VERSION 5.8 ;
BUSBITCHARS "[]" ;
DIVIDERCHAR "/" ;
UNITS
    DATABASE MICRONS 1000 ;
END UNITS

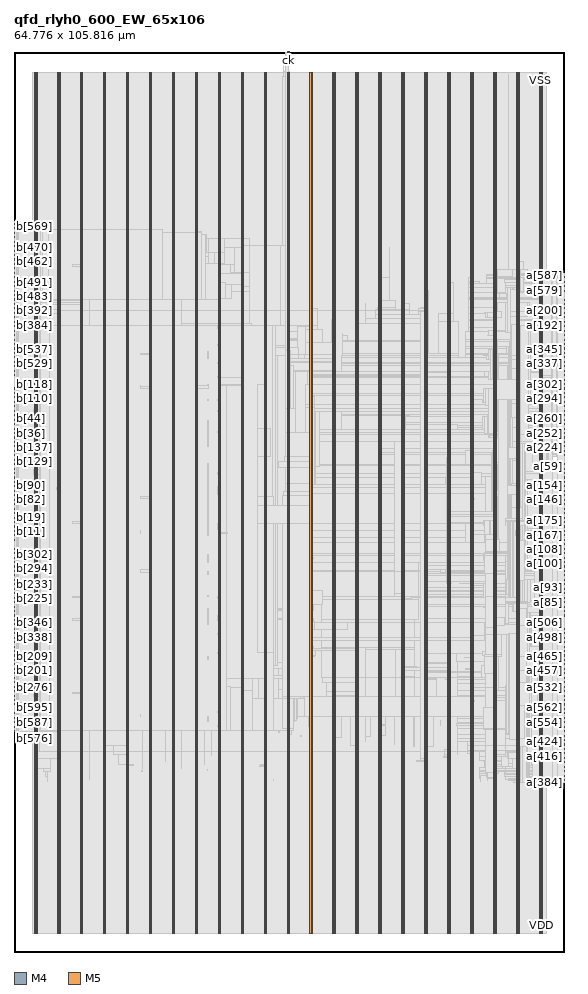
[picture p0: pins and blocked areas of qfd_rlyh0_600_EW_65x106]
MACRO qfd_rlyh0_600_EW_65x106
  FOREIGN qfd_rlyh0_600_EW_65x106 0 0 ;
  CLASS BLOCK ;
  SIZE 64.776 BY 105.816 ;
  PIN a[0]
    DIRECTION INPUT ;
    USE SIGNAL ;
    PORT
      LAYER M4 ;
        RECT  64.692 42.192 64.776 42.216 ;
    END
  END a[0]
  PIN a[100]
    DIRECTION INPUT ;
    USE SIGNAL ;
    PORT
      LAYER M4 ;
        RECT  64.692 45.648 64.776 45.672 ;
    END
  END a[100]
  PIN a[101]
    DIRECTION INPUT ;
    USE SIGNAL ;
    PORT
      LAYER M4 ;
        RECT  64.692 45.744 64.776 45.768 ;
    END
  END a[101]
  PIN a[102]
    DIRECTION INPUT ;
    USE SIGNAL ;
    PORT
      LAYER M4 ;
        RECT  64.692 45.84 64.776 45.864 ;
    END
  END a[102]
  PIN a[103]
    DIRECTION INPUT ;
    USE SIGNAL ;
    PORT
      LAYER M4 ;
        RECT  64.692 45.936 64.776 45.96 ;
    END
  END a[103]
  PIN a[104]
    DIRECTION INPUT ;
    USE SIGNAL ;
    PORT
      LAYER M4 ;
        RECT  64.692 46.032 64.776 46.056 ;
    END
  END a[104]
  PIN a[105]
    DIRECTION INPUT ;
    USE SIGNAL ;
    PORT
      LAYER M4 ;
        RECT  64.692 46.128 64.776 46.152 ;
    END
  END a[105]
  PIN a[106]
    DIRECTION INPUT ;
    USE SIGNAL ;
    PORT
      LAYER M4 ;
        RECT  64.692 46.224 64.776 46.248 ;
    END
  END a[106]
  PIN a[107]
    DIRECTION INPUT ;
    USE SIGNAL ;
    PORT
      LAYER M4 ;
        RECT  64.692 46.32 64.776 46.344 ;
    END
  END a[107]
  PIN a[108]
    DIRECTION INPUT ;
    USE SIGNAL ;
    PORT
      LAYER M4 ;
        RECT  64.692 46.416 64.776 46.44 ;
    END
  END a[108]
  PIN a[109]
    DIRECTION INPUT ;
    USE SIGNAL ;
    PORT
      LAYER M4 ;
        RECT  64.692 46.512 64.776 46.536 ;
    END
  END a[109]
  PIN a[10]
    DIRECTION INPUT ;
    USE SIGNAL ;
    PORT
      LAYER M4 ;
        RECT  64.692 43.152 64.776 43.176 ;
    END
  END a[10]
  PIN a[110]
    DIRECTION INPUT ;
    USE SIGNAL ;
    PORT
      LAYER M4 ;
        RECT  64.692 46.608 64.776 46.632 ;
    END
  END a[110]
  PIN a[111]
    DIRECTION INPUT ;
    USE SIGNAL ;
    PORT
      LAYER M4 ;
        RECT  64.692 46.704 64.776 46.728 ;
    END
  END a[111]
  PIN a[112]
    DIRECTION INPUT ;
    USE SIGNAL ;
    PORT
      LAYER M4 ;
        RECT  64.692 46.8 64.776 46.824 ;
    END
  END a[112]
  PIN a[113]
    DIRECTION INPUT ;
    USE SIGNAL ;
    PORT
      LAYER M4 ;
        RECT  64.692 46.896 64.776 46.92 ;
    END
  END a[113]
  PIN a[114]
    DIRECTION INPUT ;
    USE SIGNAL ;
    PORT
      LAYER M4 ;
        RECT  64.692 46.992 64.776 47.016 ;
    END
  END a[114]
  PIN a[115]
    DIRECTION INPUT ;
    USE SIGNAL ;
    PORT
      LAYER M4 ;
        RECT  64.692 47.088 64.776 47.112 ;
    END
  END a[115]
  PIN a[116]
    DIRECTION INPUT ;
    USE SIGNAL ;
    PORT
      LAYER M4 ;
        RECT  64.692 47.184 64.776 47.208 ;
    END
  END a[116]
  PIN a[117]
    DIRECTION INPUT ;
    USE SIGNAL ;
    PORT
      LAYER M4 ;
        RECT  64.692 47.28 64.776 47.304 ;
    END
  END a[117]
  PIN a[118]
    DIRECTION INPUT ;
    USE SIGNAL ;
    PORT
      LAYER M4 ;
        RECT  64.692 47.376 64.776 47.4 ;
    END
  END a[118]
  PIN a[119]
    DIRECTION INPUT ;
    USE SIGNAL ;
    PORT
      LAYER M4 ;
        RECT  64.692 47.472 64.776 47.496 ;
    END
  END a[119]
  PIN a[11]
    DIRECTION INPUT ;
    USE SIGNAL ;
    PORT
      LAYER M4 ;
        RECT  64.692 43.248 64.776 43.272 ;
    END
  END a[11]
  PIN a[120]
    DIRECTION INPUT ;
    USE SIGNAL ;
    PORT
      LAYER M4 ;
        RECT  64.692 47.568 64.776 47.592 ;
    END
  END a[120]
  PIN a[121]
    DIRECTION INPUT ;
    USE SIGNAL ;
    PORT
      LAYER M4 ;
        RECT  64.692 47.664 64.776 47.688 ;
    END
  END a[121]
  PIN a[122]
    DIRECTION INPUT ;
    USE SIGNAL ;
    PORT
      LAYER M4 ;
        RECT  64.692 47.76 64.776 47.784 ;
    END
  END a[122]
  PIN a[123]
    DIRECTION INPUT ;
    USE SIGNAL ;
    PORT
      LAYER M4 ;
        RECT  64.692 47.856 64.776 47.88 ;
    END
  END a[123]
  PIN a[124]
    DIRECTION INPUT ;
    USE SIGNAL ;
    PORT
      LAYER M4 ;
        RECT  64.692 47.952 64.776 47.976 ;
    END
  END a[124]
  PIN a[125]
    DIRECTION INPUT ;
    USE SIGNAL ;
    PORT
      LAYER M4 ;
        RECT  64.692 48.048 64.776 48.072 ;
    END
  END a[125]
  PIN a[126]
    DIRECTION INPUT ;
    USE SIGNAL ;
    PORT
      LAYER M4 ;
        RECT  64.692 48.144 64.776 48.168 ;
    END
  END a[126]
  PIN a[127]
    DIRECTION INPUT ;
    USE SIGNAL ;
    PORT
      LAYER M4 ;
        RECT  64.692 48.24 64.776 48.264 ;
    END
  END a[127]
  PIN a[128]
    DIRECTION INPUT ;
    USE SIGNAL ;
    PORT
      LAYER M4 ;
        RECT  64.692 51.408 64.776 51.432 ;
    END
  END a[128]
  PIN a[129]
    DIRECTION INPUT ;
    USE SIGNAL ;
    PORT
      LAYER M4 ;
        RECT  64.692 51.504 64.776 51.528 ;
    END
  END a[129]
  PIN a[12]
    DIRECTION INPUT ;
    USE SIGNAL ;
    PORT
      LAYER M4 ;
        RECT  64.692 43.344 64.776 43.368 ;
    END
  END a[12]
  PIN a[130]
    DIRECTION INPUT ;
    USE SIGNAL ;
    PORT
      LAYER M4 ;
        RECT  64.692 51.6 64.776 51.624 ;
    END
  END a[130]
  PIN a[131]
    DIRECTION INPUT ;
    USE SIGNAL ;
    PORT
      LAYER M4 ;
        RECT  64.692 51.696 64.776 51.72 ;
    END
  END a[131]
  PIN a[132]
    DIRECTION INPUT ;
    USE SIGNAL ;
    PORT
      LAYER M4 ;
        RECT  64.692 51.792 64.776 51.816 ;
    END
  END a[132]
  PIN a[133]
    DIRECTION INPUT ;
    USE SIGNAL ;
    PORT
      LAYER M4 ;
        RECT  64.692 51.888 64.776 51.912 ;
    END
  END a[133]
  PIN a[134]
    DIRECTION INPUT ;
    USE SIGNAL ;
    PORT
      LAYER M4 ;
        RECT  64.692 51.984 64.776 52.008 ;
    END
  END a[134]
  PIN a[135]
    DIRECTION INPUT ;
    USE SIGNAL ;
    PORT
      LAYER M4 ;
        RECT  64.692 52.08 64.776 52.104 ;
    END
  END a[135]
  PIN a[136]
    DIRECTION INPUT ;
    USE SIGNAL ;
    PORT
      LAYER M4 ;
        RECT  64.692 52.176 64.776 52.2 ;
    END
  END a[136]
  PIN a[137]
    DIRECTION INPUT ;
    USE SIGNAL ;
    PORT
      LAYER M4 ;
        RECT  64.692 52.272 64.776 52.296 ;
    END
  END a[137]
  PIN a[138]
    DIRECTION INPUT ;
    USE SIGNAL ;
    PORT
      LAYER M4 ;
        RECT  64.692 52.368 64.776 52.392 ;
    END
  END a[138]
  PIN a[139]
    DIRECTION INPUT ;
    USE SIGNAL ;
    PORT
      LAYER M4 ;
        RECT  64.692 52.464 64.776 52.488 ;
    END
  END a[139]
  PIN a[13]
    DIRECTION INPUT ;
    USE SIGNAL ;
    PORT
      LAYER M4 ;
        RECT  64.692 43.44 64.776 43.464 ;
    END
  END a[13]
  PIN a[140]
    DIRECTION INPUT ;
    USE SIGNAL ;
    PORT
      LAYER M4 ;
        RECT  64.692 52.56 64.776 52.584 ;
    END
  END a[140]
  PIN a[141]
    DIRECTION INPUT ;
    USE SIGNAL ;
    PORT
      LAYER M4 ;
        RECT  64.692 52.656 64.776 52.68 ;
    END
  END a[141]
  PIN a[142]
    DIRECTION INPUT ;
    USE SIGNAL ;
    PORT
      LAYER M4 ;
        RECT  64.692 52.752 64.776 52.776 ;
    END
  END a[142]
  PIN a[143]
    DIRECTION INPUT ;
    USE SIGNAL ;
    PORT
      LAYER M4 ;
        RECT  64.692 52.848 64.776 52.872 ;
    END
  END a[143]
  PIN a[144]
    DIRECTION INPUT ;
    USE SIGNAL ;
    PORT
      LAYER M4 ;
        RECT  64.692 52.944 64.776 52.968 ;
    END
  END a[144]
  PIN a[145]
    DIRECTION INPUT ;
    USE SIGNAL ;
    PORT
      LAYER M4 ;
        RECT  64.692 53.04 64.776 53.064 ;
    END
  END a[145]
  PIN a[146]
    DIRECTION INPUT ;
    USE SIGNAL ;
    PORT
      LAYER M4 ;
        RECT  64.692 53.136 64.776 53.16 ;
    END
  END a[146]
  PIN a[147]
    DIRECTION INPUT ;
    USE SIGNAL ;
    PORT
      LAYER M4 ;
        RECT  64.692 53.232 64.776 53.256 ;
    END
  END a[147]
  PIN a[148]
    DIRECTION INPUT ;
    USE SIGNAL ;
    PORT
      LAYER M4 ;
        RECT  64.692 53.328 64.776 53.352 ;
    END
  END a[148]
  PIN a[149]
    DIRECTION INPUT ;
    USE SIGNAL ;
    PORT
      LAYER M4 ;
        RECT  64.692 53.424 64.776 53.448 ;
    END
  END a[149]
  PIN a[14]
    DIRECTION INPUT ;
    USE SIGNAL ;
    PORT
      LAYER M4 ;
        RECT  64.692 43.536 64.776 43.56 ;
    END
  END a[14]
  PIN a[150]
    DIRECTION INPUT ;
    USE SIGNAL ;
    PORT
      LAYER M4 ;
        RECT  64.692 53.52 64.776 53.544 ;
    END
  END a[150]
  PIN a[151]
    DIRECTION INPUT ;
    USE SIGNAL ;
    PORT
      LAYER M4 ;
        RECT  64.692 53.616 64.776 53.64 ;
    END
  END a[151]
  PIN a[152]
    DIRECTION INPUT ;
    USE SIGNAL ;
    PORT
      LAYER M4 ;
        RECT  64.692 53.712 64.776 53.736 ;
    END
  END a[152]
  PIN a[153]
    DIRECTION INPUT ;
    USE SIGNAL ;
    PORT
      LAYER M4 ;
        RECT  64.692 53.808 64.776 53.832 ;
    END
  END a[153]
  PIN a[154]
    DIRECTION INPUT ;
    USE SIGNAL ;
    PORT
      LAYER M4 ;
        RECT  64.692 53.904 64.776 53.928 ;
    END
  END a[154]
  PIN a[155]
    DIRECTION INPUT ;
    USE SIGNAL ;
    PORT
      LAYER M4 ;
        RECT  64.692 54 64.776 54.024 ;
    END
  END a[155]
  PIN a[156]
    DIRECTION INPUT ;
    USE SIGNAL ;
    PORT
      LAYER M4 ;
        RECT  64.692 54.096 64.776 54.12 ;
    END
  END a[156]
  PIN a[157]
    DIRECTION INPUT ;
    USE SIGNAL ;
    PORT
      LAYER M4 ;
        RECT  64.692 54.192 64.776 54.216 ;
    END
  END a[157]
  PIN a[158]
    DIRECTION INPUT ;
    USE SIGNAL ;
    PORT
      LAYER M4 ;
        RECT  64.692 54.288 64.776 54.312 ;
    END
  END a[158]
  PIN a[159]
    DIRECTION INPUT ;
    USE SIGNAL ;
    PORT
      LAYER M4 ;
        RECT  64.692 54.384 64.776 54.408 ;
    END
  END a[159]
  PIN a[15]
    DIRECTION INPUT ;
    USE SIGNAL ;
    PORT
      LAYER M4 ;
        RECT  64.692 43.632 64.776 43.656 ;
    END
  END a[15]
  PIN a[160]
    DIRECTION INPUT ;
    USE SIGNAL ;
    PORT
      LAYER M4 ;
        RECT  64.692 48.336 64.776 48.36 ;
    END
  END a[160]
  PIN a[161]
    DIRECTION INPUT ;
    USE SIGNAL ;
    PORT
      LAYER M4 ;
        RECT  64.692 48.432 64.776 48.456 ;
    END
  END a[161]
  PIN a[162]
    DIRECTION INPUT ;
    USE SIGNAL ;
    PORT
      LAYER M4 ;
        RECT  64.692 48.528 64.776 48.552 ;
    END
  END a[162]
  PIN a[163]
    DIRECTION INPUT ;
    USE SIGNAL ;
    PORT
      LAYER M4 ;
        RECT  64.692 48.624 64.776 48.648 ;
    END
  END a[163]
  PIN a[164]
    DIRECTION INPUT ;
    USE SIGNAL ;
    PORT
      LAYER M4 ;
        RECT  64.692 48.72 64.776 48.744 ;
    END
  END a[164]
  PIN a[165]
    DIRECTION INPUT ;
    USE SIGNAL ;
    PORT
      LAYER M4 ;
        RECT  64.692 48.816 64.776 48.84 ;
    END
  END a[165]
  PIN a[166]
    DIRECTION INPUT ;
    USE SIGNAL ;
    PORT
      LAYER M4 ;
        RECT  64.692 48.912 64.776 48.936 ;
    END
  END a[166]
  PIN a[167]
    DIRECTION INPUT ;
    USE SIGNAL ;
    PORT
      LAYER M4 ;
        RECT  64.692 49.008 64.776 49.032 ;
    END
  END a[167]
  PIN a[168]
    DIRECTION INPUT ;
    USE SIGNAL ;
    PORT
      LAYER M4 ;
        RECT  64.692 49.104 64.776 49.128 ;
    END
  END a[168]
  PIN a[169]
    DIRECTION INPUT ;
    USE SIGNAL ;
    PORT
      LAYER M4 ;
        RECT  64.692 49.2 64.776 49.224 ;
    END
  END a[169]
  PIN a[16]
    DIRECTION INPUT ;
    USE SIGNAL ;
    PORT
      LAYER M4 ;
        RECT  64.692 43.728 64.776 43.752 ;
    END
  END a[16]
  PIN a[170]
    DIRECTION INPUT ;
    USE SIGNAL ;
    PORT
      LAYER M4 ;
        RECT  64.692 49.296 64.776 49.32 ;
    END
  END a[170]
  PIN a[171]
    DIRECTION INPUT ;
    USE SIGNAL ;
    PORT
      LAYER M4 ;
        RECT  64.692 49.392 64.776 49.416 ;
    END
  END a[171]
  PIN a[172]
    DIRECTION INPUT ;
    USE SIGNAL ;
    PORT
      LAYER M4 ;
        RECT  64.692 49.488 64.776 49.512 ;
    END
  END a[172]
  PIN a[173]
    DIRECTION INPUT ;
    USE SIGNAL ;
    PORT
      LAYER M4 ;
        RECT  64.692 49.584 64.776 49.608 ;
    END
  END a[173]
  PIN a[174]
    DIRECTION INPUT ;
    USE SIGNAL ;
    PORT
      LAYER M4 ;
        RECT  64.692 49.68 64.776 49.704 ;
    END
  END a[174]
  PIN a[175]
    DIRECTION INPUT ;
    USE SIGNAL ;
    PORT
      LAYER M4 ;
        RECT  64.692 49.776 64.776 49.8 ;
    END
  END a[175]
  PIN a[176]
    DIRECTION INPUT ;
    USE SIGNAL ;
    PORT
      LAYER M4 ;
        RECT  64.692 49.872 64.776 49.896 ;
    END
  END a[176]
  PIN a[177]
    DIRECTION INPUT ;
    USE SIGNAL ;
    PORT
      LAYER M4 ;
        RECT  64.692 49.968 64.776 49.992 ;
    END
  END a[177]
  PIN a[178]
    DIRECTION INPUT ;
    USE SIGNAL ;
    PORT
      LAYER M4 ;
        RECT  64.692 50.064 64.776 50.088 ;
    END
  END a[178]
  PIN a[179]
    DIRECTION INPUT ;
    USE SIGNAL ;
    PORT
      LAYER M4 ;
        RECT  64.692 50.16 64.776 50.184 ;
    END
  END a[179]
  PIN a[17]
    DIRECTION INPUT ;
    USE SIGNAL ;
    PORT
      LAYER M4 ;
        RECT  64.692 43.824 64.776 43.848 ;
    END
  END a[17]
  PIN a[180]
    DIRECTION INPUT ;
    USE SIGNAL ;
    PORT
      LAYER M4 ;
        RECT  64.692 50.256 64.776 50.28 ;
    END
  END a[180]
  PIN a[181]
    DIRECTION INPUT ;
    USE SIGNAL ;
    PORT
      LAYER M4 ;
        RECT  64.692 50.352 64.776 50.376 ;
    END
  END a[181]
  PIN a[182]
    DIRECTION INPUT ;
    USE SIGNAL ;
    PORT
      LAYER M4 ;
        RECT  64.692 50.448 64.776 50.472 ;
    END
  END a[182]
  PIN a[183]
    DIRECTION INPUT ;
    USE SIGNAL ;
    PORT
      LAYER M4 ;
        RECT  64.692 50.544 64.776 50.568 ;
    END
  END a[183]
  PIN a[184]
    DIRECTION INPUT ;
    USE SIGNAL ;
    PORT
      LAYER M4 ;
        RECT  64.692 50.64 64.776 50.664 ;
    END
  END a[184]
  PIN a[185]
    DIRECTION INPUT ;
    USE SIGNAL ;
    PORT
      LAYER M4 ;
        RECT  64.692 50.736 64.776 50.76 ;
    END
  END a[185]
  PIN a[186]
    DIRECTION INPUT ;
    USE SIGNAL ;
    PORT
      LAYER M4 ;
        RECT  64.692 50.832 64.776 50.856 ;
    END
  END a[186]
  PIN a[187]
    DIRECTION INPUT ;
    USE SIGNAL ;
    PORT
      LAYER M4 ;
        RECT  64.692 50.928 64.776 50.952 ;
    END
  END a[187]
  PIN a[188]
    DIRECTION INPUT ;
    USE SIGNAL ;
    PORT
      LAYER M4 ;
        RECT  64.692 51.024 64.776 51.048 ;
    END
  END a[188]
  PIN a[189]
    DIRECTION INPUT ;
    USE SIGNAL ;
    PORT
      LAYER M4 ;
        RECT  64.692 51.12 64.776 51.144 ;
    END
  END a[189]
  PIN a[18]
    DIRECTION INPUT ;
    USE SIGNAL ;
    PORT
      LAYER M4 ;
        RECT  64.692 43.92 64.776 43.944 ;
    END
  END a[18]
  PIN a[190]
    DIRECTION INPUT ;
    USE SIGNAL ;
    PORT
      LAYER M4 ;
        RECT  64.692 51.216 64.776 51.24 ;
    END
  END a[190]
  PIN a[191]
    DIRECTION INPUT ;
    USE SIGNAL ;
    PORT
      LAYER M4 ;
        RECT  64.692 51.312 64.776 51.336 ;
    END
  END a[191]
  PIN a[192]
    DIRECTION INPUT ;
    USE SIGNAL ;
    PORT
      LAYER M4 ;
        RECT  64.692 73.68 64.776 73.704 ;
    END
  END a[192]
  PIN a[193]
    DIRECTION INPUT ;
    USE SIGNAL ;
    PORT
      LAYER M4 ;
        RECT  64.692 73.776 64.776 73.8 ;
    END
  END a[193]
  PIN a[194]
    DIRECTION INPUT ;
    USE SIGNAL ;
    PORT
      LAYER M4 ;
        RECT  64.692 73.872 64.776 73.896 ;
    END
  END a[194]
  PIN a[195]
    DIRECTION INPUT ;
    USE SIGNAL ;
    PORT
      LAYER M4 ;
        RECT  64.692 73.968 64.776 73.992 ;
    END
  END a[195]
  PIN a[196]
    DIRECTION INPUT ;
    USE SIGNAL ;
    PORT
      LAYER M4 ;
        RECT  64.692 74.064 64.776 74.088 ;
    END
  END a[196]
  PIN a[197]
    DIRECTION INPUT ;
    USE SIGNAL ;
    PORT
      LAYER M4 ;
        RECT  64.692 74.16 64.776 74.184 ;
    END
  END a[197]
  PIN a[198]
    DIRECTION INPUT ;
    USE SIGNAL ;
    PORT
      LAYER M4 ;
        RECT  64.692 74.256 64.776 74.28 ;
    END
  END a[198]
  PIN a[199]
    DIRECTION INPUT ;
    USE SIGNAL ;
    PORT
      LAYER M4 ;
        RECT  64.692 74.352 64.776 74.376 ;
    END
  END a[199]
  PIN a[19]
    DIRECTION INPUT ;
    USE SIGNAL ;
    PORT
      LAYER M4 ;
        RECT  64.692 44.016 64.776 44.04 ;
    END
  END a[19]
  PIN a[1]
    DIRECTION INPUT ;
    USE SIGNAL ;
    PORT
      LAYER M4 ;
        RECT  64.692 42.288 64.776 42.312 ;
    END
  END a[1]
  PIN a[200]
    DIRECTION INPUT ;
    USE SIGNAL ;
    PORT
      LAYER M4 ;
        RECT  64.692 74.448 64.776 74.472 ;
    END
  END a[200]
  PIN a[201]
    DIRECTION INPUT ;
    USE SIGNAL ;
    PORT
      LAYER M4 ;
        RECT  64.692 74.544 64.776 74.568 ;
    END
  END a[201]
  PIN a[202]
    DIRECTION INPUT ;
    USE SIGNAL ;
    PORT
      LAYER M4 ;
        RECT  64.692 74.64 64.776 74.664 ;
    END
  END a[202]
  PIN a[203]
    DIRECTION INPUT ;
    USE SIGNAL ;
    PORT
      LAYER M4 ;
        RECT  64.692 74.736 64.776 74.76 ;
    END
  END a[203]
  PIN a[204]
    DIRECTION INPUT ;
    USE SIGNAL ;
    PORT
      LAYER M4 ;
        RECT  64.692 74.832 64.776 74.856 ;
    END
  END a[204]
  PIN a[205]
    DIRECTION INPUT ;
    USE SIGNAL ;
    PORT
      LAYER M4 ;
        RECT  64.692 74.928 64.776 74.952 ;
    END
  END a[205]
  PIN a[206]
    DIRECTION INPUT ;
    USE SIGNAL ;
    PORT
      LAYER M4 ;
        RECT  64.692 75.024 64.776 75.048 ;
    END
  END a[206]
  PIN a[207]
    DIRECTION INPUT ;
    USE SIGNAL ;
    PORT
      LAYER M4 ;
        RECT  64.692 75.12 64.776 75.144 ;
    END
  END a[207]
  PIN a[208]
    DIRECTION INPUT ;
    USE SIGNAL ;
    PORT
      LAYER M4 ;
        RECT  64.692 75.216 64.776 75.24 ;
    END
  END a[208]
  PIN a[209]
    DIRECTION INPUT ;
    USE SIGNAL ;
    PORT
      LAYER M4 ;
        RECT  64.692 75.312 64.776 75.336 ;
    END
  END a[209]
  PIN a[20]
    DIRECTION INPUT ;
    USE SIGNAL ;
    PORT
      LAYER M4 ;
        RECT  64.692 44.112 64.776 44.136 ;
    END
  END a[20]
  PIN a[210]
    DIRECTION INPUT ;
    USE SIGNAL ;
    PORT
      LAYER M4 ;
        RECT  64.692 75.408 64.776 75.432 ;
    END
  END a[210]
  PIN a[211]
    DIRECTION INPUT ;
    USE SIGNAL ;
    PORT
      LAYER M4 ;
        RECT  64.692 75.504 64.776 75.528 ;
    END
  END a[211]
  PIN a[212]
    DIRECTION INPUT ;
    USE SIGNAL ;
    PORT
      LAYER M4 ;
        RECT  64.692 75.6 64.776 75.624 ;
    END
  END a[212]
  PIN a[213]
    DIRECTION INPUT ;
    USE SIGNAL ;
    PORT
      LAYER M4 ;
        RECT  64.692 75.696 64.776 75.72 ;
    END
  END a[213]
  PIN a[214]
    DIRECTION INPUT ;
    USE SIGNAL ;
    PORT
      LAYER M4 ;
        RECT  64.692 75.792 64.776 75.816 ;
    END
  END a[214]
  PIN a[215]
    DIRECTION INPUT ;
    USE SIGNAL ;
    PORT
      LAYER M4 ;
        RECT  64.692 75.888 64.776 75.912 ;
    END
  END a[215]
  PIN a[216]
    DIRECTION INPUT ;
    USE SIGNAL ;
    PORT
      LAYER M4 ;
        RECT  64.692 75.984 64.776 76.008 ;
    END
  END a[216]
  PIN a[217]
    DIRECTION INPUT ;
    USE SIGNAL ;
    PORT
      LAYER M4 ;
        RECT  64.692 76.08 64.776 76.104 ;
    END
  END a[217]
  PIN a[218]
    DIRECTION INPUT ;
    USE SIGNAL ;
    PORT
      LAYER M4 ;
        RECT  64.692 76.176 64.776 76.2 ;
    END
  END a[218]
  PIN a[219]
    DIRECTION INPUT ;
    USE SIGNAL ;
    PORT
      LAYER M4 ;
        RECT  64.692 76.272 64.776 76.296 ;
    END
  END a[219]
  PIN a[21]
    DIRECTION INPUT ;
    USE SIGNAL ;
    PORT
      LAYER M4 ;
        RECT  64.692 44.208 64.776 44.232 ;
    END
  END a[21]
  PIN a[220]
    DIRECTION INPUT ;
    USE SIGNAL ;
    PORT
      LAYER M4 ;
        RECT  64.692 76.368 64.776 76.392 ;
    END
  END a[220]
  PIN a[221]
    DIRECTION INPUT ;
    USE SIGNAL ;
    PORT
      LAYER M4 ;
        RECT  64.692 76.464 64.776 76.488 ;
    END
  END a[221]
  PIN a[222]
    DIRECTION INPUT ;
    USE SIGNAL ;
    PORT
      LAYER M4 ;
        RECT  64.692 76.56 64.776 76.584 ;
    END
  END a[222]
  PIN a[223]
    DIRECTION INPUT ;
    USE SIGNAL ;
    PORT
      LAYER M4 ;
        RECT  64.692 76.656 64.776 76.68 ;
    END
  END a[223]
  PIN a[224]
    DIRECTION INPUT ;
    USE SIGNAL ;
    PORT
      LAYER M4 ;
        RECT  64.692 58.32 64.776 58.344 ;
    END
  END a[224]
  PIN a[225]
    DIRECTION INPUT ;
    USE SIGNAL ;
    PORT
      LAYER M4 ;
        RECT  64.692 58.416 64.776 58.44 ;
    END
  END a[225]
  PIN a[226]
    DIRECTION INPUT ;
    USE SIGNAL ;
    PORT
      LAYER M4 ;
        RECT  64.692 58.512 64.776 58.536 ;
    END
  END a[226]
  PIN a[227]
    DIRECTION INPUT ;
    USE SIGNAL ;
    PORT
      LAYER M4 ;
        RECT  64.692 58.608 64.776 58.632 ;
    END
  END a[227]
  PIN a[228]
    DIRECTION INPUT ;
    USE SIGNAL ;
    PORT
      LAYER M4 ;
        RECT  64.692 58.704 64.776 58.728 ;
    END
  END a[228]
  PIN a[229]
    DIRECTION INPUT ;
    USE SIGNAL ;
    PORT
      LAYER M4 ;
        RECT  64.692 58.8 64.776 58.824 ;
    END
  END a[229]
  PIN a[22]
    DIRECTION INPUT ;
    USE SIGNAL ;
    PORT
      LAYER M4 ;
        RECT  64.692 44.304 64.776 44.328 ;
    END
  END a[22]
  PIN a[230]
    DIRECTION INPUT ;
    USE SIGNAL ;
    PORT
      LAYER M4 ;
        RECT  64.692 58.896 64.776 58.92 ;
    END
  END a[230]
  PIN a[231]
    DIRECTION INPUT ;
    USE SIGNAL ;
    PORT
      LAYER M4 ;
        RECT  64.692 58.992 64.776 59.016 ;
    END
  END a[231]
  PIN a[232]
    DIRECTION INPUT ;
    USE SIGNAL ;
    PORT
      LAYER M4 ;
        RECT  64.692 59.088 64.776 59.112 ;
    END
  END a[232]
  PIN a[233]
    DIRECTION INPUT ;
    USE SIGNAL ;
    PORT
      LAYER M4 ;
        RECT  64.692 59.184 64.776 59.208 ;
    END
  END a[233]
  PIN a[234]
    DIRECTION INPUT ;
    USE SIGNAL ;
    PORT
      LAYER M4 ;
        RECT  64.692 59.28 64.776 59.304 ;
    END
  END a[234]
  PIN a[235]
    DIRECTION INPUT ;
    USE SIGNAL ;
    PORT
      LAYER M4 ;
        RECT  64.692 59.376 64.776 59.4 ;
    END
  END a[235]
  PIN a[236]
    DIRECTION INPUT ;
    USE SIGNAL ;
    PORT
      LAYER M4 ;
        RECT  64.692 59.472 64.776 59.496 ;
    END
  END a[236]
  PIN a[237]
    DIRECTION INPUT ;
    USE SIGNAL ;
    PORT
      LAYER M4 ;
        RECT  64.692 59.568 64.776 59.592 ;
    END
  END a[237]
  PIN a[238]
    DIRECTION INPUT ;
    USE SIGNAL ;
    PORT
      LAYER M4 ;
        RECT  64.692 59.664 64.776 59.688 ;
    END
  END a[238]
  PIN a[239]
    DIRECTION INPUT ;
    USE SIGNAL ;
    PORT
      LAYER M4 ;
        RECT  64.692 59.76 64.776 59.784 ;
    END
  END a[239]
  PIN a[23]
    DIRECTION INPUT ;
    USE SIGNAL ;
    PORT
      LAYER M4 ;
        RECT  64.692 44.4 64.776 44.424 ;
    END
  END a[23]
  PIN a[240]
    DIRECTION INPUT ;
    USE SIGNAL ;
    PORT
      LAYER M4 ;
        RECT  64.692 59.856 64.776 59.88 ;
    END
  END a[240]
  PIN a[241]
    DIRECTION INPUT ;
    USE SIGNAL ;
    PORT
      LAYER M4 ;
        RECT  64.692 59.952 64.776 59.976 ;
    END
  END a[241]
  PIN a[242]
    DIRECTION INPUT ;
    USE SIGNAL ;
    PORT
      LAYER M4 ;
        RECT  64.692 60.048 64.776 60.072 ;
    END
  END a[242]
  PIN a[243]
    DIRECTION INPUT ;
    USE SIGNAL ;
    PORT
      LAYER M4 ;
        RECT  64.692 60.144 64.776 60.168 ;
    END
  END a[243]
  PIN a[244]
    DIRECTION INPUT ;
    USE SIGNAL ;
    PORT
      LAYER M4 ;
        RECT  64.692 60.24 64.776 60.264 ;
    END
  END a[244]
  PIN a[245]
    DIRECTION INPUT ;
    USE SIGNAL ;
    PORT
      LAYER M4 ;
        RECT  64.692 60.336 64.776 60.36 ;
    END
  END a[245]
  PIN a[246]
    DIRECTION INPUT ;
    USE SIGNAL ;
    PORT
      LAYER M4 ;
        RECT  64.692 60.432 64.776 60.456 ;
    END
  END a[246]
  PIN a[247]
    DIRECTION INPUT ;
    USE SIGNAL ;
    PORT
      LAYER M4 ;
        RECT  64.692 60.528 64.776 60.552 ;
    END
  END a[247]
  PIN a[248]
    DIRECTION INPUT ;
    USE SIGNAL ;
    PORT
      LAYER M4 ;
        RECT  64.692 60.624 64.776 60.648 ;
    END
  END a[248]
  PIN a[249]
    DIRECTION INPUT ;
    USE SIGNAL ;
    PORT
      LAYER M4 ;
        RECT  64.692 60.72 64.776 60.744 ;
    END
  END a[249]
  PIN a[24]
    DIRECTION INPUT ;
    USE SIGNAL ;
    PORT
      LAYER M4 ;
        RECT  64.692 44.496 64.776 44.52 ;
    END
  END a[24]
  PIN a[250]
    DIRECTION INPUT ;
    USE SIGNAL ;
    PORT
      LAYER M4 ;
        RECT  64.692 60.816 64.776 60.84 ;
    END
  END a[250]
  PIN a[251]
    DIRECTION INPUT ;
    USE SIGNAL ;
    PORT
      LAYER M4 ;
        RECT  64.692 60.912 64.776 60.936 ;
    END
  END a[251]
  PIN a[252]
    DIRECTION INPUT ;
    USE SIGNAL ;
    PORT
      LAYER M4 ;
        RECT  64.692 61.008 64.776 61.032 ;
    END
  END a[252]
  PIN a[253]
    DIRECTION INPUT ;
    USE SIGNAL ;
    PORT
      LAYER M4 ;
        RECT  64.692 61.104 64.776 61.128 ;
    END
  END a[253]
  PIN a[254]
    DIRECTION INPUT ;
    USE SIGNAL ;
    PORT
      LAYER M4 ;
        RECT  64.692 61.2 64.776 61.224 ;
    END
  END a[254]
  PIN a[255]
    DIRECTION INPUT ;
    USE SIGNAL ;
    PORT
      LAYER M4 ;
        RECT  64.692 61.296 64.776 61.32 ;
    END
  END a[255]
  PIN a[256]
    DIRECTION INPUT ;
    USE SIGNAL ;
    PORT
      LAYER M4 ;
        RECT  64.692 61.392 64.776 61.416 ;
    END
  END a[256]
  PIN a[257]
    DIRECTION INPUT ;
    USE SIGNAL ;
    PORT
      LAYER M4 ;
        RECT  64.692 61.488 64.776 61.512 ;
    END
  END a[257]
  PIN a[258]
    DIRECTION INPUT ;
    USE SIGNAL ;
    PORT
      LAYER M4 ;
        RECT  64.692 61.584 64.776 61.608 ;
    END
  END a[258]
  PIN a[259]
    DIRECTION INPUT ;
    USE SIGNAL ;
    PORT
      LAYER M4 ;
        RECT  64.692 61.68 64.776 61.704 ;
    END
  END a[259]
  PIN a[25]
    DIRECTION INPUT ;
    USE SIGNAL ;
    PORT
      LAYER M4 ;
        RECT  64.692 44.592 64.776 44.616 ;
    END
  END a[25]
  PIN a[260]
    DIRECTION INPUT ;
    USE SIGNAL ;
    PORT
      LAYER M4 ;
        RECT  64.692 61.776 64.776 61.8 ;
    END
  END a[260]
  PIN a[261]
    DIRECTION INPUT ;
    USE SIGNAL ;
    PORT
      LAYER M4 ;
        RECT  64.692 61.872 64.776 61.896 ;
    END
  END a[261]
  PIN a[262]
    DIRECTION INPUT ;
    USE SIGNAL ;
    PORT
      LAYER M4 ;
        RECT  64.692 61.968 64.776 61.992 ;
    END
  END a[262]
  PIN a[263]
    DIRECTION INPUT ;
    USE SIGNAL ;
    PORT
      LAYER M4 ;
        RECT  64.692 62.064 64.776 62.088 ;
    END
  END a[263]
  PIN a[264]
    DIRECTION INPUT ;
    USE SIGNAL ;
    PORT
      LAYER M4 ;
        RECT  64.692 62.16 64.776 62.184 ;
    END
  END a[264]
  PIN a[265]
    DIRECTION INPUT ;
    USE SIGNAL ;
    PORT
      LAYER M4 ;
        RECT  64.692 62.256 64.776 62.28 ;
    END
  END a[265]
  PIN a[266]
    DIRECTION INPUT ;
    USE SIGNAL ;
    PORT
      LAYER M4 ;
        RECT  64.692 62.352 64.776 62.376 ;
    END
  END a[266]
  PIN a[267]
    DIRECTION INPUT ;
    USE SIGNAL ;
    PORT
      LAYER M4 ;
        RECT  64.692 62.448 64.776 62.472 ;
    END
  END a[267]
  PIN a[268]
    DIRECTION INPUT ;
    USE SIGNAL ;
    PORT
      LAYER M4 ;
        RECT  64.692 62.544 64.776 62.568 ;
    END
  END a[268]
  PIN a[269]
    DIRECTION INPUT ;
    USE SIGNAL ;
    PORT
      LAYER M4 ;
        RECT  64.692 62.64 64.776 62.664 ;
    END
  END a[269]
  PIN a[26]
    DIRECTION INPUT ;
    USE SIGNAL ;
    PORT
      LAYER M4 ;
        RECT  64.692 44.688 64.776 44.712 ;
    END
  END a[26]
  PIN a[270]
    DIRECTION INPUT ;
    USE SIGNAL ;
    PORT
      LAYER M4 ;
        RECT  64.692 62.736 64.776 62.76 ;
    END
  END a[270]
  PIN a[271]
    DIRECTION INPUT ;
    USE SIGNAL ;
    PORT
      LAYER M4 ;
        RECT  64.692 62.832 64.776 62.856 ;
    END
  END a[271]
  PIN a[272]
    DIRECTION INPUT ;
    USE SIGNAL ;
    PORT
      LAYER M4 ;
        RECT  64.692 62.928 64.776 62.952 ;
    END
  END a[272]
  PIN a[273]
    DIRECTION INPUT ;
    USE SIGNAL ;
    PORT
      LAYER M4 ;
        RECT  64.692 63.024 64.776 63.048 ;
    END
  END a[273]
  PIN a[274]
    DIRECTION INPUT ;
    USE SIGNAL ;
    PORT
      LAYER M4 ;
        RECT  64.692 63.12 64.776 63.144 ;
    END
  END a[274]
  PIN a[275]
    DIRECTION INPUT ;
    USE SIGNAL ;
    PORT
      LAYER M4 ;
        RECT  64.692 63.216 64.776 63.24 ;
    END
  END a[275]
  PIN a[276]
    DIRECTION INPUT ;
    USE SIGNAL ;
    PORT
      LAYER M4 ;
        RECT  64.692 63.312 64.776 63.336 ;
    END
  END a[276]
  PIN a[277]
    DIRECTION INPUT ;
    USE SIGNAL ;
    PORT
      LAYER M4 ;
        RECT  64.692 63.408 64.776 63.432 ;
    END
  END a[277]
  PIN a[278]
    DIRECTION INPUT ;
    USE SIGNAL ;
    PORT
      LAYER M4 ;
        RECT  64.692 63.504 64.776 63.528 ;
    END
  END a[278]
  PIN a[279]
    DIRECTION INPUT ;
    USE SIGNAL ;
    PORT
      LAYER M4 ;
        RECT  64.692 63.6 64.776 63.624 ;
    END
  END a[279]
  PIN a[27]
    DIRECTION INPUT ;
    USE SIGNAL ;
    PORT
      LAYER M4 ;
        RECT  64.692 44.784 64.776 44.808 ;
    END
  END a[27]
  PIN a[280]
    DIRECTION INPUT ;
    USE SIGNAL ;
    PORT
      LAYER M4 ;
        RECT  64.692 63.696 64.776 63.72 ;
    END
  END a[280]
  PIN a[281]
    DIRECTION INPUT ;
    USE SIGNAL ;
    PORT
      LAYER M4 ;
        RECT  64.692 63.792 64.776 63.816 ;
    END
  END a[281]
  PIN a[282]
    DIRECTION INPUT ;
    USE SIGNAL ;
    PORT
      LAYER M4 ;
        RECT  64.692 63.888 64.776 63.912 ;
    END
  END a[282]
  PIN a[283]
    DIRECTION INPUT ;
    USE SIGNAL ;
    PORT
      LAYER M4 ;
        RECT  64.692 63.984 64.776 64.008 ;
    END
  END a[283]
  PIN a[284]
    DIRECTION INPUT ;
    USE SIGNAL ;
    PORT
      LAYER M4 ;
        RECT  64.692 64.08 64.776 64.104 ;
    END
  END a[284]
  PIN a[285]
    DIRECTION INPUT ;
    USE SIGNAL ;
    PORT
      LAYER M4 ;
        RECT  64.692 64.176 64.776 64.2 ;
    END
  END a[285]
  PIN a[286]
    DIRECTION INPUT ;
    USE SIGNAL ;
    PORT
      LAYER M4 ;
        RECT  64.692 64.272 64.776 64.296 ;
    END
  END a[286]
  PIN a[287]
    DIRECTION INPUT ;
    USE SIGNAL ;
    PORT
      LAYER M4 ;
        RECT  64.692 64.368 64.776 64.392 ;
    END
  END a[287]
  PIN a[288]
    DIRECTION INPUT ;
    USE SIGNAL ;
    PORT
      LAYER M4 ;
        RECT  64.692 64.464 64.776 64.488 ;
    END
  END a[288]
  PIN a[289]
    DIRECTION INPUT ;
    USE SIGNAL ;
    PORT
      LAYER M4 ;
        RECT  64.692 64.56 64.776 64.584 ;
    END
  END a[289]
  PIN a[28]
    DIRECTION INPUT ;
    USE SIGNAL ;
    PORT
      LAYER M4 ;
        RECT  64.692 44.88 64.776 44.904 ;
    END
  END a[28]
  PIN a[290]
    DIRECTION INPUT ;
    USE SIGNAL ;
    PORT
      LAYER M4 ;
        RECT  64.692 64.656 64.776 64.68 ;
    END
  END a[290]
  PIN a[291]
    DIRECTION INPUT ;
    USE SIGNAL ;
    PORT
      LAYER M4 ;
        RECT  64.692 64.752 64.776 64.776 ;
    END
  END a[291]
  PIN a[292]
    DIRECTION INPUT ;
    USE SIGNAL ;
    PORT
      LAYER M4 ;
        RECT  64.692 64.848 64.776 64.872 ;
    END
  END a[292]
  PIN a[293]
    DIRECTION INPUT ;
    USE SIGNAL ;
    PORT
      LAYER M4 ;
        RECT  64.692 64.944 64.776 64.968 ;
    END
  END a[293]
  PIN a[294]
    DIRECTION INPUT ;
    USE SIGNAL ;
    PORT
      LAYER M4 ;
        RECT  64.692 65.04 64.776 65.064 ;
    END
  END a[294]
  PIN a[295]
    DIRECTION INPUT ;
    USE SIGNAL ;
    PORT
      LAYER M4 ;
        RECT  64.692 65.136 64.776 65.16 ;
    END
  END a[295]
  PIN a[296]
    DIRECTION INPUT ;
    USE SIGNAL ;
    PORT
      LAYER M4 ;
        RECT  64.692 65.232 64.776 65.256 ;
    END
  END a[296]
  PIN a[297]
    DIRECTION INPUT ;
    USE SIGNAL ;
    PORT
      LAYER M4 ;
        RECT  64.692 65.328 64.776 65.352 ;
    END
  END a[297]
  PIN a[298]
    DIRECTION INPUT ;
    USE SIGNAL ;
    PORT
      LAYER M4 ;
        RECT  64.692 65.424 64.776 65.448 ;
    END
  END a[298]
  PIN a[299]
    DIRECTION INPUT ;
    USE SIGNAL ;
    PORT
      LAYER M4 ;
        RECT  64.692 65.52 64.776 65.544 ;
    END
  END a[299]
  PIN a[29]
    DIRECTION INPUT ;
    USE SIGNAL ;
    PORT
      LAYER M4 ;
        RECT  64.692 44.976 64.776 45 ;
    END
  END a[29]
  PIN a[2]
    DIRECTION INPUT ;
    USE SIGNAL ;
    PORT
      LAYER M4 ;
        RECT  64.692 42.384 64.776 42.408 ;
    END
  END a[2]
  PIN a[300]
    DIRECTION INPUT ;
    USE SIGNAL ;
    PORT
      LAYER M4 ;
        RECT  64.692 65.616 64.776 65.64 ;
    END
  END a[300]
  PIN a[301]
    DIRECTION INPUT ;
    USE SIGNAL ;
    PORT
      LAYER M4 ;
        RECT  64.692 65.712 64.776 65.736 ;
    END
  END a[301]
  PIN a[302]
    DIRECTION INPUT ;
    USE SIGNAL ;
    PORT
      LAYER M4 ;
        RECT  64.692 65.808 64.776 65.832 ;
    END
  END a[302]
  PIN a[303]
    DIRECTION INPUT ;
    USE SIGNAL ;
    PORT
      LAYER M4 ;
        RECT  64.692 65.904 64.776 65.928 ;
    END
  END a[303]
  PIN a[304]
    DIRECTION INPUT ;
    USE SIGNAL ;
    PORT
      LAYER M4 ;
        RECT  64.692 66 64.776 66.024 ;
    END
  END a[304]
  PIN a[305]
    DIRECTION INPUT ;
    USE SIGNAL ;
    PORT
      LAYER M4 ;
        RECT  64.692 66.096 64.776 66.12 ;
    END
  END a[305]
  PIN a[306]
    DIRECTION INPUT ;
    USE SIGNAL ;
    PORT
      LAYER M4 ;
        RECT  64.692 66.192 64.776 66.216 ;
    END
  END a[306]
  PIN a[307]
    DIRECTION INPUT ;
    USE SIGNAL ;
    PORT
      LAYER M4 ;
        RECT  64.692 66.288 64.776 66.312 ;
    END
  END a[307]
  PIN a[308]
    DIRECTION INPUT ;
    USE SIGNAL ;
    PORT
      LAYER M4 ;
        RECT  64.692 66.384 64.776 66.408 ;
    END
  END a[308]
  PIN a[309]
    DIRECTION INPUT ;
    USE SIGNAL ;
    PORT
      LAYER M4 ;
        RECT  64.692 66.48 64.776 66.504 ;
    END
  END a[309]
  PIN a[30]
    DIRECTION INPUT ;
    USE SIGNAL ;
    PORT
      LAYER M4 ;
        RECT  64.692 45.072 64.776 45.096 ;
    END
  END a[30]
  PIN a[310]
    DIRECTION INPUT ;
    USE SIGNAL ;
    PORT
      LAYER M4 ;
        RECT  64.692 66.576 64.776 66.6 ;
    END
  END a[310]
  PIN a[311]
    DIRECTION INPUT ;
    USE SIGNAL ;
    PORT
      LAYER M4 ;
        RECT  64.692 66.672 64.776 66.696 ;
    END
  END a[311]
  PIN a[312]
    DIRECTION INPUT ;
    USE SIGNAL ;
    PORT
      LAYER M4 ;
        RECT  64.692 66.768 64.776 66.792 ;
    END
  END a[312]
  PIN a[313]
    DIRECTION INPUT ;
    USE SIGNAL ;
    PORT
      LAYER M4 ;
        RECT  64.692 66.864 64.776 66.888 ;
    END
  END a[313]
  PIN a[314]
    DIRECTION INPUT ;
    USE SIGNAL ;
    PORT
      LAYER M4 ;
        RECT  64.692 66.96 64.776 66.984 ;
    END
  END a[314]
  PIN a[315]
    DIRECTION INPUT ;
    USE SIGNAL ;
    PORT
      LAYER M4 ;
        RECT  64.692 67.056 64.776 67.08 ;
    END
  END a[315]
  PIN a[316]
    DIRECTION INPUT ;
    USE SIGNAL ;
    PORT
      LAYER M4 ;
        RECT  64.692 67.152 64.776 67.176 ;
    END
  END a[316]
  PIN a[317]
    DIRECTION INPUT ;
    USE SIGNAL ;
    PORT
      LAYER M4 ;
        RECT  64.692 67.248 64.776 67.272 ;
    END
  END a[317]
  PIN a[318]
    DIRECTION INPUT ;
    USE SIGNAL ;
    PORT
      LAYER M4 ;
        RECT  64.692 67.344 64.776 67.368 ;
    END
  END a[318]
  PIN a[319]
    DIRECTION INPUT ;
    USE SIGNAL ;
    PORT
      LAYER M4 ;
        RECT  64.692 67.44 64.776 67.464 ;
    END
  END a[319]
  PIN a[31]
    DIRECTION INPUT ;
    USE SIGNAL ;
    PORT
      LAYER M4 ;
        RECT  64.692 45.168 64.776 45.192 ;
    END
  END a[31]
  PIN a[320]
    DIRECTION INPUT ;
    USE SIGNAL ;
    PORT
      LAYER M4 ;
        RECT  64.692 67.536 64.776 67.56 ;
    END
  END a[320]
  PIN a[321]
    DIRECTION INPUT ;
    USE SIGNAL ;
    PORT
      LAYER M4 ;
        RECT  64.692 67.632 64.776 67.656 ;
    END
  END a[321]
  PIN a[322]
    DIRECTION INPUT ;
    USE SIGNAL ;
    PORT
      LAYER M4 ;
        RECT  64.692 67.728 64.776 67.752 ;
    END
  END a[322]
  PIN a[323]
    DIRECTION INPUT ;
    USE SIGNAL ;
    PORT
      LAYER M4 ;
        RECT  64.692 67.824 64.776 67.848 ;
    END
  END a[323]
  PIN a[324]
    DIRECTION INPUT ;
    USE SIGNAL ;
    PORT
      LAYER M4 ;
        RECT  64.692 67.92 64.776 67.944 ;
    END
  END a[324]
  PIN a[325]
    DIRECTION INPUT ;
    USE SIGNAL ;
    PORT
      LAYER M4 ;
        RECT  64.692 68.016 64.776 68.04 ;
    END
  END a[325]
  PIN a[326]
    DIRECTION INPUT ;
    USE SIGNAL ;
    PORT
      LAYER M4 ;
        RECT  64.692 68.112 64.776 68.136 ;
    END
  END a[326]
  PIN a[327]
    DIRECTION INPUT ;
    USE SIGNAL ;
    PORT
      LAYER M4 ;
        RECT  64.692 68.208 64.776 68.232 ;
    END
  END a[327]
  PIN a[328]
    DIRECTION INPUT ;
    USE SIGNAL ;
    PORT
      LAYER M4 ;
        RECT  64.692 68.304 64.776 68.328 ;
    END
  END a[328]
  PIN a[329]
    DIRECTION INPUT ;
    USE SIGNAL ;
    PORT
      LAYER M4 ;
        RECT  64.692 68.4 64.776 68.424 ;
    END
  END a[329]
  PIN a[32]
    DIRECTION INPUT ;
    USE SIGNAL ;
    PORT
      LAYER M4 ;
        RECT  64.692 54.48 64.776 54.504 ;
    END
  END a[32]
  PIN a[330]
    DIRECTION INPUT ;
    USE SIGNAL ;
    PORT
      LAYER M4 ;
        RECT  64.692 68.496 64.776 68.52 ;
    END
  END a[330]
  PIN a[331]
    DIRECTION INPUT ;
    USE SIGNAL ;
    PORT
      LAYER M4 ;
        RECT  64.692 68.592 64.776 68.616 ;
    END
  END a[331]
  PIN a[332]
    DIRECTION INPUT ;
    USE SIGNAL ;
    PORT
      LAYER M4 ;
        RECT  64.692 68.688 64.776 68.712 ;
    END
  END a[332]
  PIN a[333]
    DIRECTION INPUT ;
    USE SIGNAL ;
    PORT
      LAYER M4 ;
        RECT  64.692 68.784 64.776 68.808 ;
    END
  END a[333]
  PIN a[334]
    DIRECTION INPUT ;
    USE SIGNAL ;
    PORT
      LAYER M4 ;
        RECT  64.692 68.88 64.776 68.904 ;
    END
  END a[334]
  PIN a[335]
    DIRECTION INPUT ;
    USE SIGNAL ;
    PORT
      LAYER M4 ;
        RECT  64.692 68.976 64.776 69 ;
    END
  END a[335]
  PIN a[336]
    DIRECTION INPUT ;
    USE SIGNAL ;
    PORT
      LAYER M4 ;
        RECT  64.692 69.072 64.776 69.096 ;
    END
  END a[336]
  PIN a[337]
    DIRECTION INPUT ;
    USE SIGNAL ;
    PORT
      LAYER M4 ;
        RECT  64.692 69.168 64.776 69.192 ;
    END
  END a[337]
  PIN a[338]
    DIRECTION INPUT ;
    USE SIGNAL ;
    PORT
      LAYER M4 ;
        RECT  64.692 69.264 64.776 69.288 ;
    END
  END a[338]
  PIN a[339]
    DIRECTION INPUT ;
    USE SIGNAL ;
    PORT
      LAYER M4 ;
        RECT  64.692 69.36 64.776 69.384 ;
    END
  END a[339]
  PIN a[33]
    DIRECTION INPUT ;
    USE SIGNAL ;
    PORT
      LAYER M4 ;
        RECT  64.692 54.576 64.776 54.6 ;
    END
  END a[33]
  PIN a[340]
    DIRECTION INPUT ;
    USE SIGNAL ;
    PORT
      LAYER M4 ;
        RECT  64.692 69.456 64.776 69.48 ;
    END
  END a[340]
  PIN a[341]
    DIRECTION INPUT ;
    USE SIGNAL ;
    PORT
      LAYER M4 ;
        RECT  64.692 69.552 64.776 69.576 ;
    END
  END a[341]
  PIN a[342]
    DIRECTION INPUT ;
    USE SIGNAL ;
    PORT
      LAYER M4 ;
        RECT  64.692 69.648 64.776 69.672 ;
    END
  END a[342]
  PIN a[343]
    DIRECTION INPUT ;
    USE SIGNAL ;
    PORT
      LAYER M4 ;
        RECT  64.692 69.744 64.776 69.768 ;
    END
  END a[343]
  PIN a[344]
    DIRECTION INPUT ;
    USE SIGNAL ;
    PORT
      LAYER M4 ;
        RECT  64.692 69.84 64.776 69.864 ;
    END
  END a[344]
  PIN a[345]
    DIRECTION INPUT ;
    USE SIGNAL ;
    PORT
      LAYER M4 ;
        RECT  64.692 69.936 64.776 69.96 ;
    END
  END a[345]
  PIN a[346]
    DIRECTION INPUT ;
    USE SIGNAL ;
    PORT
      LAYER M4 ;
        RECT  64.692 70.032 64.776 70.056 ;
    END
  END a[346]
  PIN a[347]
    DIRECTION INPUT ;
    USE SIGNAL ;
    PORT
      LAYER M4 ;
        RECT  64.692 70.128 64.776 70.152 ;
    END
  END a[347]
  PIN a[348]
    DIRECTION INPUT ;
    USE SIGNAL ;
    PORT
      LAYER M4 ;
        RECT  64.692 70.224 64.776 70.248 ;
    END
  END a[348]
  PIN a[349]
    DIRECTION INPUT ;
    USE SIGNAL ;
    PORT
      LAYER M4 ;
        RECT  64.692 70.32 64.776 70.344 ;
    END
  END a[349]
  PIN a[34]
    DIRECTION INPUT ;
    USE SIGNAL ;
    PORT
      LAYER M4 ;
        RECT  64.692 54.672 64.776 54.696 ;
    END
  END a[34]
  PIN a[350]
    DIRECTION INPUT ;
    USE SIGNAL ;
    PORT
      LAYER M4 ;
        RECT  64.692 70.416 64.776 70.44 ;
    END
  END a[350]
  PIN a[351]
    DIRECTION INPUT ;
    USE SIGNAL ;
    PORT
      LAYER M4 ;
        RECT  64.692 70.512 64.776 70.536 ;
    END
  END a[351]
  PIN a[352]
    DIRECTION INPUT ;
    USE SIGNAL ;
    PORT
      LAYER M4 ;
        RECT  64.692 70.608 64.776 70.632 ;
    END
  END a[352]
  PIN a[353]
    DIRECTION INPUT ;
    USE SIGNAL ;
    PORT
      LAYER M4 ;
        RECT  64.692 70.704 64.776 70.728 ;
    END
  END a[353]
  PIN a[354]
    DIRECTION INPUT ;
    USE SIGNAL ;
    PORT
      LAYER M4 ;
        RECT  64.692 70.8 64.776 70.824 ;
    END
  END a[354]
  PIN a[355]
    DIRECTION INPUT ;
    USE SIGNAL ;
    PORT
      LAYER M4 ;
        RECT  64.692 70.896 64.776 70.92 ;
    END
  END a[355]
  PIN a[356]
    DIRECTION INPUT ;
    USE SIGNAL ;
    PORT
      LAYER M4 ;
        RECT  64.692 70.992 64.776 71.016 ;
    END
  END a[356]
  PIN a[357]
    DIRECTION INPUT ;
    USE SIGNAL ;
    PORT
      LAYER M4 ;
        RECT  64.692 71.088 64.776 71.112 ;
    END
  END a[357]
  PIN a[358]
    DIRECTION INPUT ;
    USE SIGNAL ;
    PORT
      LAYER M4 ;
        RECT  64.692 71.184 64.776 71.208 ;
    END
  END a[358]
  PIN a[359]
    DIRECTION INPUT ;
    USE SIGNAL ;
    PORT
      LAYER M4 ;
        RECT  64.692 71.28 64.776 71.304 ;
    END
  END a[359]
  PIN a[35]
    DIRECTION INPUT ;
    USE SIGNAL ;
    PORT
      LAYER M4 ;
        RECT  64.692 54.768 64.776 54.792 ;
    END
  END a[35]
  PIN a[360]
    DIRECTION INPUT ;
    USE SIGNAL ;
    PORT
      LAYER M4 ;
        RECT  64.692 71.376 64.776 71.4 ;
    END
  END a[360]
  PIN a[361]
    DIRECTION INPUT ;
    USE SIGNAL ;
    PORT
      LAYER M4 ;
        RECT  64.692 71.472 64.776 71.496 ;
    END
  END a[361]
  PIN a[362]
    DIRECTION INPUT ;
    USE SIGNAL ;
    PORT
      LAYER M4 ;
        RECT  64.692 71.568 64.776 71.592 ;
    END
  END a[362]
  PIN a[363]
    DIRECTION INPUT ;
    USE SIGNAL ;
    PORT
      LAYER M4 ;
        RECT  64.692 71.664 64.776 71.688 ;
    END
  END a[363]
  PIN a[364]
    DIRECTION INPUT ;
    USE SIGNAL ;
    PORT
      LAYER M4 ;
        RECT  64.692 71.76 64.776 71.784 ;
    END
  END a[364]
  PIN a[365]
    DIRECTION INPUT ;
    USE SIGNAL ;
    PORT
      LAYER M4 ;
        RECT  64.692 71.856 64.776 71.88 ;
    END
  END a[365]
  PIN a[366]
    DIRECTION INPUT ;
    USE SIGNAL ;
    PORT
      LAYER M4 ;
        RECT  64.692 71.952 64.776 71.976 ;
    END
  END a[366]
  PIN a[367]
    DIRECTION INPUT ;
    USE SIGNAL ;
    PORT
      LAYER M4 ;
        RECT  64.692 72.048 64.776 72.072 ;
    END
  END a[367]
  PIN a[368]
    DIRECTION INPUT ;
    USE SIGNAL ;
    PORT
      LAYER M4 ;
        RECT  64.692 72.144 64.776 72.168 ;
    END
  END a[368]
  PIN a[369]
    DIRECTION INPUT ;
    USE SIGNAL ;
    PORT
      LAYER M4 ;
        RECT  64.692 72.24 64.776 72.264 ;
    END
  END a[369]
  PIN a[36]
    DIRECTION INPUT ;
    USE SIGNAL ;
    PORT
      LAYER M4 ;
        RECT  64.692 54.864 64.776 54.888 ;
    END
  END a[36]
  PIN a[370]
    DIRECTION INPUT ;
    USE SIGNAL ;
    PORT
      LAYER M4 ;
        RECT  64.692 72.336 64.776 72.36 ;
    END
  END a[370]
  PIN a[371]
    DIRECTION INPUT ;
    USE SIGNAL ;
    PORT
      LAYER M4 ;
        RECT  64.692 72.432 64.776 72.456 ;
    END
  END a[371]
  PIN a[372]
    DIRECTION INPUT ;
    USE SIGNAL ;
    PORT
      LAYER M4 ;
        RECT  64.692 72.528 64.776 72.552 ;
    END
  END a[372]
  PIN a[373]
    DIRECTION INPUT ;
    USE SIGNAL ;
    PORT
      LAYER M4 ;
        RECT  64.692 72.624 64.776 72.648 ;
    END
  END a[373]
  PIN a[374]
    DIRECTION INPUT ;
    USE SIGNAL ;
    PORT
      LAYER M4 ;
        RECT  64.692 72.72 64.776 72.744 ;
    END
  END a[374]
  PIN a[375]
    DIRECTION INPUT ;
    USE SIGNAL ;
    PORT
      LAYER M4 ;
        RECT  64.692 72.816 64.776 72.84 ;
    END
  END a[375]
  PIN a[376]
    DIRECTION INPUT ;
    USE SIGNAL ;
    PORT
      LAYER M4 ;
        RECT  64.692 72.912 64.776 72.936 ;
    END
  END a[376]
  PIN a[377]
    DIRECTION INPUT ;
    USE SIGNAL ;
    PORT
      LAYER M4 ;
        RECT  64.692 73.008 64.776 73.032 ;
    END
  END a[377]
  PIN a[378]
    DIRECTION INPUT ;
    USE SIGNAL ;
    PORT
      LAYER M4 ;
        RECT  64.692 73.104 64.776 73.128 ;
    END
  END a[378]
  PIN a[379]
    DIRECTION INPUT ;
    USE SIGNAL ;
    PORT
      LAYER M4 ;
        RECT  64.692 73.2 64.776 73.224 ;
    END
  END a[379]
  PIN a[37]
    DIRECTION INPUT ;
    USE SIGNAL ;
    PORT
      LAYER M4 ;
        RECT  64.692 54.96 64.776 54.984 ;
    END
  END a[37]
  PIN a[380]
    DIRECTION INPUT ;
    USE SIGNAL ;
    PORT
      LAYER M4 ;
        RECT  64.692 73.296 64.776 73.32 ;
    END
  END a[380]
  PIN a[381]
    DIRECTION INPUT ;
    USE SIGNAL ;
    PORT
      LAYER M4 ;
        RECT  64.692 73.392 64.776 73.416 ;
    END
  END a[381]
  PIN a[382]
    DIRECTION INPUT ;
    USE SIGNAL ;
    PORT
      LAYER M4 ;
        RECT  64.692 73.488 64.776 73.512 ;
    END
  END a[382]
  PIN a[383]
    DIRECTION INPUT ;
    USE SIGNAL ;
    PORT
      LAYER M4 ;
        RECT  64.692 73.584 64.776 73.608 ;
    END
  END a[383]
  PIN a[384]
    DIRECTION INPUT ;
    USE SIGNAL ;
    PORT
      LAYER M4 ;
        RECT  64.692 19.92 64.776 19.944 ;
    END
  END a[384]
  PIN a[385]
    DIRECTION INPUT ;
    USE SIGNAL ;
    PORT
      LAYER M4 ;
        RECT  64.692 20.016 64.776 20.04 ;
    END
  END a[385]
  PIN a[386]
    DIRECTION INPUT ;
    USE SIGNAL ;
    PORT
      LAYER M4 ;
        RECT  64.692 20.112 64.776 20.136 ;
    END
  END a[386]
  PIN a[387]
    DIRECTION INPUT ;
    USE SIGNAL ;
    PORT
      LAYER M4 ;
        RECT  64.692 20.208 64.776 20.232 ;
    END
  END a[387]
  PIN a[388]
    DIRECTION INPUT ;
    USE SIGNAL ;
    PORT
      LAYER M4 ;
        RECT  64.692 20.304 64.776 20.328 ;
    END
  END a[388]
  PIN a[389]
    DIRECTION INPUT ;
    USE SIGNAL ;
    PORT
      LAYER M4 ;
        RECT  64.692 20.4 64.776 20.424 ;
    END
  END a[389]
  PIN a[38]
    DIRECTION INPUT ;
    USE SIGNAL ;
    PORT
      LAYER M4 ;
        RECT  64.692 55.056 64.776 55.08 ;
    END
  END a[38]
  PIN a[390]
    DIRECTION INPUT ;
    USE SIGNAL ;
    PORT
      LAYER M4 ;
        RECT  64.692 20.496 64.776 20.52 ;
    END
  END a[390]
  PIN a[391]
    DIRECTION INPUT ;
    USE SIGNAL ;
    PORT
      LAYER M4 ;
        RECT  64.692 20.592 64.776 20.616 ;
    END
  END a[391]
  PIN a[392]
    DIRECTION INPUT ;
    USE SIGNAL ;
    PORT
      LAYER M4 ;
        RECT  64.692 20.688 64.776 20.712 ;
    END
  END a[392]
  PIN a[393]
    DIRECTION INPUT ;
    USE SIGNAL ;
    PORT
      LAYER M4 ;
        RECT  64.692 20.784 64.776 20.808 ;
    END
  END a[393]
  PIN a[394]
    DIRECTION INPUT ;
    USE SIGNAL ;
    PORT
      LAYER M4 ;
        RECT  64.692 20.88 64.776 20.904 ;
    END
  END a[394]
  PIN a[395]
    DIRECTION INPUT ;
    USE SIGNAL ;
    PORT
      LAYER M4 ;
        RECT  64.692 20.976 64.776 21 ;
    END
  END a[395]
  PIN a[396]
    DIRECTION INPUT ;
    USE SIGNAL ;
    PORT
      LAYER M4 ;
        RECT  64.692 21.072 64.776 21.096 ;
    END
  END a[396]
  PIN a[397]
    DIRECTION INPUT ;
    USE SIGNAL ;
    PORT
      LAYER M4 ;
        RECT  64.692 21.168 64.776 21.192 ;
    END
  END a[397]
  PIN a[398]
    DIRECTION INPUT ;
    USE SIGNAL ;
    PORT
      LAYER M4 ;
        RECT  64.692 21.264 64.776 21.288 ;
    END
  END a[398]
  PIN a[399]
    DIRECTION INPUT ;
    USE SIGNAL ;
    PORT
      LAYER M4 ;
        RECT  64.692 21.36 64.776 21.384 ;
    END
  END a[399]
  PIN a[39]
    DIRECTION INPUT ;
    USE SIGNAL ;
    PORT
      LAYER M4 ;
        RECT  64.692 55.152 64.776 55.176 ;
    END
  END a[39]
  PIN a[3]
    DIRECTION INPUT ;
    USE SIGNAL ;
    PORT
      LAYER M4 ;
        RECT  64.692 42.48 64.776 42.504 ;
    END
  END a[3]
  PIN a[400]
    DIRECTION INPUT ;
    USE SIGNAL ;
    PORT
      LAYER M4 ;
        RECT  64.692 21.456 64.776 21.48 ;
    END
  END a[400]
  PIN a[401]
    DIRECTION INPUT ;
    USE SIGNAL ;
    PORT
      LAYER M4 ;
        RECT  64.692 21.552 64.776 21.576 ;
    END
  END a[401]
  PIN a[402]
    DIRECTION INPUT ;
    USE SIGNAL ;
    PORT
      LAYER M4 ;
        RECT  64.692 21.648 64.776 21.672 ;
    END
  END a[402]
  PIN a[403]
    DIRECTION INPUT ;
    USE SIGNAL ;
    PORT
      LAYER M4 ;
        RECT  64.692 21.744 64.776 21.768 ;
    END
  END a[403]
  PIN a[404]
    DIRECTION INPUT ;
    USE SIGNAL ;
    PORT
      LAYER M4 ;
        RECT  64.692 21.84 64.776 21.864 ;
    END
  END a[404]
  PIN a[405]
    DIRECTION INPUT ;
    USE SIGNAL ;
    PORT
      LAYER M4 ;
        RECT  64.692 21.936 64.776 21.96 ;
    END
  END a[405]
  PIN a[406]
    DIRECTION INPUT ;
    USE SIGNAL ;
    PORT
      LAYER M4 ;
        RECT  64.692 22.032 64.776 22.056 ;
    END
  END a[406]
  PIN a[407]
    DIRECTION INPUT ;
    USE SIGNAL ;
    PORT
      LAYER M4 ;
        RECT  64.692 22.128 64.776 22.152 ;
    END
  END a[407]
  PIN a[408]
    DIRECTION INPUT ;
    USE SIGNAL ;
    PORT
      LAYER M4 ;
        RECT  64.692 22.224 64.776 22.248 ;
    END
  END a[408]
  PIN a[409]
    DIRECTION INPUT ;
    USE SIGNAL ;
    PORT
      LAYER M4 ;
        RECT  64.692 22.32 64.776 22.344 ;
    END
  END a[409]
  PIN a[40]
    DIRECTION INPUT ;
    USE SIGNAL ;
    PORT
      LAYER M4 ;
        RECT  64.692 55.248 64.776 55.272 ;
    END
  END a[40]
  PIN a[410]
    DIRECTION INPUT ;
    USE SIGNAL ;
    PORT
      LAYER M4 ;
        RECT  64.692 22.416 64.776 22.44 ;
    END
  END a[410]
  PIN a[411]
    DIRECTION INPUT ;
    USE SIGNAL ;
    PORT
      LAYER M4 ;
        RECT  64.692 22.512 64.776 22.536 ;
    END
  END a[411]
  PIN a[412]
    DIRECTION INPUT ;
    USE SIGNAL ;
    PORT
      LAYER M4 ;
        RECT  64.692 22.608 64.776 22.632 ;
    END
  END a[412]
  PIN a[413]
    DIRECTION INPUT ;
    USE SIGNAL ;
    PORT
      LAYER M4 ;
        RECT  64.692 22.704 64.776 22.728 ;
    END
  END a[413]
  PIN a[414]
    DIRECTION INPUT ;
    USE SIGNAL ;
    PORT
      LAYER M4 ;
        RECT  64.692 22.8 64.776 22.824 ;
    END
  END a[414]
  PIN a[415]
    DIRECTION INPUT ;
    USE SIGNAL ;
    PORT
      LAYER M4 ;
        RECT  64.692 22.896 64.776 22.92 ;
    END
  END a[415]
  PIN a[416]
    DIRECTION INPUT ;
    USE SIGNAL ;
    PORT
      LAYER M4 ;
        RECT  64.692 22.992 64.776 23.016 ;
    END
  END a[416]
  PIN a[417]
    DIRECTION INPUT ;
    USE SIGNAL ;
    PORT
      LAYER M4 ;
        RECT  64.692 23.088 64.776 23.112 ;
    END
  END a[417]
  PIN a[418]
    DIRECTION INPUT ;
    USE SIGNAL ;
    PORT
      LAYER M4 ;
        RECT  64.692 23.184 64.776 23.208 ;
    END
  END a[418]
  PIN a[419]
    DIRECTION INPUT ;
    USE SIGNAL ;
    PORT
      LAYER M4 ;
        RECT  64.692 23.28 64.776 23.304 ;
    END
  END a[419]
  PIN a[41]
    DIRECTION INPUT ;
    USE SIGNAL ;
    PORT
      LAYER M4 ;
        RECT  64.692 55.344 64.776 55.368 ;
    END
  END a[41]
  PIN a[420]
    DIRECTION INPUT ;
    USE SIGNAL ;
    PORT
      LAYER M4 ;
        RECT  64.692 23.376 64.776 23.4 ;
    END
  END a[420]
  PIN a[421]
    DIRECTION INPUT ;
    USE SIGNAL ;
    PORT
      LAYER M4 ;
        RECT  64.692 23.472 64.776 23.496 ;
    END
  END a[421]
  PIN a[422]
    DIRECTION INPUT ;
    USE SIGNAL ;
    PORT
      LAYER M4 ;
        RECT  64.692 23.568 64.776 23.592 ;
    END
  END a[422]
  PIN a[423]
    DIRECTION INPUT ;
    USE SIGNAL ;
    PORT
      LAYER M4 ;
        RECT  64.692 23.664 64.776 23.688 ;
    END
  END a[423]
  PIN a[424]
    DIRECTION INPUT ;
    USE SIGNAL ;
    PORT
      LAYER M4 ;
        RECT  64.692 23.76 64.776 23.784 ;
    END
  END a[424]
  PIN a[425]
    DIRECTION INPUT ;
    USE SIGNAL ;
    PORT
      LAYER M4 ;
        RECT  64.692 23.856 64.776 23.88 ;
    END
  END a[425]
  PIN a[426]
    DIRECTION INPUT ;
    USE SIGNAL ;
    PORT
      LAYER M4 ;
        RECT  64.692 23.952 64.776 23.976 ;
    END
  END a[426]
  PIN a[427]
    DIRECTION INPUT ;
    USE SIGNAL ;
    PORT
      LAYER M4 ;
        RECT  64.692 24.048 64.776 24.072 ;
    END
  END a[427]
  PIN a[428]
    DIRECTION INPUT ;
    USE SIGNAL ;
    PORT
      LAYER M4 ;
        RECT  64.692 24.144 64.776 24.168 ;
    END
  END a[428]
  PIN a[429]
    DIRECTION INPUT ;
    USE SIGNAL ;
    PORT
      LAYER M4 ;
        RECT  64.692 24.24 64.776 24.264 ;
    END
  END a[429]
  PIN a[42]
    DIRECTION INPUT ;
    USE SIGNAL ;
    PORT
      LAYER M4 ;
        RECT  64.692 55.44 64.776 55.464 ;
    END
  END a[42]
  PIN a[430]
    DIRECTION INPUT ;
    USE SIGNAL ;
    PORT
      LAYER M4 ;
        RECT  64.692 24.336 64.776 24.36 ;
    END
  END a[430]
  PIN a[431]
    DIRECTION INPUT ;
    USE SIGNAL ;
    PORT
      LAYER M4 ;
        RECT  64.692 24.432 64.776 24.456 ;
    END
  END a[431]
  PIN a[432]
    DIRECTION INPUT ;
    USE SIGNAL ;
    PORT
      LAYER M4 ;
        RECT  64.692 24.528 64.776 24.552 ;
    END
  END a[432]
  PIN a[433]
    DIRECTION INPUT ;
    USE SIGNAL ;
    PORT
      LAYER M4 ;
        RECT  64.692 24.624 64.776 24.648 ;
    END
  END a[433]
  PIN a[434]
    DIRECTION INPUT ;
    USE SIGNAL ;
    PORT
      LAYER M4 ;
        RECT  64.692 24.72 64.776 24.744 ;
    END
  END a[434]
  PIN a[435]
    DIRECTION INPUT ;
    USE SIGNAL ;
    PORT
      LAYER M4 ;
        RECT  64.692 24.816 64.776 24.84 ;
    END
  END a[435]
  PIN a[436]
    DIRECTION INPUT ;
    USE SIGNAL ;
    PORT
      LAYER M4 ;
        RECT  64.692 24.912 64.776 24.936 ;
    END
  END a[436]
  PIN a[437]
    DIRECTION INPUT ;
    USE SIGNAL ;
    PORT
      LAYER M4 ;
        RECT  64.692 25.008 64.776 25.032 ;
    END
  END a[437]
  PIN a[438]
    DIRECTION INPUT ;
    USE SIGNAL ;
    PORT
      LAYER M4 ;
        RECT  64.692 25.104 64.776 25.128 ;
    END
  END a[438]
  PIN a[439]
    DIRECTION INPUT ;
    USE SIGNAL ;
    PORT
      LAYER M4 ;
        RECT  64.692 25.2 64.776 25.224 ;
    END
  END a[439]
  PIN a[43]
    DIRECTION INPUT ;
    USE SIGNAL ;
    PORT
      LAYER M4 ;
        RECT  64.692 55.536 64.776 55.56 ;
    END
  END a[43]
  PIN a[440]
    DIRECTION INPUT ;
    USE SIGNAL ;
    PORT
      LAYER M4 ;
        RECT  64.692 25.296 64.776 25.32 ;
    END
  END a[440]
  PIN a[441]
    DIRECTION INPUT ;
    USE SIGNAL ;
    PORT
      LAYER M4 ;
        RECT  64.692 25.392 64.776 25.416 ;
    END
  END a[441]
  PIN a[442]
    DIRECTION INPUT ;
    USE SIGNAL ;
    PORT
      LAYER M4 ;
        RECT  64.692 25.488 64.776 25.512 ;
    END
  END a[442]
  PIN a[443]
    DIRECTION INPUT ;
    USE SIGNAL ;
    PORT
      LAYER M4 ;
        RECT  64.692 25.584 64.776 25.608 ;
    END
  END a[443]
  PIN a[444]
    DIRECTION INPUT ;
    USE SIGNAL ;
    PORT
      LAYER M4 ;
        RECT  64.692 25.68 64.776 25.704 ;
    END
  END a[444]
  PIN a[445]
    DIRECTION INPUT ;
    USE SIGNAL ;
    PORT
      LAYER M4 ;
        RECT  64.692 25.776 64.776 25.8 ;
    END
  END a[445]
  PIN a[446]
    DIRECTION INPUT ;
    USE SIGNAL ;
    PORT
      LAYER M4 ;
        RECT  64.692 25.872 64.776 25.896 ;
    END
  END a[446]
  PIN a[447]
    DIRECTION INPUT ;
    USE SIGNAL ;
    PORT
      LAYER M4 ;
        RECT  64.692 25.968 64.776 25.992 ;
    END
  END a[447]
  PIN a[448]
    DIRECTION INPUT ;
    USE SIGNAL ;
    PORT
      LAYER M4 ;
        RECT  64.692 32.208 64.776 32.232 ;
    END
  END a[448]
  PIN a[449]
    DIRECTION INPUT ;
    USE SIGNAL ;
    PORT
      LAYER M4 ;
        RECT  64.692 32.304 64.776 32.328 ;
    END
  END a[449]
  PIN a[44]
    DIRECTION INPUT ;
    USE SIGNAL ;
    PORT
      LAYER M4 ;
        RECT  64.692 55.632 64.776 55.656 ;
    END
  END a[44]
  PIN a[450]
    DIRECTION INPUT ;
    USE SIGNAL ;
    PORT
      LAYER M4 ;
        RECT  64.692 32.4 64.776 32.424 ;
    END
  END a[450]
  PIN a[451]
    DIRECTION INPUT ;
    USE SIGNAL ;
    PORT
      LAYER M4 ;
        RECT  64.692 32.496 64.776 32.52 ;
    END
  END a[451]
  PIN a[452]
    DIRECTION INPUT ;
    USE SIGNAL ;
    PORT
      LAYER M4 ;
        RECT  64.692 32.592 64.776 32.616 ;
    END
  END a[452]
  PIN a[453]
    DIRECTION INPUT ;
    USE SIGNAL ;
    PORT
      LAYER M4 ;
        RECT  64.692 32.688 64.776 32.712 ;
    END
  END a[453]
  PIN a[454]
    DIRECTION INPUT ;
    USE SIGNAL ;
    PORT
      LAYER M4 ;
        RECT  64.692 32.784 64.776 32.808 ;
    END
  END a[454]
  PIN a[455]
    DIRECTION INPUT ;
    USE SIGNAL ;
    PORT
      LAYER M4 ;
        RECT  64.692 32.88 64.776 32.904 ;
    END
  END a[455]
  PIN a[456]
    DIRECTION INPUT ;
    USE SIGNAL ;
    PORT
      LAYER M4 ;
        RECT  64.692 32.976 64.776 33 ;
    END
  END a[456]
  PIN a[457]
    DIRECTION INPUT ;
    USE SIGNAL ;
    PORT
      LAYER M4 ;
        RECT  64.692 33.072 64.776 33.096 ;
    END
  END a[457]
  PIN a[458]
    DIRECTION INPUT ;
    USE SIGNAL ;
    PORT
      LAYER M4 ;
        RECT  64.692 33.168 64.776 33.192 ;
    END
  END a[458]
  PIN a[459]
    DIRECTION INPUT ;
    USE SIGNAL ;
    PORT
      LAYER M4 ;
        RECT  64.692 33.264 64.776 33.288 ;
    END
  END a[459]
  PIN a[45]
    DIRECTION INPUT ;
    USE SIGNAL ;
    PORT
      LAYER M4 ;
        RECT  64.692 55.728 64.776 55.752 ;
    END
  END a[45]
  PIN a[460]
    DIRECTION INPUT ;
    USE SIGNAL ;
    PORT
      LAYER M4 ;
        RECT  64.692 33.36 64.776 33.384 ;
    END
  END a[460]
  PIN a[461]
    DIRECTION INPUT ;
    USE SIGNAL ;
    PORT
      LAYER M4 ;
        RECT  64.692 33.456 64.776 33.48 ;
    END
  END a[461]
  PIN a[462]
    DIRECTION INPUT ;
    USE SIGNAL ;
    PORT
      LAYER M4 ;
        RECT  64.692 33.552 64.776 33.576 ;
    END
  END a[462]
  PIN a[463]
    DIRECTION INPUT ;
    USE SIGNAL ;
    PORT
      LAYER M4 ;
        RECT  64.692 33.648 64.776 33.672 ;
    END
  END a[463]
  PIN a[464]
    DIRECTION INPUT ;
    USE SIGNAL ;
    PORT
      LAYER M4 ;
        RECT  64.692 33.744 64.776 33.768 ;
    END
  END a[464]
  PIN a[465]
    DIRECTION INPUT ;
    USE SIGNAL ;
    PORT
      LAYER M4 ;
        RECT  64.692 33.84 64.776 33.864 ;
    END
  END a[465]
  PIN a[466]
    DIRECTION INPUT ;
    USE SIGNAL ;
    PORT
      LAYER M4 ;
        RECT  64.692 33.936 64.776 33.96 ;
    END
  END a[466]
  PIN a[467]
    DIRECTION INPUT ;
    USE SIGNAL ;
    PORT
      LAYER M4 ;
        RECT  64.692 34.032 64.776 34.056 ;
    END
  END a[467]
  PIN a[468]
    DIRECTION INPUT ;
    USE SIGNAL ;
    PORT
      LAYER M4 ;
        RECT  64.692 34.128 64.776 34.152 ;
    END
  END a[468]
  PIN a[469]
    DIRECTION INPUT ;
    USE SIGNAL ;
    PORT
      LAYER M4 ;
        RECT  64.692 34.224 64.776 34.248 ;
    END
  END a[469]
  PIN a[46]
    DIRECTION INPUT ;
    USE SIGNAL ;
    PORT
      LAYER M4 ;
        RECT  64.692 55.824 64.776 55.848 ;
    END
  END a[46]
  PIN a[470]
    DIRECTION INPUT ;
    USE SIGNAL ;
    PORT
      LAYER M4 ;
        RECT  64.692 34.32 64.776 34.344 ;
    END
  END a[470]
  PIN a[471]
    DIRECTION INPUT ;
    USE SIGNAL ;
    PORT
      LAYER M4 ;
        RECT  64.692 34.416 64.776 34.44 ;
    END
  END a[471]
  PIN a[472]
    DIRECTION INPUT ;
    USE SIGNAL ;
    PORT
      LAYER M4 ;
        RECT  64.692 34.512 64.776 34.536 ;
    END
  END a[472]
  PIN a[473]
    DIRECTION INPUT ;
    USE SIGNAL ;
    PORT
      LAYER M4 ;
        RECT  64.692 34.608 64.776 34.632 ;
    END
  END a[473]
  PIN a[474]
    DIRECTION INPUT ;
    USE SIGNAL ;
    PORT
      LAYER M4 ;
        RECT  64.692 34.704 64.776 34.728 ;
    END
  END a[474]
  PIN a[475]
    DIRECTION INPUT ;
    USE SIGNAL ;
    PORT
      LAYER M4 ;
        RECT  64.692 34.8 64.776 34.824 ;
    END
  END a[475]
  PIN a[476]
    DIRECTION INPUT ;
    USE SIGNAL ;
    PORT
      LAYER M4 ;
        RECT  64.692 34.896 64.776 34.92 ;
    END
  END a[476]
  PIN a[477]
    DIRECTION INPUT ;
    USE SIGNAL ;
    PORT
      LAYER M4 ;
        RECT  64.692 34.992 64.776 35.016 ;
    END
  END a[477]
  PIN a[478]
    DIRECTION INPUT ;
    USE SIGNAL ;
    PORT
      LAYER M4 ;
        RECT  64.692 35.088 64.776 35.112 ;
    END
  END a[478]
  PIN a[479]
    DIRECTION INPUT ;
    USE SIGNAL ;
    PORT
      LAYER M4 ;
        RECT  64.692 35.184 64.776 35.208 ;
    END
  END a[479]
  PIN a[47]
    DIRECTION INPUT ;
    USE SIGNAL ;
    PORT
      LAYER M4 ;
        RECT  64.692 55.92 64.776 55.944 ;
    END
  END a[47]
  PIN a[480]
    DIRECTION INPUT ;
    USE SIGNAL ;
    PORT
      LAYER M4 ;
        RECT  64.692 35.28 64.776 35.304 ;
    END
  END a[480]
  PIN a[481]
    DIRECTION INPUT ;
    USE SIGNAL ;
    PORT
      LAYER M4 ;
        RECT  64.692 35.376 64.776 35.4 ;
    END
  END a[481]
  PIN a[482]
    DIRECTION INPUT ;
    USE SIGNAL ;
    PORT
      LAYER M4 ;
        RECT  64.692 35.472 64.776 35.496 ;
    END
  END a[482]
  PIN a[483]
    DIRECTION INPUT ;
    USE SIGNAL ;
    PORT
      LAYER M4 ;
        RECT  64.692 35.568 64.776 35.592 ;
    END
  END a[483]
  PIN a[484]
    DIRECTION INPUT ;
    USE SIGNAL ;
    PORT
      LAYER M4 ;
        RECT  64.692 35.664 64.776 35.688 ;
    END
  END a[484]
  PIN a[485]
    DIRECTION INPUT ;
    USE SIGNAL ;
    PORT
      LAYER M4 ;
        RECT  64.692 35.76 64.776 35.784 ;
    END
  END a[485]
  PIN a[486]
    DIRECTION INPUT ;
    USE SIGNAL ;
    PORT
      LAYER M4 ;
        RECT  64.692 35.856 64.776 35.88 ;
    END
  END a[486]
  PIN a[487]
    DIRECTION INPUT ;
    USE SIGNAL ;
    PORT
      LAYER M4 ;
        RECT  64.692 35.952 64.776 35.976 ;
    END
  END a[487]
  PIN a[488]
    DIRECTION INPUT ;
    USE SIGNAL ;
    PORT
      LAYER M4 ;
        RECT  64.692 36.048 64.776 36.072 ;
    END
  END a[488]
  PIN a[489]
    DIRECTION INPUT ;
    USE SIGNAL ;
    PORT
      LAYER M4 ;
        RECT  64.692 36.144 64.776 36.168 ;
    END
  END a[489]
  PIN a[48]
    DIRECTION INPUT ;
    USE SIGNAL ;
    PORT
      LAYER M4 ;
        RECT  64.692 56.016 64.776 56.04 ;
    END
  END a[48]
  PIN a[490]
    DIRECTION INPUT ;
    USE SIGNAL ;
    PORT
      LAYER M4 ;
        RECT  64.692 36.24 64.776 36.264 ;
    END
  END a[490]
  PIN a[491]
    DIRECTION INPUT ;
    USE SIGNAL ;
    PORT
      LAYER M4 ;
        RECT  64.692 36.336 64.776 36.36 ;
    END
  END a[491]
  PIN a[492]
    DIRECTION INPUT ;
    USE SIGNAL ;
    PORT
      LAYER M4 ;
        RECT  64.692 36.432 64.776 36.456 ;
    END
  END a[492]
  PIN a[493]
    DIRECTION INPUT ;
    USE SIGNAL ;
    PORT
      LAYER M4 ;
        RECT  64.692 36.528 64.776 36.552 ;
    END
  END a[493]
  PIN a[494]
    DIRECTION INPUT ;
    USE SIGNAL ;
    PORT
      LAYER M4 ;
        RECT  64.692 36.624 64.776 36.648 ;
    END
  END a[494]
  PIN a[495]
    DIRECTION INPUT ;
    USE SIGNAL ;
    PORT
      LAYER M4 ;
        RECT  64.692 36.72 64.776 36.744 ;
    END
  END a[495]
  PIN a[496]
    DIRECTION INPUT ;
    USE SIGNAL ;
    PORT
      LAYER M4 ;
        RECT  64.692 36.816 64.776 36.84 ;
    END
  END a[496]
  PIN a[497]
    DIRECTION INPUT ;
    USE SIGNAL ;
    PORT
      LAYER M4 ;
        RECT  64.692 36.912 64.776 36.936 ;
    END
  END a[497]
  PIN a[498]
    DIRECTION INPUT ;
    USE SIGNAL ;
    PORT
      LAYER M4 ;
        RECT  64.692 37.008 64.776 37.032 ;
    END
  END a[498]
  PIN a[499]
    DIRECTION INPUT ;
    USE SIGNAL ;
    PORT
      LAYER M4 ;
        RECT  64.692 37.104 64.776 37.128 ;
    END
  END a[499]
  PIN a[49]
    DIRECTION INPUT ;
    USE SIGNAL ;
    PORT
      LAYER M4 ;
        RECT  64.692 56.112 64.776 56.136 ;
    END
  END a[49]
  PIN a[4]
    DIRECTION INPUT ;
    USE SIGNAL ;
    PORT
      LAYER M4 ;
        RECT  64.692 42.576 64.776 42.6 ;
    END
  END a[4]
  PIN a[500]
    DIRECTION INPUT ;
    USE SIGNAL ;
    PORT
      LAYER M4 ;
        RECT  64.692 37.2 64.776 37.224 ;
    END
  END a[500]
  PIN a[501]
    DIRECTION INPUT ;
    USE SIGNAL ;
    PORT
      LAYER M4 ;
        RECT  64.692 37.296 64.776 37.32 ;
    END
  END a[501]
  PIN a[502]
    DIRECTION INPUT ;
    USE SIGNAL ;
    PORT
      LAYER M4 ;
        RECT  64.692 37.392 64.776 37.416 ;
    END
  END a[502]
  PIN a[503]
    DIRECTION INPUT ;
    USE SIGNAL ;
    PORT
      LAYER M4 ;
        RECT  64.692 37.488 64.776 37.512 ;
    END
  END a[503]
  PIN a[504]
    DIRECTION INPUT ;
    USE SIGNAL ;
    PORT
      LAYER M4 ;
        RECT  64.692 37.584 64.776 37.608 ;
    END
  END a[504]
  PIN a[505]
    DIRECTION INPUT ;
    USE SIGNAL ;
    PORT
      LAYER M4 ;
        RECT  64.692 37.68 64.776 37.704 ;
    END
  END a[505]
  PIN a[506]
    DIRECTION INPUT ;
    USE SIGNAL ;
    PORT
      LAYER M4 ;
        RECT  64.692 37.776 64.776 37.8 ;
    END
  END a[506]
  PIN a[507]
    DIRECTION INPUT ;
    USE SIGNAL ;
    PORT
      LAYER M4 ;
        RECT  64.692 37.872 64.776 37.896 ;
    END
  END a[507]
  PIN a[508]
    DIRECTION INPUT ;
    USE SIGNAL ;
    PORT
      LAYER M4 ;
        RECT  64.692 37.968 64.776 37.992 ;
    END
  END a[508]
  PIN a[509]
    DIRECTION INPUT ;
    USE SIGNAL ;
    PORT
      LAYER M4 ;
        RECT  64.692 38.064 64.776 38.088 ;
    END
  END a[509]
  PIN a[50]
    DIRECTION INPUT ;
    USE SIGNAL ;
    PORT
      LAYER M4 ;
        RECT  64.692 56.208 64.776 56.232 ;
    END
  END a[50]
  PIN a[510]
    DIRECTION INPUT ;
    USE SIGNAL ;
    PORT
      LAYER M4 ;
        RECT  64.692 38.16 64.776 38.184 ;
    END
  END a[510]
  PIN a[511]
    DIRECTION INPUT ;
    USE SIGNAL ;
    PORT
      LAYER M4 ;
        RECT  64.692 38.256 64.776 38.28 ;
    END
  END a[511]
  PIN a[512]
    DIRECTION INPUT ;
    USE SIGNAL ;
    PORT
      LAYER M4 ;
        RECT  64.692 29.136 64.776 29.16 ;
    END
  END a[512]
  PIN a[513]
    DIRECTION INPUT ;
    USE SIGNAL ;
    PORT
      LAYER M4 ;
        RECT  64.692 29.232 64.776 29.256 ;
    END
  END a[513]
  PIN a[514]
    DIRECTION INPUT ;
    USE SIGNAL ;
    PORT
      LAYER M4 ;
        RECT  64.692 29.328 64.776 29.352 ;
    END
  END a[514]
  PIN a[515]
    DIRECTION INPUT ;
    USE SIGNAL ;
    PORT
      LAYER M4 ;
        RECT  64.692 29.424 64.776 29.448 ;
    END
  END a[515]
  PIN a[516]
    DIRECTION INPUT ;
    USE SIGNAL ;
    PORT
      LAYER M4 ;
        RECT  64.692 29.52 64.776 29.544 ;
    END
  END a[516]
  PIN a[517]
    DIRECTION INPUT ;
    USE SIGNAL ;
    PORT
      LAYER M4 ;
        RECT  64.692 29.616 64.776 29.64 ;
    END
  END a[517]
  PIN a[518]
    DIRECTION INPUT ;
    USE SIGNAL ;
    PORT
      LAYER M4 ;
        RECT  64.692 29.712 64.776 29.736 ;
    END
  END a[518]
  PIN a[519]
    DIRECTION INPUT ;
    USE SIGNAL ;
    PORT
      LAYER M4 ;
        RECT  64.692 29.808 64.776 29.832 ;
    END
  END a[519]
  PIN a[51]
    DIRECTION INPUT ;
    USE SIGNAL ;
    PORT
      LAYER M4 ;
        RECT  64.692 56.304 64.776 56.328 ;
    END
  END a[51]
  PIN a[520]
    DIRECTION INPUT ;
    USE SIGNAL ;
    PORT
      LAYER M4 ;
        RECT  64.692 29.904 64.776 29.928 ;
    END
  END a[520]
  PIN a[521]
    DIRECTION INPUT ;
    USE SIGNAL ;
    PORT
      LAYER M4 ;
        RECT  64.692 30 64.776 30.024 ;
    END
  END a[521]
  PIN a[522]
    DIRECTION INPUT ;
    USE SIGNAL ;
    PORT
      LAYER M4 ;
        RECT  64.692 30.096 64.776 30.12 ;
    END
  END a[522]
  PIN a[523]
    DIRECTION INPUT ;
    USE SIGNAL ;
    PORT
      LAYER M4 ;
        RECT  64.692 30.192 64.776 30.216 ;
    END
  END a[523]
  PIN a[524]
    DIRECTION INPUT ;
    USE SIGNAL ;
    PORT
      LAYER M4 ;
        RECT  64.692 30.288 64.776 30.312 ;
    END
  END a[524]
  PIN a[525]
    DIRECTION INPUT ;
    USE SIGNAL ;
    PORT
      LAYER M4 ;
        RECT  64.692 30.384 64.776 30.408 ;
    END
  END a[525]
  PIN a[526]
    DIRECTION INPUT ;
    USE SIGNAL ;
    PORT
      LAYER M4 ;
        RECT  64.692 30.48 64.776 30.504 ;
    END
  END a[526]
  PIN a[527]
    DIRECTION INPUT ;
    USE SIGNAL ;
    PORT
      LAYER M4 ;
        RECT  64.692 30.576 64.776 30.6 ;
    END
  END a[527]
  PIN a[528]
    DIRECTION INPUT ;
    USE SIGNAL ;
    PORT
      LAYER M4 ;
        RECT  64.692 30.672 64.776 30.696 ;
    END
  END a[528]
  PIN a[529]
    DIRECTION INPUT ;
    USE SIGNAL ;
    PORT
      LAYER M4 ;
        RECT  64.692 30.768 64.776 30.792 ;
    END
  END a[529]
  PIN a[52]
    DIRECTION INPUT ;
    USE SIGNAL ;
    PORT
      LAYER M4 ;
        RECT  64.692 56.4 64.776 56.424 ;
    END
  END a[52]
  PIN a[530]
    DIRECTION INPUT ;
    USE SIGNAL ;
    PORT
      LAYER M4 ;
        RECT  64.692 30.864 64.776 30.888 ;
    END
  END a[530]
  PIN a[531]
    DIRECTION INPUT ;
    USE SIGNAL ;
    PORT
      LAYER M4 ;
        RECT  64.692 30.96 64.776 30.984 ;
    END
  END a[531]
  PIN a[532]
    DIRECTION INPUT ;
    USE SIGNAL ;
    PORT
      LAYER M4 ;
        RECT  64.692 31.056 64.776 31.08 ;
    END
  END a[532]
  PIN a[533]
    DIRECTION INPUT ;
    USE SIGNAL ;
    PORT
      LAYER M4 ;
        RECT  64.692 31.152 64.776 31.176 ;
    END
  END a[533]
  PIN a[534]
    DIRECTION INPUT ;
    USE SIGNAL ;
    PORT
      LAYER M4 ;
        RECT  64.692 31.248 64.776 31.272 ;
    END
  END a[534]
  PIN a[535]
    DIRECTION INPUT ;
    USE SIGNAL ;
    PORT
      LAYER M4 ;
        RECT  64.692 31.344 64.776 31.368 ;
    END
  END a[535]
  PIN a[536]
    DIRECTION INPUT ;
    USE SIGNAL ;
    PORT
      LAYER M4 ;
        RECT  64.692 31.44 64.776 31.464 ;
    END
  END a[536]
  PIN a[537]
    DIRECTION INPUT ;
    USE SIGNAL ;
    PORT
      LAYER M4 ;
        RECT  64.692 31.536 64.776 31.56 ;
    END
  END a[537]
  PIN a[538]
    DIRECTION INPUT ;
    USE SIGNAL ;
    PORT
      LAYER M4 ;
        RECT  64.692 31.632 64.776 31.656 ;
    END
  END a[538]
  PIN a[539]
    DIRECTION INPUT ;
    USE SIGNAL ;
    PORT
      LAYER M4 ;
        RECT  64.692 31.728 64.776 31.752 ;
    END
  END a[539]
  PIN a[53]
    DIRECTION INPUT ;
    USE SIGNAL ;
    PORT
      LAYER M4 ;
        RECT  64.692 56.496 64.776 56.52 ;
    END
  END a[53]
  PIN a[540]
    DIRECTION INPUT ;
    USE SIGNAL ;
    PORT
      LAYER M4 ;
        RECT  64.692 31.824 64.776 31.848 ;
    END
  END a[540]
  PIN a[541]
    DIRECTION INPUT ;
    USE SIGNAL ;
    PORT
      LAYER M4 ;
        RECT  64.692 31.92 64.776 31.944 ;
    END
  END a[541]
  PIN a[542]
    DIRECTION INPUT ;
    USE SIGNAL ;
    PORT
      LAYER M4 ;
        RECT  64.692 32.016 64.776 32.04 ;
    END
  END a[542]
  PIN a[543]
    DIRECTION INPUT ;
    USE SIGNAL ;
    PORT
      LAYER M4 ;
        RECT  64.692 32.112 64.776 32.136 ;
    END
  END a[543]
  PIN a[544]
    DIRECTION INPUT ;
    USE SIGNAL ;
    PORT
      LAYER M4 ;
        RECT  64.692 26.064 64.776 26.088 ;
    END
  END a[544]
  PIN a[545]
    DIRECTION INPUT ;
    USE SIGNAL ;
    PORT
      LAYER M4 ;
        RECT  64.692 26.16 64.776 26.184 ;
    END
  END a[545]
  PIN a[546]
    DIRECTION INPUT ;
    USE SIGNAL ;
    PORT
      LAYER M4 ;
        RECT  64.692 26.256 64.776 26.28 ;
    END
  END a[546]
  PIN a[547]
    DIRECTION INPUT ;
    USE SIGNAL ;
    PORT
      LAYER M4 ;
        RECT  64.692 26.352 64.776 26.376 ;
    END
  END a[547]
  PIN a[548]
    DIRECTION INPUT ;
    USE SIGNAL ;
    PORT
      LAYER M4 ;
        RECT  64.692 26.448 64.776 26.472 ;
    END
  END a[548]
  PIN a[549]
    DIRECTION INPUT ;
    USE SIGNAL ;
    PORT
      LAYER M4 ;
        RECT  64.692 26.544 64.776 26.568 ;
    END
  END a[549]
  PIN a[54]
    DIRECTION INPUT ;
    USE SIGNAL ;
    PORT
      LAYER M4 ;
        RECT  64.692 56.592 64.776 56.616 ;
    END
  END a[54]
  PIN a[550]
    DIRECTION INPUT ;
    USE SIGNAL ;
    PORT
      LAYER M4 ;
        RECT  64.692 26.64 64.776 26.664 ;
    END
  END a[550]
  PIN a[551]
    DIRECTION INPUT ;
    USE SIGNAL ;
    PORT
      LAYER M4 ;
        RECT  64.692 26.736 64.776 26.76 ;
    END
  END a[551]
  PIN a[552]
    DIRECTION INPUT ;
    USE SIGNAL ;
    PORT
      LAYER M4 ;
        RECT  64.692 26.832 64.776 26.856 ;
    END
  END a[552]
  PIN a[553]
    DIRECTION INPUT ;
    USE SIGNAL ;
    PORT
      LAYER M4 ;
        RECT  64.692 26.928 64.776 26.952 ;
    END
  END a[553]
  PIN a[554]
    DIRECTION INPUT ;
    USE SIGNAL ;
    PORT
      LAYER M4 ;
        RECT  64.692 27.024 64.776 27.048 ;
    END
  END a[554]
  PIN a[555]
    DIRECTION INPUT ;
    USE SIGNAL ;
    PORT
      LAYER M4 ;
        RECT  64.692 27.12 64.776 27.144 ;
    END
  END a[555]
  PIN a[556]
    DIRECTION INPUT ;
    USE SIGNAL ;
    PORT
      LAYER M4 ;
        RECT  64.692 27.216 64.776 27.24 ;
    END
  END a[556]
  PIN a[557]
    DIRECTION INPUT ;
    USE SIGNAL ;
    PORT
      LAYER M4 ;
        RECT  64.692 27.312 64.776 27.336 ;
    END
  END a[557]
  PIN a[558]
    DIRECTION INPUT ;
    USE SIGNAL ;
    PORT
      LAYER M4 ;
        RECT  64.692 27.408 64.776 27.432 ;
    END
  END a[558]
  PIN a[559]
    DIRECTION INPUT ;
    USE SIGNAL ;
    PORT
      LAYER M4 ;
        RECT  64.692 27.504 64.776 27.528 ;
    END
  END a[559]
  PIN a[55]
    DIRECTION INPUT ;
    USE SIGNAL ;
    PORT
      LAYER M4 ;
        RECT  64.692 56.688 64.776 56.712 ;
    END
  END a[55]
  PIN a[560]
    DIRECTION INPUT ;
    USE SIGNAL ;
    PORT
      LAYER M4 ;
        RECT  64.692 27.6 64.776 27.624 ;
    END
  END a[560]
  PIN a[561]
    DIRECTION INPUT ;
    USE SIGNAL ;
    PORT
      LAYER M4 ;
        RECT  64.692 27.696 64.776 27.72 ;
    END
  END a[561]
  PIN a[562]
    DIRECTION INPUT ;
    USE SIGNAL ;
    PORT
      LAYER M4 ;
        RECT  64.692 27.792 64.776 27.816 ;
    END
  END a[562]
  PIN a[563]
    DIRECTION INPUT ;
    USE SIGNAL ;
    PORT
      LAYER M4 ;
        RECT  64.692 27.888 64.776 27.912 ;
    END
  END a[563]
  PIN a[564]
    DIRECTION INPUT ;
    USE SIGNAL ;
    PORT
      LAYER M4 ;
        RECT  64.692 27.984 64.776 28.008 ;
    END
  END a[564]
  PIN a[565]
    DIRECTION INPUT ;
    USE SIGNAL ;
    PORT
      LAYER M4 ;
        RECT  64.692 28.08 64.776 28.104 ;
    END
  END a[565]
  PIN a[566]
    DIRECTION INPUT ;
    USE SIGNAL ;
    PORT
      LAYER M4 ;
        RECT  64.692 28.176 64.776 28.2 ;
    END
  END a[566]
  PIN a[567]
    DIRECTION INPUT ;
    USE SIGNAL ;
    PORT
      LAYER M4 ;
        RECT  64.692 28.272 64.776 28.296 ;
    END
  END a[567]
  PIN a[568]
    DIRECTION INPUT ;
    USE SIGNAL ;
    PORT
      LAYER M4 ;
        RECT  64.692 28.368 64.776 28.392 ;
    END
  END a[568]
  PIN a[569]
    DIRECTION INPUT ;
    USE SIGNAL ;
    PORT
      LAYER M4 ;
        RECT  64.692 28.464 64.776 28.488 ;
    END
  END a[569]
  PIN a[56]
    DIRECTION INPUT ;
    USE SIGNAL ;
    PORT
      LAYER M4 ;
        RECT  64.692 56.784 64.776 56.808 ;
    END
  END a[56]
  PIN a[570]
    DIRECTION INPUT ;
    USE SIGNAL ;
    PORT
      LAYER M4 ;
        RECT  64.692 28.56 64.776 28.584 ;
    END
  END a[570]
  PIN a[571]
    DIRECTION INPUT ;
    USE SIGNAL ;
    PORT
      LAYER M4 ;
        RECT  64.692 28.656 64.776 28.68 ;
    END
  END a[571]
  PIN a[572]
    DIRECTION INPUT ;
    USE SIGNAL ;
    PORT
      LAYER M4 ;
        RECT  64.692 28.752 64.776 28.776 ;
    END
  END a[572]
  PIN a[573]
    DIRECTION INPUT ;
    USE SIGNAL ;
    PORT
      LAYER M4 ;
        RECT  64.692 28.848 64.776 28.872 ;
    END
  END a[573]
  PIN a[574]
    DIRECTION INPUT ;
    USE SIGNAL ;
    PORT
      LAYER M4 ;
        RECT  64.692 28.944 64.776 28.968 ;
    END
  END a[574]
  PIN a[575]
    DIRECTION INPUT ;
    USE SIGNAL ;
    PORT
      LAYER M4 ;
        RECT  64.692 29.04 64.776 29.064 ;
    END
  END a[575]
  PIN a[576]
    DIRECTION INPUT ;
    USE SIGNAL ;
    PORT
      LAYER M4 ;
        RECT  64.692 77.52 64.776 77.544 ;
    END
  END a[576]
  PIN a[577]
    DIRECTION INPUT ;
    USE SIGNAL ;
    PORT
      LAYER M4 ;
        RECT  64.692 77.616 64.776 77.64 ;
    END
  END a[577]
  PIN a[578]
    DIRECTION INPUT ;
    USE SIGNAL ;
    PORT
      LAYER M4 ;
        RECT  64.692 77.712 64.776 77.736 ;
    END
  END a[578]
  PIN a[579]
    DIRECTION INPUT ;
    USE SIGNAL ;
    PORT
      LAYER M4 ;
        RECT  64.692 77.808 64.776 77.832 ;
    END
  END a[579]
  PIN a[57]
    DIRECTION INPUT ;
    USE SIGNAL ;
    PORT
      LAYER M4 ;
        RECT  64.692 56.88 64.776 56.904 ;
    END
  END a[57]
  PIN a[580]
    DIRECTION INPUT ;
    USE SIGNAL ;
    PORT
      LAYER M4 ;
        RECT  64.692 77.904 64.776 77.928 ;
    END
  END a[580]
  PIN a[581]
    DIRECTION INPUT ;
    USE SIGNAL ;
    PORT
      LAYER M4 ;
        RECT  64.692 78 64.776 78.024 ;
    END
  END a[581]
  PIN a[582]
    DIRECTION INPUT ;
    USE SIGNAL ;
    PORT
      LAYER M4 ;
        RECT  64.692 78.096 64.776 78.12 ;
    END
  END a[582]
  PIN a[583]
    DIRECTION INPUT ;
    USE SIGNAL ;
    PORT
      LAYER M4 ;
        RECT  64.692 78.192 64.776 78.216 ;
    END
  END a[583]
  PIN a[584]
    DIRECTION INPUT ;
    USE SIGNAL ;
    PORT
      LAYER M4 ;
        RECT  64.692 78.288 64.776 78.312 ;
    END
  END a[584]
  PIN a[585]
    DIRECTION INPUT ;
    USE SIGNAL ;
    PORT
      LAYER M4 ;
        RECT  64.692 78.384 64.776 78.408 ;
    END
  END a[585]
  PIN a[586]
    DIRECTION INPUT ;
    USE SIGNAL ;
    PORT
      LAYER M4 ;
        RECT  64.692 78.48 64.776 78.504 ;
    END
  END a[586]
  PIN a[587]
    DIRECTION INPUT ;
    USE SIGNAL ;
    PORT
      LAYER M4 ;
        RECT  64.692 78.576 64.776 78.6 ;
    END
  END a[587]
  PIN a[588]
    DIRECTION INPUT ;
    USE SIGNAL ;
    PORT
      LAYER M4 ;
        RECT  64.692 78.672 64.776 78.696 ;
    END
  END a[588]
  PIN a[589]
    DIRECTION INPUT ;
    USE SIGNAL ;
    PORT
      LAYER M4 ;
        RECT  64.692 78.768 64.776 78.792 ;
    END
  END a[589]
  PIN a[58]
    DIRECTION INPUT ;
    USE SIGNAL ;
    PORT
      LAYER M4 ;
        RECT  64.692 56.976 64.776 57 ;
    END
  END a[58]
  PIN a[590]
    DIRECTION INPUT ;
    USE SIGNAL ;
    PORT
      LAYER M4 ;
        RECT  64.692 78.864 64.776 78.888 ;
    END
  END a[590]
  PIN a[591]
    DIRECTION INPUT ;
    USE SIGNAL ;
    PORT
      LAYER M4 ;
        RECT  64.692 78.96 64.776 78.984 ;
    END
  END a[591]
  PIN a[592]
    DIRECTION INPUT ;
    USE SIGNAL ;
    PORT
      LAYER M4 ;
        RECT  64.692 79.056 64.776 79.08 ;
    END
  END a[592]
  PIN a[593]
    DIRECTION INPUT ;
    USE SIGNAL ;
    PORT
      LAYER M4 ;
        RECT  64.692 79.152 64.776 79.176 ;
    END
  END a[593]
  PIN a[594]
    DIRECTION INPUT ;
    USE SIGNAL ;
    PORT
      LAYER M4 ;
        RECT  64.692 79.248 64.776 79.272 ;
    END
  END a[594]
  PIN a[595]
    DIRECTION INPUT ;
    USE SIGNAL ;
    PORT
      LAYER M4 ;
        RECT  64.692 79.344 64.776 79.368 ;
    END
  END a[595]
  PIN a[596]
    DIRECTION INPUT ;
    USE SIGNAL ;
    PORT
      LAYER M4 ;
        RECT  64.692 79.44 64.776 79.464 ;
    END
  END a[596]
  PIN a[597]
    DIRECTION INPUT ;
    USE SIGNAL ;
    PORT
      LAYER M4 ;
        RECT  64.692 79.536 64.776 79.56 ;
    END
  END a[597]
  PIN a[598]
    DIRECTION INPUT ;
    USE SIGNAL ;
    PORT
      LAYER M4 ;
        RECT  64.692 79.632 64.776 79.656 ;
    END
  END a[598]
  PIN a[599]
    DIRECTION INPUT ;
    USE SIGNAL ;
    PORT
      LAYER M4 ;
        RECT  64.692 79.728 64.776 79.752 ;
    END
  END a[599]
  PIN a[59]
    DIRECTION INPUT ;
    USE SIGNAL ;
    PORT
      LAYER M4 ;
        RECT  64.692 57.072 64.776 57.096 ;
    END
  END a[59]
  PIN a[5]
    DIRECTION INPUT ;
    USE SIGNAL ;
    PORT
      LAYER M4 ;
        RECT  64.692 42.672 64.776 42.696 ;
    END
  END a[5]
  PIN a[60]
    DIRECTION INPUT ;
    USE SIGNAL ;
    PORT
      LAYER M4 ;
        RECT  64.692 57.168 64.776 57.192 ;
    END
  END a[60]
  PIN a[61]
    DIRECTION INPUT ;
    USE SIGNAL ;
    PORT
      LAYER M4 ;
        RECT  64.692 57.264 64.776 57.288 ;
    END
  END a[61]
  PIN a[62]
    DIRECTION INPUT ;
    USE SIGNAL ;
    PORT
      LAYER M4 ;
        RECT  64.692 57.36 64.776 57.384 ;
    END
  END a[62]
  PIN a[63]
    DIRECTION INPUT ;
    USE SIGNAL ;
    PORT
      LAYER M4 ;
        RECT  64.692 57.456 64.776 57.48 ;
    END
  END a[63]
  PIN a[64]
    DIRECTION INPUT ;
    USE SIGNAL ;
    PORT
      LAYER M4 ;
        RECT  64.692 39.12 64.776 39.144 ;
    END
  END a[64]
  PIN a[65]
    DIRECTION INPUT ;
    USE SIGNAL ;
    PORT
      LAYER M4 ;
        RECT  64.692 39.216 64.776 39.24 ;
    END
  END a[65]
  PIN a[66]
    DIRECTION INPUT ;
    USE SIGNAL ;
    PORT
      LAYER M4 ;
        RECT  64.692 39.312 64.776 39.336 ;
    END
  END a[66]
  PIN a[67]
    DIRECTION INPUT ;
    USE SIGNAL ;
    PORT
      LAYER M4 ;
        RECT  64.692 39.408 64.776 39.432 ;
    END
  END a[67]
  PIN a[68]
    DIRECTION INPUT ;
    USE SIGNAL ;
    PORT
      LAYER M4 ;
        RECT  64.692 39.504 64.776 39.528 ;
    END
  END a[68]
  PIN a[69]
    DIRECTION INPUT ;
    USE SIGNAL ;
    PORT
      LAYER M4 ;
        RECT  64.692 39.6 64.776 39.624 ;
    END
  END a[69]
  PIN a[6]
    DIRECTION INPUT ;
    USE SIGNAL ;
    PORT
      LAYER M4 ;
        RECT  64.692 42.768 64.776 42.792 ;
    END
  END a[6]
  PIN a[70]
    DIRECTION INPUT ;
    USE SIGNAL ;
    PORT
      LAYER M4 ;
        RECT  64.692 39.696 64.776 39.72 ;
    END
  END a[70]
  PIN a[71]
    DIRECTION INPUT ;
    USE SIGNAL ;
    PORT
      LAYER M4 ;
        RECT  64.692 39.792 64.776 39.816 ;
    END
  END a[71]
  PIN a[72]
    DIRECTION INPUT ;
    USE SIGNAL ;
    PORT
      LAYER M4 ;
        RECT  64.692 39.888 64.776 39.912 ;
    END
  END a[72]
  PIN a[73]
    DIRECTION INPUT ;
    USE SIGNAL ;
    PORT
      LAYER M4 ;
        RECT  64.692 39.984 64.776 40.008 ;
    END
  END a[73]
  PIN a[74]
    DIRECTION INPUT ;
    USE SIGNAL ;
    PORT
      LAYER M4 ;
        RECT  64.692 40.08 64.776 40.104 ;
    END
  END a[74]
  PIN a[75]
    DIRECTION INPUT ;
    USE SIGNAL ;
    PORT
      LAYER M4 ;
        RECT  64.692 40.176 64.776 40.2 ;
    END
  END a[75]
  PIN a[76]
    DIRECTION INPUT ;
    USE SIGNAL ;
    PORT
      LAYER M4 ;
        RECT  64.692 40.272 64.776 40.296 ;
    END
  END a[76]
  PIN a[77]
    DIRECTION INPUT ;
    USE SIGNAL ;
    PORT
      LAYER M4 ;
        RECT  64.692 40.368 64.776 40.392 ;
    END
  END a[77]
  PIN a[78]
    DIRECTION INPUT ;
    USE SIGNAL ;
    PORT
      LAYER M4 ;
        RECT  64.692 40.464 64.776 40.488 ;
    END
  END a[78]
  PIN a[79]
    DIRECTION INPUT ;
    USE SIGNAL ;
    PORT
      LAYER M4 ;
        RECT  64.692 40.56 64.776 40.584 ;
    END
  END a[79]
  PIN a[7]
    DIRECTION INPUT ;
    USE SIGNAL ;
    PORT
      LAYER M4 ;
        RECT  64.692 42.864 64.776 42.888 ;
    END
  END a[7]
  PIN a[80]
    DIRECTION INPUT ;
    USE SIGNAL ;
    PORT
      LAYER M4 ;
        RECT  64.692 40.656 64.776 40.68 ;
    END
  END a[80]
  PIN a[81]
    DIRECTION INPUT ;
    USE SIGNAL ;
    PORT
      LAYER M4 ;
        RECT  64.692 40.752 64.776 40.776 ;
    END
  END a[81]
  PIN a[82]
    DIRECTION INPUT ;
    USE SIGNAL ;
    PORT
      LAYER M4 ;
        RECT  64.692 40.848 64.776 40.872 ;
    END
  END a[82]
  PIN a[83]
    DIRECTION INPUT ;
    USE SIGNAL ;
    PORT
      LAYER M4 ;
        RECT  64.692 40.944 64.776 40.968 ;
    END
  END a[83]
  PIN a[84]
    DIRECTION INPUT ;
    USE SIGNAL ;
    PORT
      LAYER M4 ;
        RECT  64.692 41.04 64.776 41.064 ;
    END
  END a[84]
  PIN a[85]
    DIRECTION INPUT ;
    USE SIGNAL ;
    PORT
      LAYER M4 ;
        RECT  64.692 41.136 64.776 41.16 ;
    END
  END a[85]
  PIN a[86]
    DIRECTION INPUT ;
    USE SIGNAL ;
    PORT
      LAYER M4 ;
        RECT  64.692 41.232 64.776 41.256 ;
    END
  END a[86]
  PIN a[87]
    DIRECTION INPUT ;
    USE SIGNAL ;
    PORT
      LAYER M4 ;
        RECT  64.692 41.328 64.776 41.352 ;
    END
  END a[87]
  PIN a[88]
    DIRECTION INPUT ;
    USE SIGNAL ;
    PORT
      LAYER M4 ;
        RECT  64.692 41.424 64.776 41.448 ;
    END
  END a[88]
  PIN a[89]
    DIRECTION INPUT ;
    USE SIGNAL ;
    PORT
      LAYER M4 ;
        RECT  64.692 41.52 64.776 41.544 ;
    END
  END a[89]
  PIN a[8]
    DIRECTION INPUT ;
    USE SIGNAL ;
    PORT
      LAYER M4 ;
        RECT  64.692 42.96 64.776 42.984 ;
    END
  END a[8]
  PIN a[90]
    DIRECTION INPUT ;
    USE SIGNAL ;
    PORT
      LAYER M4 ;
        RECT  64.692 41.616 64.776 41.64 ;
    END
  END a[90]
  PIN a[91]
    DIRECTION INPUT ;
    USE SIGNAL ;
    PORT
      LAYER M4 ;
        RECT  64.692 41.712 64.776 41.736 ;
    END
  END a[91]
  PIN a[92]
    DIRECTION INPUT ;
    USE SIGNAL ;
    PORT
      LAYER M4 ;
        RECT  64.692 41.808 64.776 41.832 ;
    END
  END a[92]
  PIN a[93]
    DIRECTION INPUT ;
    USE SIGNAL ;
    PORT
      LAYER M4 ;
        RECT  64.692 41.904 64.776 41.928 ;
    END
  END a[93]
  PIN a[94]
    DIRECTION INPUT ;
    USE SIGNAL ;
    PORT
      LAYER M4 ;
        RECT  64.692 42 64.776 42.024 ;
    END
  END a[94]
  PIN a[95]
    DIRECTION INPUT ;
    USE SIGNAL ;
    PORT
      LAYER M4 ;
        RECT  64.692 42.096 64.776 42.12 ;
    END
  END a[95]
  PIN a[96]
    DIRECTION INPUT ;
    USE SIGNAL ;
    PORT
      LAYER M4 ;
        RECT  64.692 45.264 64.776 45.288 ;
    END
  END a[96]
  PIN a[97]
    DIRECTION INPUT ;
    USE SIGNAL ;
    PORT
      LAYER M4 ;
        RECT  64.692 45.36 64.776 45.384 ;
    END
  END a[97]
  PIN a[98]
    DIRECTION INPUT ;
    USE SIGNAL ;
    PORT
      LAYER M4 ;
        RECT  64.692 45.456 64.776 45.48 ;
    END
  END a[98]
  PIN a[99]
    DIRECTION INPUT ;
    USE SIGNAL ;
    PORT
      LAYER M4 ;
        RECT  64.692 45.552 64.776 45.576 ;
    END
  END a[99]
  PIN a[9]
    DIRECTION INPUT ;
    USE SIGNAL ;
    PORT
      LAYER M4 ;
        RECT  64.692 43.056 64.776 43.08 ;
    END
  END a[9]
  PIN b[0]
    DIRECTION OUTPUT ;
    USE SIGNAL ;
    PORT
      LAYER M4 ;
        RECT  0 48.336 0.084 48.36 ;
    END
  END b[0]
  PIN b[100]
    DIRECTION OUTPUT ;
    USE SIGNAL ;
    PORT
      LAYER M4 ;
        RECT  0 64.08 0.084 64.104 ;
    END
  END b[100]
  PIN b[101]
    DIRECTION OUTPUT ;
    USE SIGNAL ;
    PORT
      LAYER M4 ;
        RECT  0 64.176 0.084 64.2 ;
    END
  END b[101]
  PIN b[102]
    DIRECTION OUTPUT ;
    USE SIGNAL ;
    PORT
      LAYER M4 ;
        RECT  0 64.272 0.084 64.296 ;
    END
  END b[102]
  PIN b[103]
    DIRECTION OUTPUT ;
    USE SIGNAL ;
    PORT
      LAYER M4 ;
        RECT  0 64.368 0.084 64.392 ;
    END
  END b[103]
  PIN b[104]
    DIRECTION OUTPUT ;
    USE SIGNAL ;
    PORT
      LAYER M4 ;
        RECT  0 64.464 0.084 64.488 ;
    END
  END b[104]
  PIN b[105]
    DIRECTION OUTPUT ;
    USE SIGNAL ;
    PORT
      LAYER M4 ;
        RECT  0 64.56 0.084 64.584 ;
    END
  END b[105]
  PIN b[106]
    DIRECTION OUTPUT ;
    USE SIGNAL ;
    PORT
      LAYER M4 ;
        RECT  0 64.656 0.084 64.68 ;
    END
  END b[106]
  PIN b[107]
    DIRECTION OUTPUT ;
    USE SIGNAL ;
    PORT
      LAYER M4 ;
        RECT  0 64.752 0.084 64.776 ;
    END
  END b[107]
  PIN b[108]
    DIRECTION OUTPUT ;
    USE SIGNAL ;
    PORT
      LAYER M4 ;
        RECT  0 64.848 0.084 64.872 ;
    END
  END b[108]
  PIN b[109]
    DIRECTION OUTPUT ;
    USE SIGNAL ;
    PORT
      LAYER M4 ;
        RECT  0 64.944 0.084 64.968 ;
    END
  END b[109]
  PIN b[10]
    DIRECTION OUTPUT ;
    USE SIGNAL ;
    PORT
      LAYER M4 ;
        RECT  0 49.296 0.084 49.32 ;
    END
  END b[10]
  PIN b[110]
    DIRECTION OUTPUT ;
    USE SIGNAL ;
    PORT
      LAYER M4 ;
        RECT  0 65.04 0.084 65.064 ;
    END
  END b[110]
  PIN b[111]
    DIRECTION OUTPUT ;
    USE SIGNAL ;
    PORT
      LAYER M4 ;
        RECT  0 65.136 0.084 65.16 ;
    END
  END b[111]
  PIN b[112]
    DIRECTION OUTPUT ;
    USE SIGNAL ;
    PORT
      LAYER M4 ;
        RECT  0 65.232 0.084 65.256 ;
    END
  END b[112]
  PIN b[113]
    DIRECTION OUTPUT ;
    USE SIGNAL ;
    PORT
      LAYER M4 ;
        RECT  0 65.328 0.084 65.352 ;
    END
  END b[113]
  PIN b[114]
    DIRECTION OUTPUT ;
    USE SIGNAL ;
    PORT
      LAYER M4 ;
        RECT  0 65.424 0.084 65.448 ;
    END
  END b[114]
  PIN b[115]
    DIRECTION OUTPUT ;
    USE SIGNAL ;
    PORT
      LAYER M4 ;
        RECT  0 65.52 0.084 65.544 ;
    END
  END b[115]
  PIN b[116]
    DIRECTION OUTPUT ;
    USE SIGNAL ;
    PORT
      LAYER M4 ;
        RECT  0 65.616 0.084 65.64 ;
    END
  END b[116]
  PIN b[117]
    DIRECTION OUTPUT ;
    USE SIGNAL ;
    PORT
      LAYER M4 ;
        RECT  0 65.712 0.084 65.736 ;
    END
  END b[117]
  PIN b[118]
    DIRECTION OUTPUT ;
    USE SIGNAL ;
    PORT
      LAYER M4 ;
        RECT  0 65.808 0.084 65.832 ;
    END
  END b[118]
  PIN b[119]
    DIRECTION OUTPUT ;
    USE SIGNAL ;
    PORT
      LAYER M4 ;
        RECT  0 65.904 0.084 65.928 ;
    END
  END b[119]
  PIN b[11]
    DIRECTION OUTPUT ;
    USE SIGNAL ;
    PORT
      LAYER M4 ;
        RECT  0 49.392 0.084 49.416 ;
    END
  END b[11]
  PIN b[120]
    DIRECTION OUTPUT ;
    USE SIGNAL ;
    PORT
      LAYER M4 ;
        RECT  0 66 0.084 66.024 ;
    END
  END b[120]
  PIN b[121]
    DIRECTION OUTPUT ;
    USE SIGNAL ;
    PORT
      LAYER M4 ;
        RECT  0 66.096 0.084 66.12 ;
    END
  END b[121]
  PIN b[122]
    DIRECTION OUTPUT ;
    USE SIGNAL ;
    PORT
      LAYER M4 ;
        RECT  0 66.192 0.084 66.216 ;
    END
  END b[122]
  PIN b[123]
    DIRECTION OUTPUT ;
    USE SIGNAL ;
    PORT
      LAYER M4 ;
        RECT  0 66.288 0.084 66.312 ;
    END
  END b[123]
  PIN b[124]
    DIRECTION OUTPUT ;
    USE SIGNAL ;
    PORT
      LAYER M4 ;
        RECT  0 66.384 0.084 66.408 ;
    END
  END b[124]
  PIN b[125]
    DIRECTION OUTPUT ;
    USE SIGNAL ;
    PORT
      LAYER M4 ;
        RECT  0 66.48 0.084 66.504 ;
    END
  END b[125]
  PIN b[126]
    DIRECTION OUTPUT ;
    USE SIGNAL ;
    PORT
      LAYER M4 ;
        RECT  0 66.576 0.084 66.6 ;
    END
  END b[126]
  PIN b[127]
    DIRECTION OUTPUT ;
    USE SIGNAL ;
    PORT
      LAYER M4 ;
        RECT  0 66.672 0.084 66.696 ;
    END
  END b[127]
  PIN b[128]
    DIRECTION OUTPUT ;
    USE SIGNAL ;
    PORT
      LAYER M4 ;
        RECT  0 57.552 0.084 57.576 ;
    END
  END b[128]
  PIN b[129]
    DIRECTION OUTPUT ;
    USE SIGNAL ;
    PORT
      LAYER M4 ;
        RECT  0 57.648 0.084 57.672 ;
    END
  END b[129]
  PIN b[12]
    DIRECTION OUTPUT ;
    USE SIGNAL ;
    PORT
      LAYER M4 ;
        RECT  0 49.488 0.084 49.512 ;
    END
  END b[12]
  PIN b[130]
    DIRECTION OUTPUT ;
    USE SIGNAL ;
    PORT
      LAYER M4 ;
        RECT  0 57.744 0.084 57.768 ;
    END
  END b[130]
  PIN b[131]
    DIRECTION OUTPUT ;
    USE SIGNAL ;
    PORT
      LAYER M4 ;
        RECT  0 57.84 0.084 57.864 ;
    END
  END b[131]
  PIN b[132]
    DIRECTION OUTPUT ;
    USE SIGNAL ;
    PORT
      LAYER M4 ;
        RECT  0 57.936 0.084 57.96 ;
    END
  END b[132]
  PIN b[133]
    DIRECTION OUTPUT ;
    USE SIGNAL ;
    PORT
      LAYER M4 ;
        RECT  0 58.032 0.084 58.056 ;
    END
  END b[133]
  PIN b[134]
    DIRECTION OUTPUT ;
    USE SIGNAL ;
    PORT
      LAYER M4 ;
        RECT  0 58.128 0.084 58.152 ;
    END
  END b[134]
  PIN b[135]
    DIRECTION OUTPUT ;
    USE SIGNAL ;
    PORT
      LAYER M4 ;
        RECT  0 58.224 0.084 58.248 ;
    END
  END b[135]
  PIN b[136]
    DIRECTION OUTPUT ;
    USE SIGNAL ;
    PORT
      LAYER M4 ;
        RECT  0 58.32 0.084 58.344 ;
    END
  END b[136]
  PIN b[137]
    DIRECTION OUTPUT ;
    USE SIGNAL ;
    PORT
      LAYER M4 ;
        RECT  0 58.416 0.084 58.44 ;
    END
  END b[137]
  PIN b[138]
    DIRECTION OUTPUT ;
    USE SIGNAL ;
    PORT
      LAYER M4 ;
        RECT  0 58.512 0.084 58.536 ;
    END
  END b[138]
  PIN b[139]
    DIRECTION OUTPUT ;
    USE SIGNAL ;
    PORT
      LAYER M4 ;
        RECT  0 58.608 0.084 58.632 ;
    END
  END b[139]
  PIN b[13]
    DIRECTION OUTPUT ;
    USE SIGNAL ;
    PORT
      LAYER M4 ;
        RECT  0 49.584 0.084 49.608 ;
    END
  END b[13]
  PIN b[140]
    DIRECTION OUTPUT ;
    USE SIGNAL ;
    PORT
      LAYER M4 ;
        RECT  0 58.704 0.084 58.728 ;
    END
  END b[140]
  PIN b[141]
    DIRECTION OUTPUT ;
    USE SIGNAL ;
    PORT
      LAYER M4 ;
        RECT  0 58.8 0.084 58.824 ;
    END
  END b[141]
  PIN b[142]
    DIRECTION OUTPUT ;
    USE SIGNAL ;
    PORT
      LAYER M4 ;
        RECT  0 58.896 0.084 58.92 ;
    END
  END b[142]
  PIN b[143]
    DIRECTION OUTPUT ;
    USE SIGNAL ;
    PORT
      LAYER M4 ;
        RECT  0 58.992 0.084 59.016 ;
    END
  END b[143]
  PIN b[144]
    DIRECTION OUTPUT ;
    USE SIGNAL ;
    PORT
      LAYER M4 ;
        RECT  0 59.088 0.084 59.112 ;
    END
  END b[144]
  PIN b[145]
    DIRECTION OUTPUT ;
    USE SIGNAL ;
    PORT
      LAYER M4 ;
        RECT  0 59.184 0.084 59.208 ;
    END
  END b[145]
  PIN b[146]
    DIRECTION OUTPUT ;
    USE SIGNAL ;
    PORT
      LAYER M4 ;
        RECT  0 59.28 0.084 59.304 ;
    END
  END b[146]
  PIN b[147]
    DIRECTION OUTPUT ;
    USE SIGNAL ;
    PORT
      LAYER M4 ;
        RECT  0 59.376 0.084 59.4 ;
    END
  END b[147]
  PIN b[148]
    DIRECTION OUTPUT ;
    USE SIGNAL ;
    PORT
      LAYER M4 ;
        RECT  0 59.472 0.084 59.496 ;
    END
  END b[148]
  PIN b[149]
    DIRECTION OUTPUT ;
    USE SIGNAL ;
    PORT
      LAYER M4 ;
        RECT  0 59.568 0.084 59.592 ;
    END
  END b[149]
  PIN b[14]
    DIRECTION OUTPUT ;
    USE SIGNAL ;
    PORT
      LAYER M4 ;
        RECT  0 49.68 0.084 49.704 ;
    END
  END b[14]
  PIN b[150]
    DIRECTION OUTPUT ;
    USE SIGNAL ;
    PORT
      LAYER M4 ;
        RECT  0 59.664 0.084 59.688 ;
    END
  END b[150]
  PIN b[151]
    DIRECTION OUTPUT ;
    USE SIGNAL ;
    PORT
      LAYER M4 ;
        RECT  0 59.76 0.084 59.784 ;
    END
  END b[151]
  PIN b[152]
    DIRECTION OUTPUT ;
    USE SIGNAL ;
    PORT
      LAYER M4 ;
        RECT  0 59.856 0.084 59.88 ;
    END
  END b[152]
  PIN b[153]
    DIRECTION OUTPUT ;
    USE SIGNAL ;
    PORT
      LAYER M4 ;
        RECT  0 59.952 0.084 59.976 ;
    END
  END b[153]
  PIN b[154]
    DIRECTION OUTPUT ;
    USE SIGNAL ;
    PORT
      LAYER M4 ;
        RECT  0 60.048 0.084 60.072 ;
    END
  END b[154]
  PIN b[155]
    DIRECTION OUTPUT ;
    USE SIGNAL ;
    PORT
      LAYER M4 ;
        RECT  0 60.144 0.084 60.168 ;
    END
  END b[155]
  PIN b[156]
    DIRECTION OUTPUT ;
    USE SIGNAL ;
    PORT
      LAYER M4 ;
        RECT  0 60.24 0.084 60.264 ;
    END
  END b[156]
  PIN b[157]
    DIRECTION OUTPUT ;
    USE SIGNAL ;
    PORT
      LAYER M4 ;
        RECT  0 60.336 0.084 60.36 ;
    END
  END b[157]
  PIN b[158]
    DIRECTION OUTPUT ;
    USE SIGNAL ;
    PORT
      LAYER M4 ;
        RECT  0 60.432 0.084 60.456 ;
    END
  END b[158]
  PIN b[159]
    DIRECTION OUTPUT ;
    USE SIGNAL ;
    PORT
      LAYER M4 ;
        RECT  0 60.528 0.084 60.552 ;
    END
  END b[159]
  PIN b[15]
    DIRECTION OUTPUT ;
    USE SIGNAL ;
    PORT
      LAYER M4 ;
        RECT  0 49.776 0.084 49.8 ;
    END
  END b[15]
  PIN b[160]
    DIRECTION OUTPUT ;
    USE SIGNAL ;
    PORT
      LAYER M4 ;
        RECT  0 54.48 0.084 54.504 ;
    END
  END b[160]
  PIN b[161]
    DIRECTION OUTPUT ;
    USE SIGNAL ;
    PORT
      LAYER M4 ;
        RECT  0 54.576 0.084 54.6 ;
    END
  END b[161]
  PIN b[162]
    DIRECTION OUTPUT ;
    USE SIGNAL ;
    PORT
      LAYER M4 ;
        RECT  0 54.672 0.084 54.696 ;
    END
  END b[162]
  PIN b[163]
    DIRECTION OUTPUT ;
    USE SIGNAL ;
    PORT
      LAYER M4 ;
        RECT  0 54.768 0.084 54.792 ;
    END
  END b[163]
  PIN b[164]
    DIRECTION OUTPUT ;
    USE SIGNAL ;
    PORT
      LAYER M4 ;
        RECT  0 54.864 0.084 54.888 ;
    END
  END b[164]
  PIN b[165]
    DIRECTION OUTPUT ;
    USE SIGNAL ;
    PORT
      LAYER M4 ;
        RECT  0 54.96 0.084 54.984 ;
    END
  END b[165]
  PIN b[166]
    DIRECTION OUTPUT ;
    USE SIGNAL ;
    PORT
      LAYER M4 ;
        RECT  0 55.056 0.084 55.08 ;
    END
  END b[166]
  PIN b[167]
    DIRECTION OUTPUT ;
    USE SIGNAL ;
    PORT
      LAYER M4 ;
        RECT  0 55.152 0.084 55.176 ;
    END
  END b[167]
  PIN b[168]
    DIRECTION OUTPUT ;
    USE SIGNAL ;
    PORT
      LAYER M4 ;
        RECT  0 55.248 0.084 55.272 ;
    END
  END b[168]
  PIN b[169]
    DIRECTION OUTPUT ;
    USE SIGNAL ;
    PORT
      LAYER M4 ;
        RECT  0 55.344 0.084 55.368 ;
    END
  END b[169]
  PIN b[16]
    DIRECTION OUTPUT ;
    USE SIGNAL ;
    PORT
      LAYER M4 ;
        RECT  0 49.872 0.084 49.896 ;
    END
  END b[16]
  PIN b[170]
    DIRECTION OUTPUT ;
    USE SIGNAL ;
    PORT
      LAYER M4 ;
        RECT  0 55.44 0.084 55.464 ;
    END
  END b[170]
  PIN b[171]
    DIRECTION OUTPUT ;
    USE SIGNAL ;
    PORT
      LAYER M4 ;
        RECT  0 55.536 0.084 55.56 ;
    END
  END b[171]
  PIN b[172]
    DIRECTION OUTPUT ;
    USE SIGNAL ;
    PORT
      LAYER M4 ;
        RECT  0 55.632 0.084 55.656 ;
    END
  END b[172]
  PIN b[173]
    DIRECTION OUTPUT ;
    USE SIGNAL ;
    PORT
      LAYER M4 ;
        RECT  0 55.728 0.084 55.752 ;
    END
  END b[173]
  PIN b[174]
    DIRECTION OUTPUT ;
    USE SIGNAL ;
    PORT
      LAYER M4 ;
        RECT  0 55.824 0.084 55.848 ;
    END
  END b[174]
  PIN b[175]
    DIRECTION OUTPUT ;
    USE SIGNAL ;
    PORT
      LAYER M4 ;
        RECT  0 55.92 0.084 55.944 ;
    END
  END b[175]
  PIN b[176]
    DIRECTION OUTPUT ;
    USE SIGNAL ;
    PORT
      LAYER M4 ;
        RECT  0 56.016 0.084 56.04 ;
    END
  END b[176]
  PIN b[177]
    DIRECTION OUTPUT ;
    USE SIGNAL ;
    PORT
      LAYER M4 ;
        RECT  0 56.112 0.084 56.136 ;
    END
  END b[177]
  PIN b[178]
    DIRECTION OUTPUT ;
    USE SIGNAL ;
    PORT
      LAYER M4 ;
        RECT  0 56.208 0.084 56.232 ;
    END
  END b[178]
  PIN b[179]
    DIRECTION OUTPUT ;
    USE SIGNAL ;
    PORT
      LAYER M4 ;
        RECT  0 56.304 0.084 56.328 ;
    END
  END b[179]
  PIN b[17]
    DIRECTION OUTPUT ;
    USE SIGNAL ;
    PORT
      LAYER M4 ;
        RECT  0 49.968 0.084 49.992 ;
    END
  END b[17]
  PIN b[180]
    DIRECTION OUTPUT ;
    USE SIGNAL ;
    PORT
      LAYER M4 ;
        RECT  0 56.4 0.084 56.424 ;
    END
  END b[180]
  PIN b[181]
    DIRECTION OUTPUT ;
    USE SIGNAL ;
    PORT
      LAYER M4 ;
        RECT  0 56.496 0.084 56.52 ;
    END
  END b[181]
  PIN b[182]
    DIRECTION OUTPUT ;
    USE SIGNAL ;
    PORT
      LAYER M4 ;
        RECT  0 56.592 0.084 56.616 ;
    END
  END b[182]
  PIN b[183]
    DIRECTION OUTPUT ;
    USE SIGNAL ;
    PORT
      LAYER M4 ;
        RECT  0 56.688 0.084 56.712 ;
    END
  END b[183]
  PIN b[184]
    DIRECTION OUTPUT ;
    USE SIGNAL ;
    PORT
      LAYER M4 ;
        RECT  0 56.784 0.084 56.808 ;
    END
  END b[184]
  PIN b[185]
    DIRECTION OUTPUT ;
    USE SIGNAL ;
    PORT
      LAYER M4 ;
        RECT  0 56.88 0.084 56.904 ;
    END
  END b[185]
  PIN b[186]
    DIRECTION OUTPUT ;
    USE SIGNAL ;
    PORT
      LAYER M4 ;
        RECT  0 56.976 0.084 57 ;
    END
  END b[186]
  PIN b[187]
    DIRECTION OUTPUT ;
    USE SIGNAL ;
    PORT
      LAYER M4 ;
        RECT  0 57.072 0.084 57.096 ;
    END
  END b[187]
  PIN b[188]
    DIRECTION OUTPUT ;
    USE SIGNAL ;
    PORT
      LAYER M4 ;
        RECT  0 57.168 0.084 57.192 ;
    END
  END b[188]
  PIN b[189]
    DIRECTION OUTPUT ;
    USE SIGNAL ;
    PORT
      LAYER M4 ;
        RECT  0 57.264 0.084 57.288 ;
    END
  END b[189]
  PIN b[18]
    DIRECTION OUTPUT ;
    USE SIGNAL ;
    PORT
      LAYER M4 ;
        RECT  0 50.064 0.084 50.088 ;
    END
  END b[18]
  PIN b[190]
    DIRECTION OUTPUT ;
    USE SIGNAL ;
    PORT
      LAYER M4 ;
        RECT  0 57.36 0.084 57.384 ;
    END
  END b[190]
  PIN b[191]
    DIRECTION OUTPUT ;
    USE SIGNAL ;
    PORT
      LAYER M4 ;
        RECT  0 57.456 0.084 57.48 ;
    END
  END b[191]
  PIN b[192]
    DIRECTION OUTPUT ;
    USE SIGNAL ;
    PORT
      LAYER M4 ;
        RECT  0 32.208 0.084 32.232 ;
    END
  END b[192]
  PIN b[193]
    DIRECTION OUTPUT ;
    USE SIGNAL ;
    PORT
      LAYER M4 ;
        RECT  0 32.304 0.084 32.328 ;
    END
  END b[193]
  PIN b[194]
    DIRECTION OUTPUT ;
    USE SIGNAL ;
    PORT
      LAYER M4 ;
        RECT  0 32.4 0.084 32.424 ;
    END
  END b[194]
  PIN b[195]
    DIRECTION OUTPUT ;
    USE SIGNAL ;
    PORT
      LAYER M4 ;
        RECT  0 32.496 0.084 32.52 ;
    END
  END b[195]
  PIN b[196]
    DIRECTION OUTPUT ;
    USE SIGNAL ;
    PORT
      LAYER M4 ;
        RECT  0 32.592 0.084 32.616 ;
    END
  END b[196]
  PIN b[197]
    DIRECTION OUTPUT ;
    USE SIGNAL ;
    PORT
      LAYER M4 ;
        RECT  0 32.688 0.084 32.712 ;
    END
  END b[197]
  PIN b[198]
    DIRECTION OUTPUT ;
    USE SIGNAL ;
    PORT
      LAYER M4 ;
        RECT  0 32.784 0.084 32.808 ;
    END
  END b[198]
  PIN b[199]
    DIRECTION OUTPUT ;
    USE SIGNAL ;
    PORT
      LAYER M4 ;
        RECT  0 32.88 0.084 32.904 ;
    END
  END b[199]
  PIN b[19]
    DIRECTION OUTPUT ;
    USE SIGNAL ;
    PORT
      LAYER M4 ;
        RECT  0 50.16 0.084 50.184 ;
    END
  END b[19]
  PIN b[1]
    DIRECTION OUTPUT ;
    USE SIGNAL ;
    PORT
      LAYER M4 ;
        RECT  0 48.432 0.084 48.456 ;
    END
  END b[1]
  PIN b[200]
    DIRECTION OUTPUT ;
    USE SIGNAL ;
    PORT
      LAYER M4 ;
        RECT  0 32.976 0.084 33 ;
    END
  END b[200]
  PIN b[201]
    DIRECTION OUTPUT ;
    USE SIGNAL ;
    PORT
      LAYER M4 ;
        RECT  0 33.072 0.084 33.096 ;
    END
  END b[201]
  PIN b[202]
    DIRECTION OUTPUT ;
    USE SIGNAL ;
    PORT
      LAYER M4 ;
        RECT  0 33.168 0.084 33.192 ;
    END
  END b[202]
  PIN b[203]
    DIRECTION OUTPUT ;
    USE SIGNAL ;
    PORT
      LAYER M4 ;
        RECT  0 33.264 0.084 33.288 ;
    END
  END b[203]
  PIN b[204]
    DIRECTION OUTPUT ;
    USE SIGNAL ;
    PORT
      LAYER M4 ;
        RECT  0 33.36 0.084 33.384 ;
    END
  END b[204]
  PIN b[205]
    DIRECTION OUTPUT ;
    USE SIGNAL ;
    PORT
      LAYER M4 ;
        RECT  0 33.456 0.084 33.48 ;
    END
  END b[205]
  PIN b[206]
    DIRECTION OUTPUT ;
    USE SIGNAL ;
    PORT
      LAYER M4 ;
        RECT  0 33.552 0.084 33.576 ;
    END
  END b[206]
  PIN b[207]
    DIRECTION OUTPUT ;
    USE SIGNAL ;
    PORT
      LAYER M4 ;
        RECT  0 33.648 0.084 33.672 ;
    END
  END b[207]
  PIN b[208]
    DIRECTION OUTPUT ;
    USE SIGNAL ;
    PORT
      LAYER M4 ;
        RECT  0 33.744 0.084 33.768 ;
    END
  END b[208]
  PIN b[209]
    DIRECTION OUTPUT ;
    USE SIGNAL ;
    PORT
      LAYER M4 ;
        RECT  0 33.84 0.084 33.864 ;
    END
  END b[209]
  PIN b[20]
    DIRECTION OUTPUT ;
    USE SIGNAL ;
    PORT
      LAYER M4 ;
        RECT  0 50.256 0.084 50.28 ;
    END
  END b[20]
  PIN b[210]
    DIRECTION OUTPUT ;
    USE SIGNAL ;
    PORT
      LAYER M4 ;
        RECT  0 33.936 0.084 33.96 ;
    END
  END b[210]
  PIN b[211]
    DIRECTION OUTPUT ;
    USE SIGNAL ;
    PORT
      LAYER M4 ;
        RECT  0 34.032 0.084 34.056 ;
    END
  END b[211]
  PIN b[212]
    DIRECTION OUTPUT ;
    USE SIGNAL ;
    PORT
      LAYER M4 ;
        RECT  0 34.128 0.084 34.152 ;
    END
  END b[212]
  PIN b[213]
    DIRECTION OUTPUT ;
    USE SIGNAL ;
    PORT
      LAYER M4 ;
        RECT  0 34.224 0.084 34.248 ;
    END
  END b[213]
  PIN b[214]
    DIRECTION OUTPUT ;
    USE SIGNAL ;
    PORT
      LAYER M4 ;
        RECT  0 34.32 0.084 34.344 ;
    END
  END b[214]
  PIN b[215]
    DIRECTION OUTPUT ;
    USE SIGNAL ;
    PORT
      LAYER M4 ;
        RECT  0 34.416 0.084 34.44 ;
    END
  END b[215]
  PIN b[216]
    DIRECTION OUTPUT ;
    USE SIGNAL ;
    PORT
      LAYER M4 ;
        RECT  0 34.512 0.084 34.536 ;
    END
  END b[216]
  PIN b[217]
    DIRECTION OUTPUT ;
    USE SIGNAL ;
    PORT
      LAYER M4 ;
        RECT  0 34.608 0.084 34.632 ;
    END
  END b[217]
  PIN b[218]
    DIRECTION OUTPUT ;
    USE SIGNAL ;
    PORT
      LAYER M4 ;
        RECT  0 34.704 0.084 34.728 ;
    END
  END b[218]
  PIN b[219]
    DIRECTION OUTPUT ;
    USE SIGNAL ;
    PORT
      LAYER M4 ;
        RECT  0 34.8 0.084 34.824 ;
    END
  END b[219]
  PIN b[21]
    DIRECTION OUTPUT ;
    USE SIGNAL ;
    PORT
      LAYER M4 ;
        RECT  0 50.352 0.084 50.376 ;
    END
  END b[21]
  PIN b[220]
    DIRECTION OUTPUT ;
    USE SIGNAL ;
    PORT
      LAYER M4 ;
        RECT  0 34.896 0.084 34.92 ;
    END
  END b[220]
  PIN b[221]
    DIRECTION OUTPUT ;
    USE SIGNAL ;
    PORT
      LAYER M4 ;
        RECT  0 34.992 0.084 35.016 ;
    END
  END b[221]
  PIN b[222]
    DIRECTION OUTPUT ;
    USE SIGNAL ;
    PORT
      LAYER M4 ;
        RECT  0 35.088 0.084 35.112 ;
    END
  END b[222]
  PIN b[223]
    DIRECTION OUTPUT ;
    USE SIGNAL ;
    PORT
      LAYER M4 ;
        RECT  0 35.184 0.084 35.208 ;
    END
  END b[223]
  PIN b[224]
    DIRECTION OUTPUT ;
    USE SIGNAL ;
    PORT
      LAYER M4 ;
        RECT  0 41.424 0.084 41.448 ;
    END
  END b[224]
  PIN b[225]
    DIRECTION OUTPUT ;
    USE SIGNAL ;
    PORT
      LAYER M4 ;
        RECT  0 41.52 0.084 41.544 ;
    END
  END b[225]
  PIN b[226]
    DIRECTION OUTPUT ;
    USE SIGNAL ;
    PORT
      LAYER M4 ;
        RECT  0 41.616 0.084 41.64 ;
    END
  END b[226]
  PIN b[227]
    DIRECTION OUTPUT ;
    USE SIGNAL ;
    PORT
      LAYER M4 ;
        RECT  0 41.712 0.084 41.736 ;
    END
  END b[227]
  PIN b[228]
    DIRECTION OUTPUT ;
    USE SIGNAL ;
    PORT
      LAYER M4 ;
        RECT  0 41.808 0.084 41.832 ;
    END
  END b[228]
  PIN b[229]
    DIRECTION OUTPUT ;
    USE SIGNAL ;
    PORT
      LAYER M4 ;
        RECT  0 41.904 0.084 41.928 ;
    END
  END b[229]
  PIN b[22]
    DIRECTION OUTPUT ;
    USE SIGNAL ;
    PORT
      LAYER M4 ;
        RECT  0 50.448 0.084 50.472 ;
    END
  END b[22]
  PIN b[230]
    DIRECTION OUTPUT ;
    USE SIGNAL ;
    PORT
      LAYER M4 ;
        RECT  0 42 0.084 42.024 ;
    END
  END b[230]
  PIN b[231]
    DIRECTION OUTPUT ;
    USE SIGNAL ;
    PORT
      LAYER M4 ;
        RECT  0 42.096 0.084 42.12 ;
    END
  END b[231]
  PIN b[232]
    DIRECTION OUTPUT ;
    USE SIGNAL ;
    PORT
      LAYER M4 ;
        RECT  0 42.192 0.084 42.216 ;
    END
  END b[232]
  PIN b[233]
    DIRECTION OUTPUT ;
    USE SIGNAL ;
    PORT
      LAYER M4 ;
        RECT  0 42.288 0.084 42.312 ;
    END
  END b[233]
  PIN b[234]
    DIRECTION OUTPUT ;
    USE SIGNAL ;
    PORT
      LAYER M4 ;
        RECT  0 42.384 0.084 42.408 ;
    END
  END b[234]
  PIN b[235]
    DIRECTION OUTPUT ;
    USE SIGNAL ;
    PORT
      LAYER M4 ;
        RECT  0 42.48 0.084 42.504 ;
    END
  END b[235]
  PIN b[236]
    DIRECTION OUTPUT ;
    USE SIGNAL ;
    PORT
      LAYER M4 ;
        RECT  0 42.576 0.084 42.6 ;
    END
  END b[236]
  PIN b[237]
    DIRECTION OUTPUT ;
    USE SIGNAL ;
    PORT
      LAYER M4 ;
        RECT  0 42.672 0.084 42.696 ;
    END
  END b[237]
  PIN b[238]
    DIRECTION OUTPUT ;
    USE SIGNAL ;
    PORT
      LAYER M4 ;
        RECT  0 42.768 0.084 42.792 ;
    END
  END b[238]
  PIN b[239]
    DIRECTION OUTPUT ;
    USE SIGNAL ;
    PORT
      LAYER M4 ;
        RECT  0 42.864 0.084 42.888 ;
    END
  END b[239]
  PIN b[23]
    DIRECTION OUTPUT ;
    USE SIGNAL ;
    PORT
      LAYER M4 ;
        RECT  0 50.544 0.084 50.568 ;
    END
  END b[23]
  PIN b[240]
    DIRECTION OUTPUT ;
    USE SIGNAL ;
    PORT
      LAYER M4 ;
        RECT  0 42.96 0.084 42.984 ;
    END
  END b[240]
  PIN b[241]
    DIRECTION OUTPUT ;
    USE SIGNAL ;
    PORT
      LAYER M4 ;
        RECT  0 43.056 0.084 43.08 ;
    END
  END b[241]
  PIN b[242]
    DIRECTION OUTPUT ;
    USE SIGNAL ;
    PORT
      LAYER M4 ;
        RECT  0 43.152 0.084 43.176 ;
    END
  END b[242]
  PIN b[243]
    DIRECTION OUTPUT ;
    USE SIGNAL ;
    PORT
      LAYER M4 ;
        RECT  0 43.248 0.084 43.272 ;
    END
  END b[243]
  PIN b[244]
    DIRECTION OUTPUT ;
    USE SIGNAL ;
    PORT
      LAYER M4 ;
        RECT  0 43.344 0.084 43.368 ;
    END
  END b[244]
  PIN b[245]
    DIRECTION OUTPUT ;
    USE SIGNAL ;
    PORT
      LAYER M4 ;
        RECT  0 43.44 0.084 43.464 ;
    END
  END b[245]
  PIN b[246]
    DIRECTION OUTPUT ;
    USE SIGNAL ;
    PORT
      LAYER M4 ;
        RECT  0 43.536 0.084 43.56 ;
    END
  END b[246]
  PIN b[247]
    DIRECTION OUTPUT ;
    USE SIGNAL ;
    PORT
      LAYER M4 ;
        RECT  0 43.632 0.084 43.656 ;
    END
  END b[247]
  PIN b[248]
    DIRECTION OUTPUT ;
    USE SIGNAL ;
    PORT
      LAYER M4 ;
        RECT  0 43.728 0.084 43.752 ;
    END
  END b[248]
  PIN b[249]
    DIRECTION OUTPUT ;
    USE SIGNAL ;
    PORT
      LAYER M4 ;
        RECT  0 43.824 0.084 43.848 ;
    END
  END b[249]
  PIN b[24]
    DIRECTION OUTPUT ;
    USE SIGNAL ;
    PORT
      LAYER M4 ;
        RECT  0 50.64 0.084 50.664 ;
    END
  END b[24]
  PIN b[250]
    DIRECTION OUTPUT ;
    USE SIGNAL ;
    PORT
      LAYER M4 ;
        RECT  0 43.92 0.084 43.944 ;
    END
  END b[250]
  PIN b[251]
    DIRECTION OUTPUT ;
    USE SIGNAL ;
    PORT
      LAYER M4 ;
        RECT  0 44.016 0.084 44.04 ;
    END
  END b[251]
  PIN b[252]
    DIRECTION OUTPUT ;
    USE SIGNAL ;
    PORT
      LAYER M4 ;
        RECT  0 44.112 0.084 44.136 ;
    END
  END b[252]
  PIN b[253]
    DIRECTION OUTPUT ;
    USE SIGNAL ;
    PORT
      LAYER M4 ;
        RECT  0 44.208 0.084 44.232 ;
    END
  END b[253]
  PIN b[254]
    DIRECTION OUTPUT ;
    USE SIGNAL ;
    PORT
      LAYER M4 ;
        RECT  0 44.304 0.084 44.328 ;
    END
  END b[254]
  PIN b[255]
    DIRECTION OUTPUT ;
    USE SIGNAL ;
    PORT
      LAYER M4 ;
        RECT  0 44.4 0.084 44.424 ;
    END
  END b[255]
  PIN b[256]
    DIRECTION OUTPUT ;
    USE SIGNAL ;
    PORT
      LAYER M4 ;
        RECT  0 29.136 0.084 29.16 ;
    END
  END b[256]
  PIN b[257]
    DIRECTION OUTPUT ;
    USE SIGNAL ;
    PORT
      LAYER M4 ;
        RECT  0 29.232 0.084 29.256 ;
    END
  END b[257]
  PIN b[258]
    DIRECTION OUTPUT ;
    USE SIGNAL ;
    PORT
      LAYER M4 ;
        RECT  0 29.328 0.084 29.352 ;
    END
  END b[258]
  PIN b[259]
    DIRECTION OUTPUT ;
    USE SIGNAL ;
    PORT
      LAYER M4 ;
        RECT  0 29.424 0.084 29.448 ;
    END
  END b[259]
  PIN b[25]
    DIRECTION OUTPUT ;
    USE SIGNAL ;
    PORT
      LAYER M4 ;
        RECT  0 50.736 0.084 50.76 ;
    END
  END b[25]
  PIN b[260]
    DIRECTION OUTPUT ;
    USE SIGNAL ;
    PORT
      LAYER M4 ;
        RECT  0 29.52 0.084 29.544 ;
    END
  END b[260]
  PIN b[261]
    DIRECTION OUTPUT ;
    USE SIGNAL ;
    PORT
      LAYER M4 ;
        RECT  0 29.616 0.084 29.64 ;
    END
  END b[261]
  PIN b[262]
    DIRECTION OUTPUT ;
    USE SIGNAL ;
    PORT
      LAYER M4 ;
        RECT  0 29.712 0.084 29.736 ;
    END
  END b[262]
  PIN b[263]
    DIRECTION OUTPUT ;
    USE SIGNAL ;
    PORT
      LAYER M4 ;
        RECT  0 29.808 0.084 29.832 ;
    END
  END b[263]
  PIN b[264]
    DIRECTION OUTPUT ;
    USE SIGNAL ;
    PORT
      LAYER M4 ;
        RECT  0 29.904 0.084 29.928 ;
    END
  END b[264]
  PIN b[265]
    DIRECTION OUTPUT ;
    USE SIGNAL ;
    PORT
      LAYER M4 ;
        RECT  0 30 0.084 30.024 ;
    END
  END b[265]
  PIN b[266]
    DIRECTION OUTPUT ;
    USE SIGNAL ;
    PORT
      LAYER M4 ;
        RECT  0 30.096 0.084 30.12 ;
    END
  END b[266]
  PIN b[267]
    DIRECTION OUTPUT ;
    USE SIGNAL ;
    PORT
      LAYER M4 ;
        RECT  0 30.192 0.084 30.216 ;
    END
  END b[267]
  PIN b[268]
    DIRECTION OUTPUT ;
    USE SIGNAL ;
    PORT
      LAYER M4 ;
        RECT  0 30.288 0.084 30.312 ;
    END
  END b[268]
  PIN b[269]
    DIRECTION OUTPUT ;
    USE SIGNAL ;
    PORT
      LAYER M4 ;
        RECT  0 30.384 0.084 30.408 ;
    END
  END b[269]
  PIN b[26]
    DIRECTION OUTPUT ;
    USE SIGNAL ;
    PORT
      LAYER M4 ;
        RECT  0 50.832 0.084 50.856 ;
    END
  END b[26]
  PIN b[270]
    DIRECTION OUTPUT ;
    USE SIGNAL ;
    PORT
      LAYER M4 ;
        RECT  0 30.48 0.084 30.504 ;
    END
  END b[270]
  PIN b[271]
    DIRECTION OUTPUT ;
    USE SIGNAL ;
    PORT
      LAYER M4 ;
        RECT  0 30.576 0.084 30.6 ;
    END
  END b[271]
  PIN b[272]
    DIRECTION OUTPUT ;
    USE SIGNAL ;
    PORT
      LAYER M4 ;
        RECT  0 30.672 0.084 30.696 ;
    END
  END b[272]
  PIN b[273]
    DIRECTION OUTPUT ;
    USE SIGNAL ;
    PORT
      LAYER M4 ;
        RECT  0 30.768 0.084 30.792 ;
    END
  END b[273]
  PIN b[274]
    DIRECTION OUTPUT ;
    USE SIGNAL ;
    PORT
      LAYER M4 ;
        RECT  0 30.864 0.084 30.888 ;
    END
  END b[274]
  PIN b[275]
    DIRECTION OUTPUT ;
    USE SIGNAL ;
    PORT
      LAYER M4 ;
        RECT  0 30.96 0.084 30.984 ;
    END
  END b[275]
  PIN b[276]
    DIRECTION OUTPUT ;
    USE SIGNAL ;
    PORT
      LAYER M4 ;
        RECT  0 31.056 0.084 31.08 ;
    END
  END b[276]
  PIN b[277]
    DIRECTION OUTPUT ;
    USE SIGNAL ;
    PORT
      LAYER M4 ;
        RECT  0 31.152 0.084 31.176 ;
    END
  END b[277]
  PIN b[278]
    DIRECTION OUTPUT ;
    USE SIGNAL ;
    PORT
      LAYER M4 ;
        RECT  0 31.248 0.084 31.272 ;
    END
  END b[278]
  PIN b[279]
    DIRECTION OUTPUT ;
    USE SIGNAL ;
    PORT
      LAYER M4 ;
        RECT  0 31.344 0.084 31.368 ;
    END
  END b[279]
  PIN b[27]
    DIRECTION OUTPUT ;
    USE SIGNAL ;
    PORT
      LAYER M4 ;
        RECT  0 50.928 0.084 50.952 ;
    END
  END b[27]
  PIN b[280]
    DIRECTION OUTPUT ;
    USE SIGNAL ;
    PORT
      LAYER M4 ;
        RECT  0 31.44 0.084 31.464 ;
    END
  END b[280]
  PIN b[281]
    DIRECTION OUTPUT ;
    USE SIGNAL ;
    PORT
      LAYER M4 ;
        RECT  0 31.536 0.084 31.56 ;
    END
  END b[281]
  PIN b[282]
    DIRECTION OUTPUT ;
    USE SIGNAL ;
    PORT
      LAYER M4 ;
        RECT  0 31.632 0.084 31.656 ;
    END
  END b[282]
  PIN b[283]
    DIRECTION OUTPUT ;
    USE SIGNAL ;
    PORT
      LAYER M4 ;
        RECT  0 31.728 0.084 31.752 ;
    END
  END b[283]
  PIN b[284]
    DIRECTION OUTPUT ;
    USE SIGNAL ;
    PORT
      LAYER M4 ;
        RECT  0 31.824 0.084 31.848 ;
    END
  END b[284]
  PIN b[285]
    DIRECTION OUTPUT ;
    USE SIGNAL ;
    PORT
      LAYER M4 ;
        RECT  0 31.92 0.084 31.944 ;
    END
  END b[285]
  PIN b[286]
    DIRECTION OUTPUT ;
    USE SIGNAL ;
    PORT
      LAYER M4 ;
        RECT  0 32.016 0.084 32.04 ;
    END
  END b[286]
  PIN b[287]
    DIRECTION OUTPUT ;
    USE SIGNAL ;
    PORT
      LAYER M4 ;
        RECT  0 32.112 0.084 32.136 ;
    END
  END b[287]
  PIN b[288]
    DIRECTION OUTPUT ;
    USE SIGNAL ;
    PORT
      LAYER M4 ;
        RECT  0 44.496 0.084 44.52 ;
    END
  END b[288]
  PIN b[289]
    DIRECTION OUTPUT ;
    USE SIGNAL ;
    PORT
      LAYER M4 ;
        RECT  0 44.592 0.084 44.616 ;
    END
  END b[289]
  PIN b[28]
    DIRECTION OUTPUT ;
    USE SIGNAL ;
    PORT
      LAYER M4 ;
        RECT  0 51.024 0.084 51.048 ;
    END
  END b[28]
  PIN b[290]
    DIRECTION OUTPUT ;
    USE SIGNAL ;
    PORT
      LAYER M4 ;
        RECT  0 44.688 0.084 44.712 ;
    END
  END b[290]
  PIN b[291]
    DIRECTION OUTPUT ;
    USE SIGNAL ;
    PORT
      LAYER M4 ;
        RECT  0 44.784 0.084 44.808 ;
    END
  END b[291]
  PIN b[292]
    DIRECTION OUTPUT ;
    USE SIGNAL ;
    PORT
      LAYER M4 ;
        RECT  0 44.88 0.084 44.904 ;
    END
  END b[292]
  PIN b[293]
    DIRECTION OUTPUT ;
    USE SIGNAL ;
    PORT
      LAYER M4 ;
        RECT  0 44.976 0.084 45 ;
    END
  END b[293]
  PIN b[294]
    DIRECTION OUTPUT ;
    USE SIGNAL ;
    PORT
      LAYER M4 ;
        RECT  0 45.072 0.084 45.096 ;
    END
  END b[294]
  PIN b[295]
    DIRECTION OUTPUT ;
    USE SIGNAL ;
    PORT
      LAYER M4 ;
        RECT  0 45.168 0.084 45.192 ;
    END
  END b[295]
  PIN b[296]
    DIRECTION OUTPUT ;
    USE SIGNAL ;
    PORT
      LAYER M4 ;
        RECT  0 45.264 0.084 45.288 ;
    END
  END b[296]
  PIN b[297]
    DIRECTION OUTPUT ;
    USE SIGNAL ;
    PORT
      LAYER M4 ;
        RECT  0 45.36 0.084 45.384 ;
    END
  END b[297]
  PIN b[298]
    DIRECTION OUTPUT ;
    USE SIGNAL ;
    PORT
      LAYER M4 ;
        RECT  0 45.456 0.084 45.48 ;
    END
  END b[298]
  PIN b[299]
    DIRECTION OUTPUT ;
    USE SIGNAL ;
    PORT
      LAYER M4 ;
        RECT  0 45.552 0.084 45.576 ;
    END
  END b[299]
  PIN b[29]
    DIRECTION OUTPUT ;
    USE SIGNAL ;
    PORT
      LAYER M4 ;
        RECT  0 51.12 0.084 51.144 ;
    END
  END b[29]
  PIN b[2]
    DIRECTION OUTPUT ;
    USE SIGNAL ;
    PORT
      LAYER M4 ;
        RECT  0 48.528 0.084 48.552 ;
    END
  END b[2]
  PIN b[300]
    DIRECTION OUTPUT ;
    USE SIGNAL ;
    PORT
      LAYER M4 ;
        RECT  0 45.648 0.084 45.672 ;
    END
  END b[300]
  PIN b[301]
    DIRECTION OUTPUT ;
    USE SIGNAL ;
    PORT
      LAYER M4 ;
        RECT  0 45.744 0.084 45.768 ;
    END
  END b[301]
  PIN b[302]
    DIRECTION OUTPUT ;
    USE SIGNAL ;
    PORT
      LAYER M4 ;
        RECT  0 45.84 0.084 45.864 ;
    END
  END b[302]
  PIN b[303]
    DIRECTION OUTPUT ;
    USE SIGNAL ;
    PORT
      LAYER M4 ;
        RECT  0 45.936 0.084 45.96 ;
    END
  END b[303]
  PIN b[304]
    DIRECTION OUTPUT ;
    USE SIGNAL ;
    PORT
      LAYER M4 ;
        RECT  0 46.032 0.084 46.056 ;
    END
  END b[304]
  PIN b[305]
    DIRECTION OUTPUT ;
    USE SIGNAL ;
    PORT
      LAYER M4 ;
        RECT  0 46.128 0.084 46.152 ;
    END
  END b[305]
  PIN b[306]
    DIRECTION OUTPUT ;
    USE SIGNAL ;
    PORT
      LAYER M4 ;
        RECT  0 46.224 0.084 46.248 ;
    END
  END b[306]
  PIN b[307]
    DIRECTION OUTPUT ;
    USE SIGNAL ;
    PORT
      LAYER M4 ;
        RECT  0 46.32 0.084 46.344 ;
    END
  END b[307]
  PIN b[308]
    DIRECTION OUTPUT ;
    USE SIGNAL ;
    PORT
      LAYER M4 ;
        RECT  0 46.416 0.084 46.44 ;
    END
  END b[308]
  PIN b[309]
    DIRECTION OUTPUT ;
    USE SIGNAL ;
    PORT
      LAYER M4 ;
        RECT  0 46.512 0.084 46.536 ;
    END
  END b[309]
  PIN b[30]
    DIRECTION OUTPUT ;
    USE SIGNAL ;
    PORT
      LAYER M4 ;
        RECT  0 51.216 0.084 51.24 ;
    END
  END b[30]
  PIN b[310]
    DIRECTION OUTPUT ;
    USE SIGNAL ;
    PORT
      LAYER M4 ;
        RECT  0 46.608 0.084 46.632 ;
    END
  END b[310]
  PIN b[311]
    DIRECTION OUTPUT ;
    USE SIGNAL ;
    PORT
      LAYER M4 ;
        RECT  0 46.704 0.084 46.728 ;
    END
  END b[311]
  PIN b[312]
    DIRECTION OUTPUT ;
    USE SIGNAL ;
    PORT
      LAYER M4 ;
        RECT  0 46.8 0.084 46.824 ;
    END
  END b[312]
  PIN b[313]
    DIRECTION OUTPUT ;
    USE SIGNAL ;
    PORT
      LAYER M4 ;
        RECT  0 46.896 0.084 46.92 ;
    END
  END b[313]
  PIN b[314]
    DIRECTION OUTPUT ;
    USE SIGNAL ;
    PORT
      LAYER M4 ;
        RECT  0 46.992 0.084 47.016 ;
    END
  END b[314]
  PIN b[315]
    DIRECTION OUTPUT ;
    USE SIGNAL ;
    PORT
      LAYER M4 ;
        RECT  0 47.088 0.084 47.112 ;
    END
  END b[315]
  PIN b[316]
    DIRECTION OUTPUT ;
    USE SIGNAL ;
    PORT
      LAYER M4 ;
        RECT  0 47.184 0.084 47.208 ;
    END
  END b[316]
  PIN b[317]
    DIRECTION OUTPUT ;
    USE SIGNAL ;
    PORT
      LAYER M4 ;
        RECT  0 47.28 0.084 47.304 ;
    END
  END b[317]
  PIN b[318]
    DIRECTION OUTPUT ;
    USE SIGNAL ;
    PORT
      LAYER M4 ;
        RECT  0 47.376 0.084 47.4 ;
    END
  END b[318]
  PIN b[319]
    DIRECTION OUTPUT ;
    USE SIGNAL ;
    PORT
      LAYER M4 ;
        RECT  0 47.472 0.084 47.496 ;
    END
  END b[319]
  PIN b[31]
    DIRECTION OUTPUT ;
    USE SIGNAL ;
    PORT
      LAYER M4 ;
        RECT  0 51.312 0.084 51.336 ;
    END
  END b[31]
  PIN b[320]
    DIRECTION OUTPUT ;
    USE SIGNAL ;
    PORT
      LAYER M4 ;
        RECT  0 35.28 0.084 35.304 ;
    END
  END b[320]
  PIN b[321]
    DIRECTION OUTPUT ;
    USE SIGNAL ;
    PORT
      LAYER M4 ;
        RECT  0 35.376 0.084 35.4 ;
    END
  END b[321]
  PIN b[322]
    DIRECTION OUTPUT ;
    USE SIGNAL ;
    PORT
      LAYER M4 ;
        RECT  0 35.472 0.084 35.496 ;
    END
  END b[322]
  PIN b[323]
    DIRECTION OUTPUT ;
    USE SIGNAL ;
    PORT
      LAYER M4 ;
        RECT  0 35.568 0.084 35.592 ;
    END
  END b[323]
  PIN b[324]
    DIRECTION OUTPUT ;
    USE SIGNAL ;
    PORT
      LAYER M4 ;
        RECT  0 35.664 0.084 35.688 ;
    END
  END b[324]
  PIN b[325]
    DIRECTION OUTPUT ;
    USE SIGNAL ;
    PORT
      LAYER M4 ;
        RECT  0 35.76 0.084 35.784 ;
    END
  END b[325]
  PIN b[326]
    DIRECTION OUTPUT ;
    USE SIGNAL ;
    PORT
      LAYER M4 ;
        RECT  0 35.856 0.084 35.88 ;
    END
  END b[326]
  PIN b[327]
    DIRECTION OUTPUT ;
    USE SIGNAL ;
    PORT
      LAYER M4 ;
        RECT  0 35.952 0.084 35.976 ;
    END
  END b[327]
  PIN b[328]
    DIRECTION OUTPUT ;
    USE SIGNAL ;
    PORT
      LAYER M4 ;
        RECT  0 36.048 0.084 36.072 ;
    END
  END b[328]
  PIN b[329]
    DIRECTION OUTPUT ;
    USE SIGNAL ;
    PORT
      LAYER M4 ;
        RECT  0 36.144 0.084 36.168 ;
    END
  END b[329]
  PIN b[32]
    DIRECTION OUTPUT ;
    USE SIGNAL ;
    PORT
      LAYER M4 ;
        RECT  0 60.624 0.084 60.648 ;
    END
  END b[32]
  PIN b[330]
    DIRECTION OUTPUT ;
    USE SIGNAL ;
    PORT
      LAYER M4 ;
        RECT  0 36.24 0.084 36.264 ;
    END
  END b[330]
  PIN b[331]
    DIRECTION OUTPUT ;
    USE SIGNAL ;
    PORT
      LAYER M4 ;
        RECT  0 36.336 0.084 36.36 ;
    END
  END b[331]
  PIN b[332]
    DIRECTION OUTPUT ;
    USE SIGNAL ;
    PORT
      LAYER M4 ;
        RECT  0 36.432 0.084 36.456 ;
    END
  END b[332]
  PIN b[333]
    DIRECTION OUTPUT ;
    USE SIGNAL ;
    PORT
      LAYER M4 ;
        RECT  0 36.528 0.084 36.552 ;
    END
  END b[333]
  PIN b[334]
    DIRECTION OUTPUT ;
    USE SIGNAL ;
    PORT
      LAYER M4 ;
        RECT  0 36.624 0.084 36.648 ;
    END
  END b[334]
  PIN b[335]
    DIRECTION OUTPUT ;
    USE SIGNAL ;
    PORT
      LAYER M4 ;
        RECT  0 36.72 0.084 36.744 ;
    END
  END b[335]
  PIN b[336]
    DIRECTION OUTPUT ;
    USE SIGNAL ;
    PORT
      LAYER M4 ;
        RECT  0 36.816 0.084 36.84 ;
    END
  END b[336]
  PIN b[337]
    DIRECTION OUTPUT ;
    USE SIGNAL ;
    PORT
      LAYER M4 ;
        RECT  0 36.912 0.084 36.936 ;
    END
  END b[337]
  PIN b[338]
    DIRECTION OUTPUT ;
    USE SIGNAL ;
    PORT
      LAYER M4 ;
        RECT  0 37.008 0.084 37.032 ;
    END
  END b[338]
  PIN b[339]
    DIRECTION OUTPUT ;
    USE SIGNAL ;
    PORT
      LAYER M4 ;
        RECT  0 37.104 0.084 37.128 ;
    END
  END b[339]
  PIN b[33]
    DIRECTION OUTPUT ;
    USE SIGNAL ;
    PORT
      LAYER M4 ;
        RECT  0 60.72 0.084 60.744 ;
    END
  END b[33]
  PIN b[340]
    DIRECTION OUTPUT ;
    USE SIGNAL ;
    PORT
      LAYER M4 ;
        RECT  0 37.2 0.084 37.224 ;
    END
  END b[340]
  PIN b[341]
    DIRECTION OUTPUT ;
    USE SIGNAL ;
    PORT
      LAYER M4 ;
        RECT  0 37.296 0.084 37.32 ;
    END
  END b[341]
  PIN b[342]
    DIRECTION OUTPUT ;
    USE SIGNAL ;
    PORT
      LAYER M4 ;
        RECT  0 37.392 0.084 37.416 ;
    END
  END b[342]
  PIN b[343]
    DIRECTION OUTPUT ;
    USE SIGNAL ;
    PORT
      LAYER M4 ;
        RECT  0 37.488 0.084 37.512 ;
    END
  END b[343]
  PIN b[344]
    DIRECTION OUTPUT ;
    USE SIGNAL ;
    PORT
      LAYER M4 ;
        RECT  0 37.584 0.084 37.608 ;
    END
  END b[344]
  PIN b[345]
    DIRECTION OUTPUT ;
    USE SIGNAL ;
    PORT
      LAYER M4 ;
        RECT  0 37.68 0.084 37.704 ;
    END
  END b[345]
  PIN b[346]
    DIRECTION OUTPUT ;
    USE SIGNAL ;
    PORT
      LAYER M4 ;
        RECT  0 37.776 0.084 37.8 ;
    END
  END b[346]
  PIN b[347]
    DIRECTION OUTPUT ;
    USE SIGNAL ;
    PORT
      LAYER M4 ;
        RECT  0 37.872 0.084 37.896 ;
    END
  END b[347]
  PIN b[348]
    DIRECTION OUTPUT ;
    USE SIGNAL ;
    PORT
      LAYER M4 ;
        RECT  0 37.968 0.084 37.992 ;
    END
  END b[348]
  PIN b[349]
    DIRECTION OUTPUT ;
    USE SIGNAL ;
    PORT
      LAYER M4 ;
        RECT  0 38.064 0.084 38.088 ;
    END
  END b[349]
  PIN b[34]
    DIRECTION OUTPUT ;
    USE SIGNAL ;
    PORT
      LAYER M4 ;
        RECT  0 60.816 0.084 60.84 ;
    END
  END b[34]
  PIN b[350]
    DIRECTION OUTPUT ;
    USE SIGNAL ;
    PORT
      LAYER M4 ;
        RECT  0 38.16 0.084 38.184 ;
    END
  END b[350]
  PIN b[351]
    DIRECTION OUTPUT ;
    USE SIGNAL ;
    PORT
      LAYER M4 ;
        RECT  0 38.256 0.084 38.28 ;
    END
  END b[351]
  PIN b[352]
    DIRECTION OUTPUT ;
    USE SIGNAL ;
    PORT
      LAYER M4 ;
        RECT  0 38.352 0.084 38.376 ;
    END
  END b[352]
  PIN b[353]
    DIRECTION OUTPUT ;
    USE SIGNAL ;
    PORT
      LAYER M4 ;
        RECT  0 38.448 0.084 38.472 ;
    END
  END b[353]
  PIN b[354]
    DIRECTION OUTPUT ;
    USE SIGNAL ;
    PORT
      LAYER M4 ;
        RECT  0 38.544 0.084 38.568 ;
    END
  END b[354]
  PIN b[355]
    DIRECTION OUTPUT ;
    USE SIGNAL ;
    PORT
      LAYER M4 ;
        RECT  0 38.64 0.084 38.664 ;
    END
  END b[355]
  PIN b[356]
    DIRECTION OUTPUT ;
    USE SIGNAL ;
    PORT
      LAYER M4 ;
        RECT  0 38.736 0.084 38.76 ;
    END
  END b[356]
  PIN b[357]
    DIRECTION OUTPUT ;
    USE SIGNAL ;
    PORT
      LAYER M4 ;
        RECT  0 38.832 0.084 38.856 ;
    END
  END b[357]
  PIN b[358]
    DIRECTION OUTPUT ;
    USE SIGNAL ;
    PORT
      LAYER M4 ;
        RECT  0 38.928 0.084 38.952 ;
    END
  END b[358]
  PIN b[359]
    DIRECTION OUTPUT ;
    USE SIGNAL ;
    PORT
      LAYER M4 ;
        RECT  0 39.024 0.084 39.048 ;
    END
  END b[359]
  PIN b[35]
    DIRECTION OUTPUT ;
    USE SIGNAL ;
    PORT
      LAYER M4 ;
        RECT  0 60.912 0.084 60.936 ;
    END
  END b[35]
  PIN b[360]
    DIRECTION OUTPUT ;
    USE SIGNAL ;
    PORT
      LAYER M4 ;
        RECT  0 39.12 0.084 39.144 ;
    END
  END b[360]
  PIN b[361]
    DIRECTION OUTPUT ;
    USE SIGNAL ;
    PORT
      LAYER M4 ;
        RECT  0 39.216 0.084 39.24 ;
    END
  END b[361]
  PIN b[362]
    DIRECTION OUTPUT ;
    USE SIGNAL ;
    PORT
      LAYER M4 ;
        RECT  0 39.312 0.084 39.336 ;
    END
  END b[362]
  PIN b[363]
    DIRECTION OUTPUT ;
    USE SIGNAL ;
    PORT
      LAYER M4 ;
        RECT  0 39.408 0.084 39.432 ;
    END
  END b[363]
  PIN b[364]
    DIRECTION OUTPUT ;
    USE SIGNAL ;
    PORT
      LAYER M4 ;
        RECT  0 39.504 0.084 39.528 ;
    END
  END b[364]
  PIN b[365]
    DIRECTION OUTPUT ;
    USE SIGNAL ;
    PORT
      LAYER M4 ;
        RECT  0 39.6 0.084 39.624 ;
    END
  END b[365]
  PIN b[366]
    DIRECTION OUTPUT ;
    USE SIGNAL ;
    PORT
      LAYER M4 ;
        RECT  0 39.696 0.084 39.72 ;
    END
  END b[366]
  PIN b[367]
    DIRECTION OUTPUT ;
    USE SIGNAL ;
    PORT
      LAYER M4 ;
        RECT  0 39.792 0.084 39.816 ;
    END
  END b[367]
  PIN b[368]
    DIRECTION OUTPUT ;
    USE SIGNAL ;
    PORT
      LAYER M4 ;
        RECT  0 39.888 0.084 39.912 ;
    END
  END b[368]
  PIN b[369]
    DIRECTION OUTPUT ;
    USE SIGNAL ;
    PORT
      LAYER M4 ;
        RECT  0 39.984 0.084 40.008 ;
    END
  END b[369]
  PIN b[36]
    DIRECTION OUTPUT ;
    USE SIGNAL ;
    PORT
      LAYER M4 ;
        RECT  0 61.008 0.084 61.032 ;
    END
  END b[36]
  PIN b[370]
    DIRECTION OUTPUT ;
    USE SIGNAL ;
    PORT
      LAYER M4 ;
        RECT  0 40.08 0.084 40.104 ;
    END
  END b[370]
  PIN b[371]
    DIRECTION OUTPUT ;
    USE SIGNAL ;
    PORT
      LAYER M4 ;
        RECT  0 40.176 0.084 40.2 ;
    END
  END b[371]
  PIN b[372]
    DIRECTION OUTPUT ;
    USE SIGNAL ;
    PORT
      LAYER M4 ;
        RECT  0 40.272 0.084 40.296 ;
    END
  END b[372]
  PIN b[373]
    DIRECTION OUTPUT ;
    USE SIGNAL ;
    PORT
      LAYER M4 ;
        RECT  0 40.368 0.084 40.392 ;
    END
  END b[373]
  PIN b[374]
    DIRECTION OUTPUT ;
    USE SIGNAL ;
    PORT
      LAYER M4 ;
        RECT  0 40.464 0.084 40.488 ;
    END
  END b[374]
  PIN b[375]
    DIRECTION OUTPUT ;
    USE SIGNAL ;
    PORT
      LAYER M4 ;
        RECT  0 40.56 0.084 40.584 ;
    END
  END b[375]
  PIN b[376]
    DIRECTION OUTPUT ;
    USE SIGNAL ;
    PORT
      LAYER M4 ;
        RECT  0 40.656 0.084 40.68 ;
    END
  END b[376]
  PIN b[377]
    DIRECTION OUTPUT ;
    USE SIGNAL ;
    PORT
      LAYER M4 ;
        RECT  0 40.752 0.084 40.776 ;
    END
  END b[377]
  PIN b[378]
    DIRECTION OUTPUT ;
    USE SIGNAL ;
    PORT
      LAYER M4 ;
        RECT  0 40.848 0.084 40.872 ;
    END
  END b[378]
  PIN b[379]
    DIRECTION OUTPUT ;
    USE SIGNAL ;
    PORT
      LAYER M4 ;
        RECT  0 40.944 0.084 40.968 ;
    END
  END b[379]
  PIN b[37]
    DIRECTION OUTPUT ;
    USE SIGNAL ;
    PORT
      LAYER M4 ;
        RECT  0 61.104 0.084 61.128 ;
    END
  END b[37]
  PIN b[380]
    DIRECTION OUTPUT ;
    USE SIGNAL ;
    PORT
      LAYER M4 ;
        RECT  0 41.04 0.084 41.064 ;
    END
  END b[380]
  PIN b[381]
    DIRECTION OUTPUT ;
    USE SIGNAL ;
    PORT
      LAYER M4 ;
        RECT  0 41.136 0.084 41.16 ;
    END
  END b[381]
  PIN b[382]
    DIRECTION OUTPUT ;
    USE SIGNAL ;
    PORT
      LAYER M4 ;
        RECT  0 41.232 0.084 41.256 ;
    END
  END b[382]
  PIN b[383]
    DIRECTION OUTPUT ;
    USE SIGNAL ;
    PORT
      LAYER M4 ;
        RECT  0 41.328 0.084 41.352 ;
    END
  END b[383]
  PIN b[384]
    DIRECTION OUTPUT ;
    USE SIGNAL ;
    PORT
      LAYER M4 ;
        RECT  0 73.68 0.084 73.704 ;
    END
  END b[384]
  PIN b[385]
    DIRECTION OUTPUT ;
    USE SIGNAL ;
    PORT
      LAYER M4 ;
        RECT  0 73.776 0.084 73.8 ;
    END
  END b[385]
  PIN b[386]
    DIRECTION OUTPUT ;
    USE SIGNAL ;
    PORT
      LAYER M4 ;
        RECT  0 73.872 0.084 73.896 ;
    END
  END b[386]
  PIN b[387]
    DIRECTION OUTPUT ;
    USE SIGNAL ;
    PORT
      LAYER M4 ;
        RECT  0 73.968 0.084 73.992 ;
    END
  END b[387]
  PIN b[388]
    DIRECTION OUTPUT ;
    USE SIGNAL ;
    PORT
      LAYER M4 ;
        RECT  0 74.064 0.084 74.088 ;
    END
  END b[388]
  PIN b[389]
    DIRECTION OUTPUT ;
    USE SIGNAL ;
    PORT
      LAYER M4 ;
        RECT  0 74.16 0.084 74.184 ;
    END
  END b[389]
  PIN b[38]
    DIRECTION OUTPUT ;
    USE SIGNAL ;
    PORT
      LAYER M4 ;
        RECT  0 61.2 0.084 61.224 ;
    END
  END b[38]
  PIN b[390]
    DIRECTION OUTPUT ;
    USE SIGNAL ;
    PORT
      LAYER M4 ;
        RECT  0 74.256 0.084 74.28 ;
    END
  END b[390]
  PIN b[391]
    DIRECTION OUTPUT ;
    USE SIGNAL ;
    PORT
      LAYER M4 ;
        RECT  0 74.352 0.084 74.376 ;
    END
  END b[391]
  PIN b[392]
    DIRECTION OUTPUT ;
    USE SIGNAL ;
    PORT
      LAYER M4 ;
        RECT  0 74.448 0.084 74.472 ;
    END
  END b[392]
  PIN b[393]
    DIRECTION OUTPUT ;
    USE SIGNAL ;
    PORT
      LAYER M4 ;
        RECT  0 74.544 0.084 74.568 ;
    END
  END b[393]
  PIN b[394]
    DIRECTION OUTPUT ;
    USE SIGNAL ;
    PORT
      LAYER M4 ;
        RECT  0 74.64 0.084 74.664 ;
    END
  END b[394]
  PIN b[395]
    DIRECTION OUTPUT ;
    USE SIGNAL ;
    PORT
      LAYER M4 ;
        RECT  0 74.736 0.084 74.76 ;
    END
  END b[395]
  PIN b[396]
    DIRECTION OUTPUT ;
    USE SIGNAL ;
    PORT
      LAYER M4 ;
        RECT  0 74.832 0.084 74.856 ;
    END
  END b[396]
  PIN b[397]
    DIRECTION OUTPUT ;
    USE SIGNAL ;
    PORT
      LAYER M4 ;
        RECT  0 74.928 0.084 74.952 ;
    END
  END b[397]
  PIN b[398]
    DIRECTION OUTPUT ;
    USE SIGNAL ;
    PORT
      LAYER M4 ;
        RECT  0 75.024 0.084 75.048 ;
    END
  END b[398]
  PIN b[399]
    DIRECTION OUTPUT ;
    USE SIGNAL ;
    PORT
      LAYER M4 ;
        RECT  0 75.12 0.084 75.144 ;
    END
  END b[399]
  PIN b[39]
    DIRECTION OUTPUT ;
    USE SIGNAL ;
    PORT
      LAYER M4 ;
        RECT  0 61.296 0.084 61.32 ;
    END
  END b[39]
  PIN b[3]
    DIRECTION OUTPUT ;
    USE SIGNAL ;
    PORT
      LAYER M4 ;
        RECT  0 48.624 0.084 48.648 ;
    END
  END b[3]
  PIN b[400]
    DIRECTION OUTPUT ;
    USE SIGNAL ;
    PORT
      LAYER M4 ;
        RECT  0 75.216 0.084 75.24 ;
    END
  END b[400]
  PIN b[401]
    DIRECTION OUTPUT ;
    USE SIGNAL ;
    PORT
      LAYER M4 ;
        RECT  0 75.312 0.084 75.336 ;
    END
  END b[401]
  PIN b[402]
    DIRECTION OUTPUT ;
    USE SIGNAL ;
    PORT
      LAYER M4 ;
        RECT  0 75.408 0.084 75.432 ;
    END
  END b[402]
  PIN b[403]
    DIRECTION OUTPUT ;
    USE SIGNAL ;
    PORT
      LAYER M4 ;
        RECT  0 75.504 0.084 75.528 ;
    END
  END b[403]
  PIN b[404]
    DIRECTION OUTPUT ;
    USE SIGNAL ;
    PORT
      LAYER M4 ;
        RECT  0 75.6 0.084 75.624 ;
    END
  END b[404]
  PIN b[405]
    DIRECTION OUTPUT ;
    USE SIGNAL ;
    PORT
      LAYER M4 ;
        RECT  0 75.696 0.084 75.72 ;
    END
  END b[405]
  PIN b[406]
    DIRECTION OUTPUT ;
    USE SIGNAL ;
    PORT
      LAYER M4 ;
        RECT  0 75.792 0.084 75.816 ;
    END
  END b[406]
  PIN b[407]
    DIRECTION OUTPUT ;
    USE SIGNAL ;
    PORT
      LAYER M4 ;
        RECT  0 75.888 0.084 75.912 ;
    END
  END b[407]
  PIN b[408]
    DIRECTION OUTPUT ;
    USE SIGNAL ;
    PORT
      LAYER M4 ;
        RECT  0 75.984 0.084 76.008 ;
    END
  END b[408]
  PIN b[409]
    DIRECTION OUTPUT ;
    USE SIGNAL ;
    PORT
      LAYER M4 ;
        RECT  0 76.08 0.084 76.104 ;
    END
  END b[409]
  PIN b[40]
    DIRECTION OUTPUT ;
    USE SIGNAL ;
    PORT
      LAYER M4 ;
        RECT  0 61.392 0.084 61.416 ;
    END
  END b[40]
  PIN b[410]
    DIRECTION OUTPUT ;
    USE SIGNAL ;
    PORT
      LAYER M4 ;
        RECT  0 76.176 0.084 76.2 ;
    END
  END b[410]
  PIN b[411]
    DIRECTION OUTPUT ;
    USE SIGNAL ;
    PORT
      LAYER M4 ;
        RECT  0 76.272 0.084 76.296 ;
    END
  END b[411]
  PIN b[412]
    DIRECTION OUTPUT ;
    USE SIGNAL ;
    PORT
      LAYER M4 ;
        RECT  0 76.368 0.084 76.392 ;
    END
  END b[412]
  PIN b[413]
    DIRECTION OUTPUT ;
    USE SIGNAL ;
    PORT
      LAYER M4 ;
        RECT  0 76.464 0.084 76.488 ;
    END
  END b[413]
  PIN b[414]
    DIRECTION OUTPUT ;
    USE SIGNAL ;
    PORT
      LAYER M4 ;
        RECT  0 76.56 0.084 76.584 ;
    END
  END b[414]
  PIN b[415]
    DIRECTION OUTPUT ;
    USE SIGNAL ;
    PORT
      LAYER M4 ;
        RECT  0 76.656 0.084 76.68 ;
    END
  END b[415]
  PIN b[416]
    DIRECTION OUTPUT ;
    USE SIGNAL ;
    PORT
      LAYER M4 ;
        RECT  0 70.608 0.084 70.632 ;
    END
  END b[416]
  PIN b[417]
    DIRECTION OUTPUT ;
    USE SIGNAL ;
    PORT
      LAYER M4 ;
        RECT  0 70.704 0.084 70.728 ;
    END
  END b[417]
  PIN b[418]
    DIRECTION OUTPUT ;
    USE SIGNAL ;
    PORT
      LAYER M4 ;
        RECT  0 70.8 0.084 70.824 ;
    END
  END b[418]
  PIN b[419]
    DIRECTION OUTPUT ;
    USE SIGNAL ;
    PORT
      LAYER M4 ;
        RECT  0 70.896 0.084 70.92 ;
    END
  END b[419]
  PIN b[41]
    DIRECTION OUTPUT ;
    USE SIGNAL ;
    PORT
      LAYER M4 ;
        RECT  0 61.488 0.084 61.512 ;
    END
  END b[41]
  PIN b[420]
    DIRECTION OUTPUT ;
    USE SIGNAL ;
    PORT
      LAYER M4 ;
        RECT  0 70.992 0.084 71.016 ;
    END
  END b[420]
  PIN b[421]
    DIRECTION OUTPUT ;
    USE SIGNAL ;
    PORT
      LAYER M4 ;
        RECT  0 71.088 0.084 71.112 ;
    END
  END b[421]
  PIN b[422]
    DIRECTION OUTPUT ;
    USE SIGNAL ;
    PORT
      LAYER M4 ;
        RECT  0 71.184 0.084 71.208 ;
    END
  END b[422]
  PIN b[423]
    DIRECTION OUTPUT ;
    USE SIGNAL ;
    PORT
      LAYER M4 ;
        RECT  0 71.28 0.084 71.304 ;
    END
  END b[423]
  PIN b[424]
    DIRECTION OUTPUT ;
    USE SIGNAL ;
    PORT
      LAYER M4 ;
        RECT  0 71.376 0.084 71.4 ;
    END
  END b[424]
  PIN b[425]
    DIRECTION OUTPUT ;
    USE SIGNAL ;
    PORT
      LAYER M4 ;
        RECT  0 71.472 0.084 71.496 ;
    END
  END b[425]
  PIN b[426]
    DIRECTION OUTPUT ;
    USE SIGNAL ;
    PORT
      LAYER M4 ;
        RECT  0 71.568 0.084 71.592 ;
    END
  END b[426]
  PIN b[427]
    DIRECTION OUTPUT ;
    USE SIGNAL ;
    PORT
      LAYER M4 ;
        RECT  0 71.664 0.084 71.688 ;
    END
  END b[427]
  PIN b[428]
    DIRECTION OUTPUT ;
    USE SIGNAL ;
    PORT
      LAYER M4 ;
        RECT  0 71.76 0.084 71.784 ;
    END
  END b[428]
  PIN b[429]
    DIRECTION OUTPUT ;
    USE SIGNAL ;
    PORT
      LAYER M4 ;
        RECT  0 71.856 0.084 71.88 ;
    END
  END b[429]
  PIN b[42]
    DIRECTION OUTPUT ;
    USE SIGNAL ;
    PORT
      LAYER M4 ;
        RECT  0 61.584 0.084 61.608 ;
    END
  END b[42]
  PIN b[430]
    DIRECTION OUTPUT ;
    USE SIGNAL ;
    PORT
      LAYER M4 ;
        RECT  0 71.952 0.084 71.976 ;
    END
  END b[430]
  PIN b[431]
    DIRECTION OUTPUT ;
    USE SIGNAL ;
    PORT
      LAYER M4 ;
        RECT  0 72.048 0.084 72.072 ;
    END
  END b[431]
  PIN b[432]
    DIRECTION OUTPUT ;
    USE SIGNAL ;
    PORT
      LAYER M4 ;
        RECT  0 72.144 0.084 72.168 ;
    END
  END b[432]
  PIN b[433]
    DIRECTION OUTPUT ;
    USE SIGNAL ;
    PORT
      LAYER M4 ;
        RECT  0 72.24 0.084 72.264 ;
    END
  END b[433]
  PIN b[434]
    DIRECTION OUTPUT ;
    USE SIGNAL ;
    PORT
      LAYER M4 ;
        RECT  0 72.336 0.084 72.36 ;
    END
  END b[434]
  PIN b[435]
    DIRECTION OUTPUT ;
    USE SIGNAL ;
    PORT
      LAYER M4 ;
        RECT  0 72.432 0.084 72.456 ;
    END
  END b[435]
  PIN b[436]
    DIRECTION OUTPUT ;
    USE SIGNAL ;
    PORT
      LAYER M4 ;
        RECT  0 72.528 0.084 72.552 ;
    END
  END b[436]
  PIN b[437]
    DIRECTION OUTPUT ;
    USE SIGNAL ;
    PORT
      LAYER M4 ;
        RECT  0 72.624 0.084 72.648 ;
    END
  END b[437]
  PIN b[438]
    DIRECTION OUTPUT ;
    USE SIGNAL ;
    PORT
      LAYER M4 ;
        RECT  0 72.72 0.084 72.744 ;
    END
  END b[438]
  PIN b[439]
    DIRECTION OUTPUT ;
    USE SIGNAL ;
    PORT
      LAYER M4 ;
        RECT  0 72.816 0.084 72.84 ;
    END
  END b[439]
  PIN b[43]
    DIRECTION OUTPUT ;
    USE SIGNAL ;
    PORT
      LAYER M4 ;
        RECT  0 61.68 0.084 61.704 ;
    END
  END b[43]
  PIN b[440]
    DIRECTION OUTPUT ;
    USE SIGNAL ;
    PORT
      LAYER M4 ;
        RECT  0 72.912 0.084 72.936 ;
    END
  END b[440]
  PIN b[441]
    DIRECTION OUTPUT ;
    USE SIGNAL ;
    PORT
      LAYER M4 ;
        RECT  0 73.008 0.084 73.032 ;
    END
  END b[441]
  PIN b[442]
    DIRECTION OUTPUT ;
    USE SIGNAL ;
    PORT
      LAYER M4 ;
        RECT  0 73.104 0.084 73.128 ;
    END
  END b[442]
  PIN b[443]
    DIRECTION OUTPUT ;
    USE SIGNAL ;
    PORT
      LAYER M4 ;
        RECT  0 73.2 0.084 73.224 ;
    END
  END b[443]
  PIN b[444]
    DIRECTION OUTPUT ;
    USE SIGNAL ;
    PORT
      LAYER M4 ;
        RECT  0 73.296 0.084 73.32 ;
    END
  END b[444]
  PIN b[445]
    DIRECTION OUTPUT ;
    USE SIGNAL ;
    PORT
      LAYER M4 ;
        RECT  0 73.392 0.084 73.416 ;
    END
  END b[445]
  PIN b[446]
    DIRECTION OUTPUT ;
    USE SIGNAL ;
    PORT
      LAYER M4 ;
        RECT  0 73.488 0.084 73.512 ;
    END
  END b[446]
  PIN b[447]
    DIRECTION OUTPUT ;
    USE SIGNAL ;
    PORT
      LAYER M4 ;
        RECT  0 73.584 0.084 73.608 ;
    END
  END b[447]
  PIN b[448]
    DIRECTION OUTPUT ;
    USE SIGNAL ;
    PORT
      LAYER M4 ;
        RECT  0 79.824 0.084 79.848 ;
    END
  END b[448]
  PIN b[449]
    DIRECTION OUTPUT ;
    USE SIGNAL ;
    PORT
      LAYER M4 ;
        RECT  0 79.92 0.084 79.944 ;
    END
  END b[449]
  PIN b[44]
    DIRECTION OUTPUT ;
    USE SIGNAL ;
    PORT
      LAYER M4 ;
        RECT  0 61.776 0.084 61.8 ;
    END
  END b[44]
  PIN b[450]
    DIRECTION OUTPUT ;
    USE SIGNAL ;
    PORT
      LAYER M4 ;
        RECT  0 80.016 0.084 80.04 ;
    END
  END b[450]
  PIN b[451]
    DIRECTION OUTPUT ;
    USE SIGNAL ;
    PORT
      LAYER M4 ;
        RECT  0 80.112 0.084 80.136 ;
    END
  END b[451]
  PIN b[452]
    DIRECTION OUTPUT ;
    USE SIGNAL ;
    PORT
      LAYER M4 ;
        RECT  0 80.208 0.084 80.232 ;
    END
  END b[452]
  PIN b[453]
    DIRECTION OUTPUT ;
    USE SIGNAL ;
    PORT
      LAYER M4 ;
        RECT  0 80.304 0.084 80.328 ;
    END
  END b[453]
  PIN b[454]
    DIRECTION OUTPUT ;
    USE SIGNAL ;
    PORT
      LAYER M4 ;
        RECT  0 80.4 0.084 80.424 ;
    END
  END b[454]
  PIN b[455]
    DIRECTION OUTPUT ;
    USE SIGNAL ;
    PORT
      LAYER M4 ;
        RECT  0 80.496 0.084 80.52 ;
    END
  END b[455]
  PIN b[456]
    DIRECTION OUTPUT ;
    USE SIGNAL ;
    PORT
      LAYER M4 ;
        RECT  0 80.592 0.084 80.616 ;
    END
  END b[456]
  PIN b[457]
    DIRECTION OUTPUT ;
    USE SIGNAL ;
    PORT
      LAYER M4 ;
        RECT  0 80.688 0.084 80.712 ;
    END
  END b[457]
  PIN b[458]
    DIRECTION OUTPUT ;
    USE SIGNAL ;
    PORT
      LAYER M4 ;
        RECT  0 80.784 0.084 80.808 ;
    END
  END b[458]
  PIN b[459]
    DIRECTION OUTPUT ;
    USE SIGNAL ;
    PORT
      LAYER M4 ;
        RECT  0 80.88 0.084 80.904 ;
    END
  END b[459]
  PIN b[45]
    DIRECTION OUTPUT ;
    USE SIGNAL ;
    PORT
      LAYER M4 ;
        RECT  0 61.872 0.084 61.896 ;
    END
  END b[45]
  PIN b[460]
    DIRECTION OUTPUT ;
    USE SIGNAL ;
    PORT
      LAYER M4 ;
        RECT  0 80.976 0.084 81 ;
    END
  END b[460]
  PIN b[461]
    DIRECTION OUTPUT ;
    USE SIGNAL ;
    PORT
      LAYER M4 ;
        RECT  0 81.072 0.084 81.096 ;
    END
  END b[461]
  PIN b[462]
    DIRECTION OUTPUT ;
    USE SIGNAL ;
    PORT
      LAYER M4 ;
        RECT  0 81.168 0.084 81.192 ;
    END
  END b[462]
  PIN b[463]
    DIRECTION OUTPUT ;
    USE SIGNAL ;
    PORT
      LAYER M4 ;
        RECT  0 81.264 0.084 81.288 ;
    END
  END b[463]
  PIN b[464]
    DIRECTION OUTPUT ;
    USE SIGNAL ;
    PORT
      LAYER M4 ;
        RECT  0 81.36 0.084 81.384 ;
    END
  END b[464]
  PIN b[465]
    DIRECTION OUTPUT ;
    USE SIGNAL ;
    PORT
      LAYER M4 ;
        RECT  0 81.456 0.084 81.48 ;
    END
  END b[465]
  PIN b[466]
    DIRECTION OUTPUT ;
    USE SIGNAL ;
    PORT
      LAYER M4 ;
        RECT  0 81.552 0.084 81.576 ;
    END
  END b[466]
  PIN b[467]
    DIRECTION OUTPUT ;
    USE SIGNAL ;
    PORT
      LAYER M4 ;
        RECT  0 81.648 0.084 81.672 ;
    END
  END b[467]
  PIN b[468]
    DIRECTION OUTPUT ;
    USE SIGNAL ;
    PORT
      LAYER M4 ;
        RECT  0 81.744 0.084 81.768 ;
    END
  END b[468]
  PIN b[469]
    DIRECTION OUTPUT ;
    USE SIGNAL ;
    PORT
      LAYER M4 ;
        RECT  0 81.84 0.084 81.864 ;
    END
  END b[469]
  PIN b[46]
    DIRECTION OUTPUT ;
    USE SIGNAL ;
    PORT
      LAYER M4 ;
        RECT  0 61.968 0.084 61.992 ;
    END
  END b[46]
  PIN b[470]
    DIRECTION OUTPUT ;
    USE SIGNAL ;
    PORT
      LAYER M4 ;
        RECT  0 81.936 0.084 81.96 ;
    END
  END b[470]
  PIN b[471]
    DIRECTION OUTPUT ;
    USE SIGNAL ;
    PORT
      LAYER M4 ;
        RECT  0 82.032 0.084 82.056 ;
    END
  END b[471]
  PIN b[472]
    DIRECTION OUTPUT ;
    USE SIGNAL ;
    PORT
      LAYER M4 ;
        RECT  0 82.128 0.084 82.152 ;
    END
  END b[472]
  PIN b[473]
    DIRECTION OUTPUT ;
    USE SIGNAL ;
    PORT
      LAYER M4 ;
        RECT  0 82.224 0.084 82.248 ;
    END
  END b[473]
  PIN b[474]
    DIRECTION OUTPUT ;
    USE SIGNAL ;
    PORT
      LAYER M4 ;
        RECT  0 82.32 0.084 82.344 ;
    END
  END b[474]
  PIN b[475]
    DIRECTION OUTPUT ;
    USE SIGNAL ;
    PORT
      LAYER M4 ;
        RECT  0 82.416 0.084 82.44 ;
    END
  END b[475]
  PIN b[476]
    DIRECTION OUTPUT ;
    USE SIGNAL ;
    PORT
      LAYER M4 ;
        RECT  0 82.512 0.084 82.536 ;
    END
  END b[476]
  PIN b[477]
    DIRECTION OUTPUT ;
    USE SIGNAL ;
    PORT
      LAYER M4 ;
        RECT  0 82.608 0.084 82.632 ;
    END
  END b[477]
  PIN b[478]
    DIRECTION OUTPUT ;
    USE SIGNAL ;
    PORT
      LAYER M4 ;
        RECT  0 82.704 0.084 82.728 ;
    END
  END b[478]
  PIN b[479]
    DIRECTION OUTPUT ;
    USE SIGNAL ;
    PORT
      LAYER M4 ;
        RECT  0 82.8 0.084 82.824 ;
    END
  END b[479]
  PIN b[47]
    DIRECTION OUTPUT ;
    USE SIGNAL ;
    PORT
      LAYER M4 ;
        RECT  0 62.064 0.084 62.088 ;
    END
  END b[47]
  PIN b[480]
    DIRECTION OUTPUT ;
    USE SIGNAL ;
    PORT
      LAYER M4 ;
        RECT  0 76.752 0.084 76.776 ;
    END
  END b[480]
  PIN b[481]
    DIRECTION OUTPUT ;
    USE SIGNAL ;
    PORT
      LAYER M4 ;
        RECT  0 76.848 0.084 76.872 ;
    END
  END b[481]
  PIN b[482]
    DIRECTION OUTPUT ;
    USE SIGNAL ;
    PORT
      LAYER M4 ;
        RECT  0 76.944 0.084 76.968 ;
    END
  END b[482]
  PIN b[483]
    DIRECTION OUTPUT ;
    USE SIGNAL ;
    PORT
      LAYER M4 ;
        RECT  0 77.04 0.084 77.064 ;
    END
  END b[483]
  PIN b[484]
    DIRECTION OUTPUT ;
    USE SIGNAL ;
    PORT
      LAYER M4 ;
        RECT  0 77.136 0.084 77.16 ;
    END
  END b[484]
  PIN b[485]
    DIRECTION OUTPUT ;
    USE SIGNAL ;
    PORT
      LAYER M4 ;
        RECT  0 77.232 0.084 77.256 ;
    END
  END b[485]
  PIN b[486]
    DIRECTION OUTPUT ;
    USE SIGNAL ;
    PORT
      LAYER M4 ;
        RECT  0 77.328 0.084 77.352 ;
    END
  END b[486]
  PIN b[487]
    DIRECTION OUTPUT ;
    USE SIGNAL ;
    PORT
      LAYER M4 ;
        RECT  0 77.424 0.084 77.448 ;
    END
  END b[487]
  PIN b[488]
    DIRECTION OUTPUT ;
    USE SIGNAL ;
    PORT
      LAYER M4 ;
        RECT  0 77.52 0.084 77.544 ;
    END
  END b[488]
  PIN b[489]
    DIRECTION OUTPUT ;
    USE SIGNAL ;
    PORT
      LAYER M4 ;
        RECT  0 77.616 0.084 77.64 ;
    END
  END b[489]
  PIN b[48]
    DIRECTION OUTPUT ;
    USE SIGNAL ;
    PORT
      LAYER M4 ;
        RECT  0 62.16 0.084 62.184 ;
    END
  END b[48]
  PIN b[490]
    DIRECTION OUTPUT ;
    USE SIGNAL ;
    PORT
      LAYER M4 ;
        RECT  0 77.712 0.084 77.736 ;
    END
  END b[490]
  PIN b[491]
    DIRECTION OUTPUT ;
    USE SIGNAL ;
    PORT
      LAYER M4 ;
        RECT  0 77.808 0.084 77.832 ;
    END
  END b[491]
  PIN b[492]
    DIRECTION OUTPUT ;
    USE SIGNAL ;
    PORT
      LAYER M4 ;
        RECT  0 77.904 0.084 77.928 ;
    END
  END b[492]
  PIN b[493]
    DIRECTION OUTPUT ;
    USE SIGNAL ;
    PORT
      LAYER M4 ;
        RECT  0 78 0.084 78.024 ;
    END
  END b[493]
  PIN b[494]
    DIRECTION OUTPUT ;
    USE SIGNAL ;
    PORT
      LAYER M4 ;
        RECT  0 78.096 0.084 78.12 ;
    END
  END b[494]
  PIN b[495]
    DIRECTION OUTPUT ;
    USE SIGNAL ;
    PORT
      LAYER M4 ;
        RECT  0 78.192 0.084 78.216 ;
    END
  END b[495]
  PIN b[496]
    DIRECTION OUTPUT ;
    USE SIGNAL ;
    PORT
      LAYER M4 ;
        RECT  0 78.288 0.084 78.312 ;
    END
  END b[496]
  PIN b[497]
    DIRECTION OUTPUT ;
    USE SIGNAL ;
    PORT
      LAYER M4 ;
        RECT  0 78.384 0.084 78.408 ;
    END
  END b[497]
  PIN b[498]
    DIRECTION OUTPUT ;
    USE SIGNAL ;
    PORT
      LAYER M4 ;
        RECT  0 78.48 0.084 78.504 ;
    END
  END b[498]
  PIN b[499]
    DIRECTION OUTPUT ;
    USE SIGNAL ;
    PORT
      LAYER M4 ;
        RECT  0 78.576 0.084 78.6 ;
    END
  END b[499]
  PIN b[49]
    DIRECTION OUTPUT ;
    USE SIGNAL ;
    PORT
      LAYER M4 ;
        RECT  0 62.256 0.084 62.28 ;
    END
  END b[49]
  PIN b[4]
    DIRECTION OUTPUT ;
    USE SIGNAL ;
    PORT
      LAYER M4 ;
        RECT  0 48.72 0.084 48.744 ;
    END
  END b[4]
  PIN b[500]
    DIRECTION OUTPUT ;
    USE SIGNAL ;
    PORT
      LAYER M4 ;
        RECT  0 78.672 0.084 78.696 ;
    END
  END b[500]
  PIN b[501]
    DIRECTION OUTPUT ;
    USE SIGNAL ;
    PORT
      LAYER M4 ;
        RECT  0 78.768 0.084 78.792 ;
    END
  END b[501]
  PIN b[502]
    DIRECTION OUTPUT ;
    USE SIGNAL ;
    PORT
      LAYER M4 ;
        RECT  0 78.864 0.084 78.888 ;
    END
  END b[502]
  PIN b[503]
    DIRECTION OUTPUT ;
    USE SIGNAL ;
    PORT
      LAYER M4 ;
        RECT  0 78.96 0.084 78.984 ;
    END
  END b[503]
  PIN b[504]
    DIRECTION OUTPUT ;
    USE SIGNAL ;
    PORT
      LAYER M4 ;
        RECT  0 79.056 0.084 79.08 ;
    END
  END b[504]
  PIN b[505]
    DIRECTION OUTPUT ;
    USE SIGNAL ;
    PORT
      LAYER M4 ;
        RECT  0 79.152 0.084 79.176 ;
    END
  END b[505]
  PIN b[506]
    DIRECTION OUTPUT ;
    USE SIGNAL ;
    PORT
      LAYER M4 ;
        RECT  0 79.248 0.084 79.272 ;
    END
  END b[506]
  PIN b[507]
    DIRECTION OUTPUT ;
    USE SIGNAL ;
    PORT
      LAYER M4 ;
        RECT  0 79.344 0.084 79.368 ;
    END
  END b[507]
  PIN b[508]
    DIRECTION OUTPUT ;
    USE SIGNAL ;
    PORT
      LAYER M4 ;
        RECT  0 79.44 0.084 79.464 ;
    END
  END b[508]
  PIN b[509]
    DIRECTION OUTPUT ;
    USE SIGNAL ;
    PORT
      LAYER M4 ;
        RECT  0 79.536 0.084 79.56 ;
    END
  END b[509]
  PIN b[50]
    DIRECTION OUTPUT ;
    USE SIGNAL ;
    PORT
      LAYER M4 ;
        RECT  0 62.352 0.084 62.376 ;
    END
  END b[50]
  PIN b[510]
    DIRECTION OUTPUT ;
    USE SIGNAL ;
    PORT
      LAYER M4 ;
        RECT  0 79.632 0.084 79.656 ;
    END
  END b[510]
  PIN b[511]
    DIRECTION OUTPUT ;
    USE SIGNAL ;
    PORT
      LAYER M4 ;
        RECT  0 79.728 0.084 79.752 ;
    END
  END b[511]
  PIN b[512]
    DIRECTION OUTPUT ;
    USE SIGNAL ;
    PORT
      LAYER M4 ;
        RECT  0 67.536 0.084 67.56 ;
    END
  END b[512]
  PIN b[513]
    DIRECTION OUTPUT ;
    USE SIGNAL ;
    PORT
      LAYER M4 ;
        RECT  0 67.632 0.084 67.656 ;
    END
  END b[513]
  PIN b[514]
    DIRECTION OUTPUT ;
    USE SIGNAL ;
    PORT
      LAYER M4 ;
        RECT  0 67.728 0.084 67.752 ;
    END
  END b[514]
  PIN b[515]
    DIRECTION OUTPUT ;
    USE SIGNAL ;
    PORT
      LAYER M4 ;
        RECT  0 67.824 0.084 67.848 ;
    END
  END b[515]
  PIN b[516]
    DIRECTION OUTPUT ;
    USE SIGNAL ;
    PORT
      LAYER M4 ;
        RECT  0 67.92 0.084 67.944 ;
    END
  END b[516]
  PIN b[517]
    DIRECTION OUTPUT ;
    USE SIGNAL ;
    PORT
      LAYER M4 ;
        RECT  0 68.016 0.084 68.04 ;
    END
  END b[517]
  PIN b[518]
    DIRECTION OUTPUT ;
    USE SIGNAL ;
    PORT
      LAYER M4 ;
        RECT  0 68.112 0.084 68.136 ;
    END
  END b[518]
  PIN b[519]
    DIRECTION OUTPUT ;
    USE SIGNAL ;
    PORT
      LAYER M4 ;
        RECT  0 68.208 0.084 68.232 ;
    END
  END b[519]
  PIN b[51]
    DIRECTION OUTPUT ;
    USE SIGNAL ;
    PORT
      LAYER M4 ;
        RECT  0 62.448 0.084 62.472 ;
    END
  END b[51]
  PIN b[520]
    DIRECTION OUTPUT ;
    USE SIGNAL ;
    PORT
      LAYER M4 ;
        RECT  0 68.304 0.084 68.328 ;
    END
  END b[520]
  PIN b[521]
    DIRECTION OUTPUT ;
    USE SIGNAL ;
    PORT
      LAYER M4 ;
        RECT  0 68.4 0.084 68.424 ;
    END
  END b[521]
  PIN b[522]
    DIRECTION OUTPUT ;
    USE SIGNAL ;
    PORT
      LAYER M4 ;
        RECT  0 68.496 0.084 68.52 ;
    END
  END b[522]
  PIN b[523]
    DIRECTION OUTPUT ;
    USE SIGNAL ;
    PORT
      LAYER M4 ;
        RECT  0 68.592 0.084 68.616 ;
    END
  END b[523]
  PIN b[524]
    DIRECTION OUTPUT ;
    USE SIGNAL ;
    PORT
      LAYER M4 ;
        RECT  0 68.688 0.084 68.712 ;
    END
  END b[524]
  PIN b[525]
    DIRECTION OUTPUT ;
    USE SIGNAL ;
    PORT
      LAYER M4 ;
        RECT  0 68.784 0.084 68.808 ;
    END
  END b[525]
  PIN b[526]
    DIRECTION OUTPUT ;
    USE SIGNAL ;
    PORT
      LAYER M4 ;
        RECT  0 68.88 0.084 68.904 ;
    END
  END b[526]
  PIN b[527]
    DIRECTION OUTPUT ;
    USE SIGNAL ;
    PORT
      LAYER M4 ;
        RECT  0 68.976 0.084 69 ;
    END
  END b[527]
  PIN b[528]
    DIRECTION OUTPUT ;
    USE SIGNAL ;
    PORT
      LAYER M4 ;
        RECT  0 69.072 0.084 69.096 ;
    END
  END b[528]
  PIN b[529]
    DIRECTION OUTPUT ;
    USE SIGNAL ;
    PORT
      LAYER M4 ;
        RECT  0 69.168 0.084 69.192 ;
    END
  END b[529]
  PIN b[52]
    DIRECTION OUTPUT ;
    USE SIGNAL ;
    PORT
      LAYER M4 ;
        RECT  0 62.544 0.084 62.568 ;
    END
  END b[52]
  PIN b[530]
    DIRECTION OUTPUT ;
    USE SIGNAL ;
    PORT
      LAYER M4 ;
        RECT  0 69.264 0.084 69.288 ;
    END
  END b[530]
  PIN b[531]
    DIRECTION OUTPUT ;
    USE SIGNAL ;
    PORT
      LAYER M4 ;
        RECT  0 69.36 0.084 69.384 ;
    END
  END b[531]
  PIN b[532]
    DIRECTION OUTPUT ;
    USE SIGNAL ;
    PORT
      LAYER M4 ;
        RECT  0 69.456 0.084 69.48 ;
    END
  END b[532]
  PIN b[533]
    DIRECTION OUTPUT ;
    USE SIGNAL ;
    PORT
      LAYER M4 ;
        RECT  0 69.552 0.084 69.576 ;
    END
  END b[533]
  PIN b[534]
    DIRECTION OUTPUT ;
    USE SIGNAL ;
    PORT
      LAYER M4 ;
        RECT  0 69.648 0.084 69.672 ;
    END
  END b[534]
  PIN b[535]
    DIRECTION OUTPUT ;
    USE SIGNAL ;
    PORT
      LAYER M4 ;
        RECT  0 69.744 0.084 69.768 ;
    END
  END b[535]
  PIN b[536]
    DIRECTION OUTPUT ;
    USE SIGNAL ;
    PORT
      LAYER M4 ;
        RECT  0 69.84 0.084 69.864 ;
    END
  END b[536]
  PIN b[537]
    DIRECTION OUTPUT ;
    USE SIGNAL ;
    PORT
      LAYER M4 ;
        RECT  0 69.936 0.084 69.96 ;
    END
  END b[537]
  PIN b[538]
    DIRECTION OUTPUT ;
    USE SIGNAL ;
    PORT
      LAYER M4 ;
        RECT  0 70.032 0.084 70.056 ;
    END
  END b[538]
  PIN b[539]
    DIRECTION OUTPUT ;
    USE SIGNAL ;
    PORT
      LAYER M4 ;
        RECT  0 70.128 0.084 70.152 ;
    END
  END b[539]
  PIN b[53]
    DIRECTION OUTPUT ;
    USE SIGNAL ;
    PORT
      LAYER M4 ;
        RECT  0 62.64 0.084 62.664 ;
    END
  END b[53]
  PIN b[540]
    DIRECTION OUTPUT ;
    USE SIGNAL ;
    PORT
      LAYER M4 ;
        RECT  0 70.224 0.084 70.248 ;
    END
  END b[540]
  PIN b[541]
    DIRECTION OUTPUT ;
    USE SIGNAL ;
    PORT
      LAYER M4 ;
        RECT  0 70.32 0.084 70.344 ;
    END
  END b[541]
  PIN b[542]
    DIRECTION OUTPUT ;
    USE SIGNAL ;
    PORT
      LAYER M4 ;
        RECT  0 70.416 0.084 70.44 ;
    END
  END b[542]
  PIN b[543]
    DIRECTION OUTPUT ;
    USE SIGNAL ;
    PORT
      LAYER M4 ;
        RECT  0 70.512 0.084 70.536 ;
    END
  END b[543]
  PIN b[544]
    DIRECTION OUTPUT ;
    USE SIGNAL ;
    PORT
      LAYER M4 ;
        RECT  0 82.896 0.084 82.92 ;
    END
  END b[544]
  PIN b[545]
    DIRECTION OUTPUT ;
    USE SIGNAL ;
    PORT
      LAYER M4 ;
        RECT  0 82.992 0.084 83.016 ;
    END
  END b[545]
  PIN b[546]
    DIRECTION OUTPUT ;
    USE SIGNAL ;
    PORT
      LAYER M4 ;
        RECT  0 83.088 0.084 83.112 ;
    END
  END b[546]
  PIN b[547]
    DIRECTION OUTPUT ;
    USE SIGNAL ;
    PORT
      LAYER M4 ;
        RECT  0 83.184 0.084 83.208 ;
    END
  END b[547]
  PIN b[548]
    DIRECTION OUTPUT ;
    USE SIGNAL ;
    PORT
      LAYER M4 ;
        RECT  0 83.28 0.084 83.304 ;
    END
  END b[548]
  PIN b[549]
    DIRECTION OUTPUT ;
    USE SIGNAL ;
    PORT
      LAYER M4 ;
        RECT  0 83.376 0.084 83.4 ;
    END
  END b[549]
  PIN b[54]
    DIRECTION OUTPUT ;
    USE SIGNAL ;
    PORT
      LAYER M4 ;
        RECT  0 62.736 0.084 62.76 ;
    END
  END b[54]
  PIN b[550]
    DIRECTION OUTPUT ;
    USE SIGNAL ;
    PORT
      LAYER M4 ;
        RECT  0 83.472 0.084 83.496 ;
    END
  END b[550]
  PIN b[551]
    DIRECTION OUTPUT ;
    USE SIGNAL ;
    PORT
      LAYER M4 ;
        RECT  0 83.568 0.084 83.592 ;
    END
  END b[551]
  PIN b[552]
    DIRECTION OUTPUT ;
    USE SIGNAL ;
    PORT
      LAYER M4 ;
        RECT  0 83.664 0.084 83.688 ;
    END
  END b[552]
  PIN b[553]
    DIRECTION OUTPUT ;
    USE SIGNAL ;
    PORT
      LAYER M4 ;
        RECT  0 83.76 0.084 83.784 ;
    END
  END b[553]
  PIN b[554]
    DIRECTION OUTPUT ;
    USE SIGNAL ;
    PORT
      LAYER M4 ;
        RECT  0 83.856 0.084 83.88 ;
    END
  END b[554]
  PIN b[555]
    DIRECTION OUTPUT ;
    USE SIGNAL ;
    PORT
      LAYER M4 ;
        RECT  0 83.952 0.084 83.976 ;
    END
  END b[555]
  PIN b[556]
    DIRECTION OUTPUT ;
    USE SIGNAL ;
    PORT
      LAYER M4 ;
        RECT  0 84.048 0.084 84.072 ;
    END
  END b[556]
  PIN b[557]
    DIRECTION OUTPUT ;
    USE SIGNAL ;
    PORT
      LAYER M4 ;
        RECT  0 84.144 0.084 84.168 ;
    END
  END b[557]
  PIN b[558]
    DIRECTION OUTPUT ;
    USE SIGNAL ;
    PORT
      LAYER M4 ;
        RECT  0 84.24 0.084 84.264 ;
    END
  END b[558]
  PIN b[559]
    DIRECTION OUTPUT ;
    USE SIGNAL ;
    PORT
      LAYER M4 ;
        RECT  0 84.336 0.084 84.36 ;
    END
  END b[559]
  PIN b[55]
    DIRECTION OUTPUT ;
    USE SIGNAL ;
    PORT
      LAYER M4 ;
        RECT  0 62.832 0.084 62.856 ;
    END
  END b[55]
  PIN b[560]
    DIRECTION OUTPUT ;
    USE SIGNAL ;
    PORT
      LAYER M4 ;
        RECT  0 84.432 0.084 84.456 ;
    END
  END b[560]
  PIN b[561]
    DIRECTION OUTPUT ;
    USE SIGNAL ;
    PORT
      LAYER M4 ;
        RECT  0 84.528 0.084 84.552 ;
    END
  END b[561]
  PIN b[562]
    DIRECTION OUTPUT ;
    USE SIGNAL ;
    PORT
      LAYER M4 ;
        RECT  0 84.624 0.084 84.648 ;
    END
  END b[562]
  PIN b[563]
    DIRECTION OUTPUT ;
    USE SIGNAL ;
    PORT
      LAYER M4 ;
        RECT  0 84.72 0.084 84.744 ;
    END
  END b[563]
  PIN b[564]
    DIRECTION OUTPUT ;
    USE SIGNAL ;
    PORT
      LAYER M4 ;
        RECT  0 84.816 0.084 84.84 ;
    END
  END b[564]
  PIN b[565]
    DIRECTION OUTPUT ;
    USE SIGNAL ;
    PORT
      LAYER M4 ;
        RECT  0 84.912 0.084 84.936 ;
    END
  END b[565]
  PIN b[566]
    DIRECTION OUTPUT ;
    USE SIGNAL ;
    PORT
      LAYER M4 ;
        RECT  0 85.008 0.084 85.032 ;
    END
  END b[566]
  PIN b[567]
    DIRECTION OUTPUT ;
    USE SIGNAL ;
    PORT
      LAYER M4 ;
        RECT  0 85.104 0.084 85.128 ;
    END
  END b[567]
  PIN b[568]
    DIRECTION OUTPUT ;
    USE SIGNAL ;
    PORT
      LAYER M4 ;
        RECT  0 85.2 0.084 85.224 ;
    END
  END b[568]
  PIN b[569]
    DIRECTION OUTPUT ;
    USE SIGNAL ;
    PORT
      LAYER M4 ;
        RECT  0 85.296 0.084 85.32 ;
    END
  END b[569]
  PIN b[56]
    DIRECTION OUTPUT ;
    USE SIGNAL ;
    PORT
      LAYER M4 ;
        RECT  0 62.928 0.084 62.952 ;
    END
  END b[56]
  PIN b[570]
    DIRECTION OUTPUT ;
    USE SIGNAL ;
    PORT
      LAYER M4 ;
        RECT  0 85.392 0.084 85.416 ;
    END
  END b[570]
  PIN b[571]
    DIRECTION OUTPUT ;
    USE SIGNAL ;
    PORT
      LAYER M4 ;
        RECT  0 85.488 0.084 85.512 ;
    END
  END b[571]
  PIN b[572]
    DIRECTION OUTPUT ;
    USE SIGNAL ;
    PORT
      LAYER M4 ;
        RECT  0 85.584 0.084 85.608 ;
    END
  END b[572]
  PIN b[573]
    DIRECTION OUTPUT ;
    USE SIGNAL ;
    PORT
      LAYER M4 ;
        RECT  0 85.68 0.084 85.704 ;
    END
  END b[573]
  PIN b[574]
    DIRECTION OUTPUT ;
    USE SIGNAL ;
    PORT
      LAYER M4 ;
        RECT  0 85.776 0.084 85.8 ;
    END
  END b[574]
  PIN b[575]
    DIRECTION OUTPUT ;
    USE SIGNAL ;
    PORT
      LAYER M4 ;
        RECT  0 85.872 0.084 85.896 ;
    END
  END b[575]
  PIN b[576]
    DIRECTION OUTPUT ;
    USE SIGNAL ;
    PORT
      LAYER M4 ;
        RECT  0 25.968 0.084 25.992 ;
    END
  END b[576]
  PIN b[577]
    DIRECTION OUTPUT ;
    USE SIGNAL ;
    PORT
      LAYER M4 ;
        RECT  0 26.064 0.084 26.088 ;
    END
  END b[577]
  PIN b[578]
    DIRECTION OUTPUT ;
    USE SIGNAL ;
    PORT
      LAYER M4 ;
        RECT  0 26.16 0.084 26.184 ;
    END
  END b[578]
  PIN b[579]
    DIRECTION OUTPUT ;
    USE SIGNAL ;
    PORT
      LAYER M4 ;
        RECT  0 26.256 0.084 26.28 ;
    END
  END b[579]
  PIN b[57]
    DIRECTION OUTPUT ;
    USE SIGNAL ;
    PORT
      LAYER M4 ;
        RECT  0 63.024 0.084 63.048 ;
    END
  END b[57]
  PIN b[580]
    DIRECTION OUTPUT ;
    USE SIGNAL ;
    PORT
      LAYER M4 ;
        RECT  0 26.352 0.084 26.376 ;
    END
  END b[580]
  PIN b[581]
    DIRECTION OUTPUT ;
    USE SIGNAL ;
    PORT
      LAYER M4 ;
        RECT  0 26.448 0.084 26.472 ;
    END
  END b[581]
  PIN b[582]
    DIRECTION OUTPUT ;
    USE SIGNAL ;
    PORT
      LAYER M4 ;
        RECT  0 26.544 0.084 26.568 ;
    END
  END b[582]
  PIN b[583]
    DIRECTION OUTPUT ;
    USE SIGNAL ;
    PORT
      LAYER M4 ;
        RECT  0 26.64 0.084 26.664 ;
    END
  END b[583]
  PIN b[584]
    DIRECTION OUTPUT ;
    USE SIGNAL ;
    PORT
      LAYER M4 ;
        RECT  0 26.736 0.084 26.76 ;
    END
  END b[584]
  PIN b[585]
    DIRECTION OUTPUT ;
    USE SIGNAL ;
    PORT
      LAYER M4 ;
        RECT  0 26.832 0.084 26.856 ;
    END
  END b[585]
  PIN b[586]
    DIRECTION OUTPUT ;
    USE SIGNAL ;
    PORT
      LAYER M4 ;
        RECT  0 26.928 0.084 26.952 ;
    END
  END b[586]
  PIN b[587]
    DIRECTION OUTPUT ;
    USE SIGNAL ;
    PORT
      LAYER M4 ;
        RECT  0 27.024 0.084 27.048 ;
    END
  END b[587]
  PIN b[588]
    DIRECTION OUTPUT ;
    USE SIGNAL ;
    PORT
      LAYER M4 ;
        RECT  0 27.12 0.084 27.144 ;
    END
  END b[588]
  PIN b[589]
    DIRECTION OUTPUT ;
    USE SIGNAL ;
    PORT
      LAYER M4 ;
        RECT  0 27.216 0.084 27.24 ;
    END
  END b[589]
  PIN b[58]
    DIRECTION OUTPUT ;
    USE SIGNAL ;
    PORT
      LAYER M4 ;
        RECT  0 63.12 0.084 63.144 ;
    END
  END b[58]
  PIN b[590]
    DIRECTION OUTPUT ;
    USE SIGNAL ;
    PORT
      LAYER M4 ;
        RECT  0 27.312 0.084 27.336 ;
    END
  END b[590]
  PIN b[591]
    DIRECTION OUTPUT ;
    USE SIGNAL ;
    PORT
      LAYER M4 ;
        RECT  0 27.408 0.084 27.432 ;
    END
  END b[591]
  PIN b[592]
    DIRECTION OUTPUT ;
    USE SIGNAL ;
    PORT
      LAYER M4 ;
        RECT  0 27.504 0.084 27.528 ;
    END
  END b[592]
  PIN b[593]
    DIRECTION OUTPUT ;
    USE SIGNAL ;
    PORT
      LAYER M4 ;
        RECT  0 27.6 0.084 27.624 ;
    END
  END b[593]
  PIN b[594]
    DIRECTION OUTPUT ;
    USE SIGNAL ;
    PORT
      LAYER M4 ;
        RECT  0 27.696 0.084 27.72 ;
    END
  END b[594]
  PIN b[595]
    DIRECTION OUTPUT ;
    USE SIGNAL ;
    PORT
      LAYER M4 ;
        RECT  0 27.792 0.084 27.816 ;
    END
  END b[595]
  PIN b[596]
    DIRECTION OUTPUT ;
    USE SIGNAL ;
    PORT
      LAYER M4 ;
        RECT  0 27.888 0.084 27.912 ;
    END
  END b[596]
  PIN b[597]
    DIRECTION OUTPUT ;
    USE SIGNAL ;
    PORT
      LAYER M4 ;
        RECT  0 27.984 0.084 28.008 ;
    END
  END b[597]
  PIN b[598]
    DIRECTION OUTPUT ;
    USE SIGNAL ;
    PORT
      LAYER M4 ;
        RECT  0 28.08 0.084 28.104 ;
    END
  END b[598]
  PIN b[599]
    DIRECTION OUTPUT ;
    USE SIGNAL ;
    PORT
      LAYER M4 ;
        RECT  0 28.176 0.084 28.2 ;
    END
  END b[599]
  PIN b[59]
    DIRECTION OUTPUT ;
    USE SIGNAL ;
    PORT
      LAYER M4 ;
        RECT  0 63.216 0.084 63.24 ;
    END
  END b[59]
  PIN b[5]
    DIRECTION OUTPUT ;
    USE SIGNAL ;
    PORT
      LAYER M4 ;
        RECT  0 48.816 0.084 48.84 ;
    END
  END b[5]
  PIN b[60]
    DIRECTION OUTPUT ;
    USE SIGNAL ;
    PORT
      LAYER M4 ;
        RECT  0 63.312 0.084 63.336 ;
    END
  END b[60]
  PIN b[61]
    DIRECTION OUTPUT ;
    USE SIGNAL ;
    PORT
      LAYER M4 ;
        RECT  0 63.408 0.084 63.432 ;
    END
  END b[61]
  PIN b[62]
    DIRECTION OUTPUT ;
    USE SIGNAL ;
    PORT
      LAYER M4 ;
        RECT  0 63.504 0.084 63.528 ;
    END
  END b[62]
  PIN b[63]
    DIRECTION OUTPUT ;
    USE SIGNAL ;
    PORT
      LAYER M4 ;
        RECT  0 63.6 0.084 63.624 ;
    END
  END b[63]
  PIN b[64]
    DIRECTION OUTPUT ;
    USE SIGNAL ;
    PORT
      LAYER M4 ;
        RECT  0 51.408 0.084 51.432 ;
    END
  END b[64]
  PIN b[65]
    DIRECTION OUTPUT ;
    USE SIGNAL ;
    PORT
      LAYER M4 ;
        RECT  0 51.504 0.084 51.528 ;
    END
  END b[65]
  PIN b[66]
    DIRECTION OUTPUT ;
    USE SIGNAL ;
    PORT
      LAYER M4 ;
        RECT  0 51.6 0.084 51.624 ;
    END
  END b[66]
  PIN b[67]
    DIRECTION OUTPUT ;
    USE SIGNAL ;
    PORT
      LAYER M4 ;
        RECT  0 51.696 0.084 51.72 ;
    END
  END b[67]
  PIN b[68]
    DIRECTION OUTPUT ;
    USE SIGNAL ;
    PORT
      LAYER M4 ;
        RECT  0 51.792 0.084 51.816 ;
    END
  END b[68]
  PIN b[69]
    DIRECTION OUTPUT ;
    USE SIGNAL ;
    PORT
      LAYER M4 ;
        RECT  0 51.888 0.084 51.912 ;
    END
  END b[69]
  PIN b[6]
    DIRECTION OUTPUT ;
    USE SIGNAL ;
    PORT
      LAYER M4 ;
        RECT  0 48.912 0.084 48.936 ;
    END
  END b[6]
  PIN b[70]
    DIRECTION OUTPUT ;
    USE SIGNAL ;
    PORT
      LAYER M4 ;
        RECT  0 51.984 0.084 52.008 ;
    END
  END b[70]
  PIN b[71]
    DIRECTION OUTPUT ;
    USE SIGNAL ;
    PORT
      LAYER M4 ;
        RECT  0 52.08 0.084 52.104 ;
    END
  END b[71]
  PIN b[72]
    DIRECTION OUTPUT ;
    USE SIGNAL ;
    PORT
      LAYER M4 ;
        RECT  0 52.176 0.084 52.2 ;
    END
  END b[72]
  PIN b[73]
    DIRECTION OUTPUT ;
    USE SIGNAL ;
    PORT
      LAYER M4 ;
        RECT  0 52.272 0.084 52.296 ;
    END
  END b[73]
  PIN b[74]
    DIRECTION OUTPUT ;
    USE SIGNAL ;
    PORT
      LAYER M4 ;
        RECT  0 52.368 0.084 52.392 ;
    END
  END b[74]
  PIN b[75]
    DIRECTION OUTPUT ;
    USE SIGNAL ;
    PORT
      LAYER M4 ;
        RECT  0 52.464 0.084 52.488 ;
    END
  END b[75]
  PIN b[76]
    DIRECTION OUTPUT ;
    USE SIGNAL ;
    PORT
      LAYER M4 ;
        RECT  0 52.56 0.084 52.584 ;
    END
  END b[76]
  PIN b[77]
    DIRECTION OUTPUT ;
    USE SIGNAL ;
    PORT
      LAYER M4 ;
        RECT  0 52.656 0.084 52.68 ;
    END
  END b[77]
  PIN b[78]
    DIRECTION OUTPUT ;
    USE SIGNAL ;
    PORT
      LAYER M4 ;
        RECT  0 52.752 0.084 52.776 ;
    END
  END b[78]
  PIN b[79]
    DIRECTION OUTPUT ;
    USE SIGNAL ;
    PORT
      LAYER M4 ;
        RECT  0 52.848 0.084 52.872 ;
    END
  END b[79]
  PIN b[7]
    DIRECTION OUTPUT ;
    USE SIGNAL ;
    PORT
      LAYER M4 ;
        RECT  0 49.008 0.084 49.032 ;
    END
  END b[7]
  PIN b[80]
    DIRECTION OUTPUT ;
    USE SIGNAL ;
    PORT
      LAYER M4 ;
        RECT  0 52.944 0.084 52.968 ;
    END
  END b[80]
  PIN b[81]
    DIRECTION OUTPUT ;
    USE SIGNAL ;
    PORT
      LAYER M4 ;
        RECT  0 53.04 0.084 53.064 ;
    END
  END b[81]
  PIN b[82]
    DIRECTION OUTPUT ;
    USE SIGNAL ;
    PORT
      LAYER M4 ;
        RECT  0 53.136 0.084 53.16 ;
    END
  END b[82]
  PIN b[83]
    DIRECTION OUTPUT ;
    USE SIGNAL ;
    PORT
      LAYER M4 ;
        RECT  0 53.232 0.084 53.256 ;
    END
  END b[83]
  PIN b[84]
    DIRECTION OUTPUT ;
    USE SIGNAL ;
    PORT
      LAYER M4 ;
        RECT  0 53.328 0.084 53.352 ;
    END
  END b[84]
  PIN b[85]
    DIRECTION OUTPUT ;
    USE SIGNAL ;
    PORT
      LAYER M4 ;
        RECT  0 53.424 0.084 53.448 ;
    END
  END b[85]
  PIN b[86]
    DIRECTION OUTPUT ;
    USE SIGNAL ;
    PORT
      LAYER M4 ;
        RECT  0 53.52 0.084 53.544 ;
    END
  END b[86]
  PIN b[87]
    DIRECTION OUTPUT ;
    USE SIGNAL ;
    PORT
      LAYER M4 ;
        RECT  0 53.616 0.084 53.64 ;
    END
  END b[87]
  PIN b[88]
    DIRECTION OUTPUT ;
    USE SIGNAL ;
    PORT
      LAYER M4 ;
        RECT  0 53.712 0.084 53.736 ;
    END
  END b[88]
  PIN b[89]
    DIRECTION OUTPUT ;
    USE SIGNAL ;
    PORT
      LAYER M4 ;
        RECT  0 53.808 0.084 53.832 ;
    END
  END b[89]
  PIN b[8]
    DIRECTION OUTPUT ;
    USE SIGNAL ;
    PORT
      LAYER M4 ;
        RECT  0 49.104 0.084 49.128 ;
    END
  END b[8]
  PIN b[90]
    DIRECTION OUTPUT ;
    USE SIGNAL ;
    PORT
      LAYER M4 ;
        RECT  0 53.904 0.084 53.928 ;
    END
  END b[90]
  PIN b[91]
    DIRECTION OUTPUT ;
    USE SIGNAL ;
    PORT
      LAYER M4 ;
        RECT  0 54 0.084 54.024 ;
    END
  END b[91]
  PIN b[92]
    DIRECTION OUTPUT ;
    USE SIGNAL ;
    PORT
      LAYER M4 ;
        RECT  0 54.096 0.084 54.12 ;
    END
  END b[92]
  PIN b[93]
    DIRECTION OUTPUT ;
    USE SIGNAL ;
    PORT
      LAYER M4 ;
        RECT  0 54.192 0.084 54.216 ;
    END
  END b[93]
  PIN b[94]
    DIRECTION OUTPUT ;
    USE SIGNAL ;
    PORT
      LAYER M4 ;
        RECT  0 54.288 0.084 54.312 ;
    END
  END b[94]
  PIN b[95]
    DIRECTION OUTPUT ;
    USE SIGNAL ;
    PORT
      LAYER M4 ;
        RECT  0 54.384 0.084 54.408 ;
    END
  END b[95]
  PIN b[96]
    DIRECTION OUTPUT ;
    USE SIGNAL ;
    PORT
      LAYER M4 ;
        RECT  0 63.696 0.084 63.72 ;
    END
  END b[96]
  PIN b[97]
    DIRECTION OUTPUT ;
    USE SIGNAL ;
    PORT
      LAYER M4 ;
        RECT  0 63.792 0.084 63.816 ;
    END
  END b[97]
  PIN b[98]
    DIRECTION OUTPUT ;
    USE SIGNAL ;
    PORT
      LAYER M4 ;
        RECT  0 63.888 0.084 63.912 ;
    END
  END b[98]
  PIN b[99]
    DIRECTION OUTPUT ;
    USE SIGNAL ;
    PORT
      LAYER M4 ;
        RECT  0 63.984 0.084 64.008 ;
    END
  END b[99]
  PIN b[9]
    DIRECTION OUTPUT ;
    USE SIGNAL ;
    PORT
      LAYER M4 ;
        RECT  0 49.2 0.084 49.224 ;
    END
  END b[9]
  PIN ck
    DIRECTION INPUT ;
    USE SIGNAL ;
    PORT
      LAYER M5 ;
        RECT  32.208 105.732 32.232 105.816 ;
    END
  END ck
  PIN ck_o
    DIRECTION OUTPUT ;
    USE SIGNAL ;
    PORT
      LAYER M5 ;
        RECT  32.304 105.732 32.328 105.816 ;
    END
  END ck_o
  PIN eb
    DIRECTION OUTPUT ;
    USE SIGNAL ;
    PORT
      LAYER M4 ;
        RECT  0 28.272 0.084 28.296 ;
    END
  END eb
  PIN en
    DIRECTION INPUT ;
    USE SIGNAL ;
    PORT
      LAYER M5 ;
        RECT  32.4 105.732 32.424 105.816 ;
    END
  END en
  PIN VDD
    DIRECTION INOUT ;
    USE POWER ;
    PORT
      LAYER M5 ;
        RECT  61.992 2.151 62.112 103.433 ;
        RECT  59.292 2.151 59.412 103.433 ;
        RECT  56.592 2.151 56.712 103.433 ;
        RECT  53.892 2.151 54.012 103.433 ;
        RECT  51.192 2.151 51.312 103.433 ;
        RECT  48.492 2.151 48.612 103.433 ;
        RECT  45.792 2.151 45.912 103.433 ;
        RECT  43.092 2.151 43.212 103.433 ;
        RECT  40.392 2.151 40.512 103.433 ;
        RECT  37.692 2.151 37.812 103.433 ;
        RECT  34.992 2.151 35.112 103.433 ;
        RECT  32.292 2.151 32.412 103.433 ;
        RECT  29.592 2.151 29.712 103.433 ;
        RECT  26.892 2.151 27.012 103.433 ;
        RECT  24.192 2.151 24.312 103.433 ;
        RECT  21.492 2.151 21.612 103.433 ;
        RECT  18.792 2.151 18.912 103.433 ;
        RECT  16.092 2.151 16.212 103.433 ;
        RECT  13.392 2.151 13.512 103.433 ;
        RECT  10.692 2.151 10.812 103.433 ;
        RECT  7.992 2.151 8.112 103.433 ;
        RECT  5.292 2.151 5.412 103.433 ;
        RECT  2.592 2.151 2.712 103.433 ;
    END
  END VDD
  PIN VSS
    DIRECTION INOUT ;
    USE GROUND ;
    PORT
      LAYER M5 ;
        RECT  61.8 2.137 61.92 103.419 ;
        RECT  59.1 2.137 59.22 103.419 ;
        RECT  56.4 2.137 56.52 103.419 ;
        RECT  53.7 2.137 53.82 103.419 ;
        RECT  51 2.137 51.12 103.419 ;
        RECT  48.3 2.137 48.42 103.419 ;
        RECT  45.6 2.137 45.72 103.419 ;
        RECT  42.9 2.137 43.02 103.419 ;
        RECT  40.2 2.137 40.32 103.419 ;
        RECT  37.5 2.137 37.62 103.419 ;
        RECT  34.8 2.137 34.92 103.419 ;
        RECT  32.1 2.137 32.22 103.419 ;
        RECT  29.4 2.137 29.52 103.419 ;
        RECT  26.7 2.137 26.82 103.419 ;
        RECT  24 2.137 24.12 103.419 ;
        RECT  21.3 2.137 21.42 103.419 ;
        RECT  18.6 2.137 18.72 103.419 ;
        RECT  15.9 2.137 16.02 103.419 ;
        RECT  13.2 2.137 13.32 103.419 ;
        RECT  10.5 2.137 10.62 103.419 ;
        RECT  7.8 2.137 7.92 103.419 ;
        RECT  5.1 2.137 5.22 103.419 ;
        RECT  2.4 2.137 2.52 103.419 ;
    END
  END VSS
  OBS
    LAYER RVTN ;
     RECT  2.16 2.16 62.586 2.295 ;
     RECT  2.16 2.565 62.586 2.835 ;
     RECT  2.16 3.105 62.586 3.375 ;
     RECT  2.16 3.645 62.586 3.915 ;
     RECT  2.16 4.185 62.586 4.455 ;
     RECT  2.16 4.725 62.586 4.995 ;
     RECT  2.16 5.265 62.586 5.535 ;
     RECT  2.16 5.805 62.586 6.075 ;
     RECT  2.16 6.345 62.586 6.615 ;
     RECT  2.16 6.885 62.586 7.155 ;
     RECT  2.16 7.425 62.586 7.695 ;
     RECT  2.16 7.965 62.586 8.235 ;
     RECT  2.16 8.505 62.586 8.775 ;
     RECT  2.16 9.045 62.586 9.315 ;
     RECT  2.16 9.585 62.586 9.855 ;
     RECT  2.16 10.125 62.586 10.395 ;
     RECT  2.16 10.665 62.586 10.935 ;
     RECT  2.16 11.205 62.586 11.475 ;
     RECT  2.16 11.745 62.586 12.015 ;
     RECT  2.16 12.285 62.586 12.555 ;
     RECT  2.16 12.825 62.586 13.095 ;
     RECT  2.16 13.365 62.586 13.635 ;
     RECT  2.16 13.905 62.586 14.175 ;
     RECT  2.16 14.445 62.586 14.715 ;
     RECT  2.16 14.985 62.586 15.255 ;
     RECT  2.16 15.525 62.586 15.795 ;
     RECT  2.16 16.065 62.586 16.335 ;
     RECT  2.16 16.605 62.586 16.875 ;
     RECT  2.16 17.145 62.586 17.415 ;
     RECT  2.16 17.685 62.586 17.955 ;
     RECT  2.16 18.225 62.586 18.495 ;
     RECT  2.16 18.765 62.586 19.035 ;
     RECT  2.16 19.305 62.586 19.575 ;
     RECT  2.16 19.845 62.586 20.115 ;
     RECT  2.16 20.385 62.586 20.655 ;
     RECT  2.16 20.925 62.586 21.195 ;
     RECT  2.16 21.465 62.586 21.735 ;
     RECT  2.16 22.005 62.586 22.275 ;
     RECT  2.16 22.545 62.586 22.815 ;
     RECT  2.16 23.085 62.586 23.355 ;
     RECT  2.16 23.625 62.586 23.895 ;
     RECT  2.16 24.165 62.586 24.435 ;
     RECT  2.16 24.705 62.586 24.975 ;
     RECT  2.16 25.245 62.586 25.515 ;
     RECT  2.16 25.785 62.586 26.055 ;
     RECT  2.16 26.325 62.586 26.595 ;
     RECT  2.16 26.865 62.586 27.135 ;
     RECT  2.16 27.405 62.586 27.675 ;
     RECT  2.16 27.945 62.586 28.215 ;
     RECT  2.16 28.485 62.586 28.755 ;
     RECT  2.16 29.025 62.586 29.295 ;
     RECT  2.16 29.565 62.586 29.835 ;
     RECT  2.16 30.105 62.586 30.375 ;
     RECT  2.16 30.645 62.586 30.915 ;
     RECT  2.16 31.185 62.586 31.455 ;
     RECT  2.16 31.725 62.586 31.995 ;
     RECT  2.16 32.265 62.586 32.535 ;
     RECT  2.16 32.805 62.586 33.075 ;
     RECT  2.16 33.345 62.586 33.615 ;
     RECT  2.16 33.885 62.586 34.155 ;
     RECT  2.16 34.425 62.586 34.695 ;
     RECT  2.16 34.965 62.586 35.235 ;
     RECT  2.16 35.505 62.586 35.775 ;
     RECT  2.16 36.045 62.586 36.315 ;
     RECT  2.16 36.585 62.586 36.855 ;
     RECT  2.16 37.125 62.586 37.395 ;
     RECT  2.16 37.665 62.586 37.935 ;
     RECT  2.16 38.205 62.586 38.475 ;
     RECT  2.16 38.745 62.586 39.015 ;
     RECT  2.16 39.285 62.586 39.555 ;
     RECT  2.16 39.825 62.586 40.095 ;
     RECT  2.16 40.365 62.586 40.635 ;
     RECT  2.16 40.905 62.586 41.175 ;
     RECT  2.16 41.445 62.586 41.715 ;
     RECT  2.16 41.985 62.586 42.255 ;
     RECT  2.16 42.525 62.586 42.795 ;
     RECT  2.16 43.065 62.586 43.335 ;
     RECT  2.16 43.605 62.586 43.875 ;
     RECT  2.16 44.145 62.586 44.415 ;
     RECT  2.16 44.685 62.586 44.955 ;
     RECT  2.16 45.225 62.586 45.495 ;
     RECT  2.16 45.765 62.586 46.035 ;
     RECT  2.16 46.305 62.586 46.575 ;
     RECT  2.16 46.845 62.586 47.115 ;
     RECT  2.16 47.385 62.586 47.655 ;
     RECT  2.16 47.925 62.586 48.195 ;
     RECT  2.16 48.465 62.586 48.735 ;
     RECT  2.16 49.005 62.586 49.275 ;
     RECT  2.16 49.545 62.586 49.815 ;
     RECT  2.16 50.085 62.586 50.355 ;
     RECT  2.16 50.625 62.586 50.895 ;
     RECT  2.16 51.165 62.586 51.435 ;
     RECT  2.16 51.705 62.586 51.975 ;
     RECT  2.16 52.245 62.586 52.515 ;
     RECT  2.16 52.785 62.586 53.055 ;
     RECT  2.16 53.325 62.586 53.595 ;
     RECT  2.16 53.865 62.586 54.135 ;
     RECT  2.16 54.405 62.586 54.675 ;
     RECT  2.16 54.945 62.586 55.215 ;
     RECT  2.16 55.485 62.586 55.755 ;
     RECT  2.16 56.025 62.586 56.295 ;
     RECT  2.16 56.565 62.586 56.835 ;
     RECT  2.16 57.105 62.586 57.375 ;
     RECT  2.16 57.645 62.586 57.915 ;
     RECT  2.16 58.185 62.586 58.455 ;
     RECT  2.16 58.725 62.586 58.995 ;
     RECT  2.16 59.265 62.586 59.535 ;
     RECT  2.16 59.805 62.586 60.075 ;
     RECT  2.16 60.345 62.586 60.615 ;
     RECT  2.16 60.885 62.586 61.155 ;
     RECT  2.16 61.425 62.586 61.695 ;
     RECT  2.16 61.965 62.586 62.235 ;
     RECT  2.16 62.505 62.586 62.775 ;
     RECT  2.16 63.045 62.586 63.315 ;
     RECT  2.16 63.585 62.586 63.855 ;
     RECT  2.16 64.125 62.586 64.395 ;
     RECT  2.16 64.665 62.586 64.935 ;
     RECT  2.16 65.205 62.586 65.475 ;
     RECT  2.16 65.745 62.586 66.015 ;
     RECT  2.16 66.285 62.586 66.555 ;
     RECT  2.16 66.825 62.586 67.095 ;
     RECT  2.16 67.365 62.586 67.635 ;
     RECT  2.16 67.905 62.586 68.175 ;
     RECT  2.16 68.445 62.586 68.715 ;
     RECT  2.16 68.985 62.586 69.255 ;
     RECT  2.16 69.525 62.586 69.795 ;
     RECT  2.16 70.065 62.586 70.335 ;
     RECT  2.16 70.605 62.586 70.875 ;
     RECT  2.16 71.145 62.586 71.415 ;
     RECT  2.16 71.685 62.586 71.955 ;
     RECT  2.16 72.225 62.586 72.495 ;
     RECT  2.16 72.765 62.586 73.035 ;
     RECT  2.16 73.305 62.586 73.575 ;
     RECT  2.16 73.845 62.586 74.115 ;
     RECT  2.16 74.385 62.586 74.655 ;
     RECT  2.16 74.925 62.586 75.195 ;
     RECT  2.16 75.465 62.586 75.735 ;
     RECT  2.16 76.005 62.586 76.275 ;
     RECT  2.16 76.545 62.586 76.815 ;
     RECT  2.16 77.085 62.586 77.355 ;
     RECT  2.16 77.625 62.586 77.895 ;
     RECT  2.16 78.165 62.586 78.435 ;
     RECT  2.16 78.705 62.586 78.975 ;
     RECT  2.16 79.245 62.586 79.515 ;
     RECT  2.16 79.785 62.586 80.055 ;
     RECT  2.16 80.325 62.586 80.595 ;
     RECT  2.16 80.865 62.586 81.135 ;
     RECT  2.16 81.405 62.586 81.675 ;
     RECT  2.16 81.945 62.586 82.215 ;
     RECT  2.16 82.485 62.586 82.755 ;
     RECT  2.16 83.025 62.586 83.295 ;
     RECT  2.16 83.565 62.586 83.835 ;
     RECT  2.16 84.105 62.586 84.375 ;
     RECT  2.16 84.645 62.586 84.915 ;
     RECT  2.16 85.185 62.586 85.455 ;
     RECT  2.16 85.725 62.586 85.995 ;
     RECT  2.16 86.265 62.586 86.535 ;
     RECT  2.16 86.805 62.586 87.075 ;
     RECT  2.16 87.345 62.586 87.615 ;
     RECT  2.16 87.885 62.586 88.155 ;
     RECT  2.16 88.425 62.586 88.695 ;
     RECT  2.16 88.965 62.586 89.235 ;
     RECT  2.16 89.505 62.586 89.775 ;
     RECT  2.16 90.045 62.586 90.315 ;
     RECT  2.16 90.585 62.586 90.855 ;
     RECT  2.16 91.125 62.586 91.395 ;
     RECT  2.16 91.665 62.586 91.935 ;
     RECT  2.16 92.205 62.586 92.475 ;
     RECT  2.16 92.745 62.586 93.015 ;
     RECT  2.16 93.285 62.586 93.555 ;
     RECT  2.16 93.825 62.586 94.095 ;
     RECT  2.16 94.365 62.586 94.635 ;
     RECT  2.16 94.905 62.586 95.175 ;
     RECT  2.16 95.445 62.586 95.715 ;
     RECT  2.16 95.985 62.586 96.255 ;
     RECT  2.16 96.525 62.586 96.795 ;
     RECT  2.16 97.065 62.586 97.335 ;
     RECT  2.16 97.605 62.586 97.875 ;
     RECT  2.16 98.145 62.586 98.415 ;
     RECT  2.16 98.685 62.586 98.955 ;
     RECT  2.16 99.225 62.586 99.495 ;
     RECT  2.16 99.765 62.586 100.035 ;
     RECT  2.16 100.305 62.586 100.575 ;
     RECT  2.16 100.845 62.586 101.115 ;
     RECT  2.16 101.385 62.586 101.655 ;
     RECT  2.16 101.925 62.586 102.195 ;
     RECT  2.16 102.465 62.586 102.735 ;
     RECT  2.16 103.005 62.586 103.275 ;
    LAYER RVTP ;
     RECT  2.16 2.295 62.586 2.565 ;
     RECT  2.16 2.835 62.586 3.105 ;
     RECT  2.16 3.375 62.586 3.645 ;
     RECT  2.16 3.915 62.586 4.185 ;
     RECT  2.16 4.455 62.586 4.725 ;
     RECT  2.16 4.995 62.586 5.265 ;
     RECT  2.16 5.535 62.586 5.805 ;
     RECT  2.16 6.075 62.586 6.345 ;
     RECT  2.16 6.615 62.586 6.885 ;
     RECT  2.16 7.155 62.586 7.425 ;
     RECT  2.16 7.695 62.586 7.965 ;
     RECT  2.16 8.235 62.586 8.505 ;
     RECT  2.16 8.775 62.586 9.045 ;
     RECT  2.16 9.315 62.586 9.585 ;
     RECT  2.16 9.855 62.586 10.125 ;
     RECT  2.16 10.395 62.586 10.665 ;
     RECT  2.16 10.935 62.586 11.205 ;
     RECT  2.16 11.475 62.586 11.745 ;
     RECT  2.16 12.015 62.586 12.285 ;
     RECT  2.16 12.555 62.586 12.825 ;
     RECT  2.16 13.095 62.586 13.365 ;
     RECT  2.16 13.635 62.586 13.905 ;
     RECT  2.16 14.175 62.586 14.445 ;
     RECT  2.16 14.715 62.586 14.985 ;
     RECT  2.16 15.255 62.586 15.525 ;
     RECT  2.16 15.795 62.586 16.065 ;
     RECT  2.16 16.335 62.586 16.605 ;
     RECT  2.16 16.875 62.586 17.145 ;
     RECT  2.16 17.415 62.586 17.685 ;
     RECT  2.16 17.955 62.586 18.225 ;
     RECT  2.16 18.495 62.586 18.765 ;
     RECT  2.16 19.035 62.586 19.305 ;
     RECT  2.16 19.575 62.586 19.845 ;
     RECT  2.16 20.115 62.586 20.385 ;
     RECT  2.16 20.655 62.586 20.925 ;
     RECT  2.16 21.195 62.586 21.465 ;
     RECT  2.16 21.735 62.586 22.005 ;
     RECT  2.16 22.275 62.586 22.545 ;
     RECT  2.16 22.815 62.586 23.085 ;
     RECT  2.16 23.355 62.586 23.625 ;
     RECT  2.16 23.895 62.586 24.165 ;
     RECT  2.16 24.435 62.586 24.705 ;
     RECT  2.16 24.975 62.586 25.245 ;
     RECT  2.16 25.515 62.586 25.785 ;
     RECT  2.16 26.055 62.586 26.325 ;
     RECT  2.16 26.595 62.586 26.865 ;
     RECT  2.16 27.135 62.586 27.405 ;
     RECT  2.16 27.675 62.586 27.945 ;
     RECT  2.16 28.215 62.586 28.485 ;
     RECT  2.16 28.755 62.586 29.025 ;
     RECT  2.16 29.295 62.586 29.565 ;
     RECT  2.16 29.835 62.586 30.105 ;
     RECT  2.16 30.375 62.586 30.645 ;
     RECT  2.16 30.915 62.586 31.185 ;
     RECT  2.16 31.455 62.586 31.725 ;
     RECT  2.16 31.995 62.586 32.265 ;
     RECT  2.16 32.535 62.586 32.805 ;
     RECT  2.16 33.075 62.586 33.345 ;
     RECT  2.16 33.615 62.586 33.885 ;
     RECT  2.16 34.155 62.586 34.425 ;
     RECT  2.16 34.695 62.586 34.965 ;
     RECT  2.16 35.235 62.586 35.505 ;
     RECT  2.16 35.775 62.586 36.045 ;
     RECT  2.16 36.315 62.586 36.585 ;
     RECT  2.16 36.855 62.586 37.125 ;
     RECT  2.16 37.395 62.586 37.665 ;
     RECT  2.16 37.935 62.586 38.205 ;
     RECT  2.16 38.475 62.586 38.745 ;
     RECT  2.16 39.015 62.586 39.285 ;
     RECT  2.16 39.555 62.586 39.825 ;
     RECT  2.16 40.095 62.586 40.365 ;
     RECT  2.16 40.635 62.586 40.905 ;
     RECT  2.16 41.175 62.586 41.445 ;
     RECT  2.16 41.715 62.586 41.985 ;
     RECT  2.16 42.255 62.586 42.525 ;
     RECT  2.16 42.795 62.586 43.065 ;
     RECT  2.16 43.335 62.586 43.605 ;
     RECT  2.16 43.875 62.586 44.145 ;
     RECT  2.16 44.415 62.586 44.685 ;
     RECT  2.16 44.955 62.586 45.225 ;
     RECT  2.16 45.495 62.586 45.765 ;
     RECT  2.16 46.035 62.586 46.305 ;
     RECT  2.16 46.575 62.586 46.845 ;
     RECT  2.16 47.115 62.586 47.385 ;
     RECT  2.16 47.655 62.586 47.925 ;
     RECT  2.16 48.195 62.586 48.465 ;
     RECT  2.16 48.735 62.586 49.005 ;
     RECT  2.16 49.275 62.586 49.545 ;
     RECT  2.16 49.815 62.586 50.085 ;
     RECT  2.16 50.355 62.586 50.625 ;
     RECT  2.16 50.895 62.586 51.165 ;
     RECT  2.16 51.435 62.586 51.705 ;
     RECT  2.16 51.975 62.586 52.245 ;
     RECT  2.16 52.515 62.586 52.785 ;
     RECT  2.16 53.055 62.586 53.325 ;
     RECT  2.16 53.595 62.586 53.865 ;
     RECT  2.16 54.135 62.586 54.405 ;
     RECT  2.16 54.675 62.586 54.945 ;
     RECT  2.16 55.215 62.586 55.485 ;
     RECT  2.16 55.755 62.586 56.025 ;
     RECT  2.16 56.295 62.586 56.565 ;
     RECT  2.16 56.835 62.586 57.105 ;
     RECT  2.16 57.375 62.586 57.645 ;
     RECT  2.16 57.915 62.586 58.185 ;
     RECT  2.16 58.455 62.586 58.725 ;
     RECT  2.16 58.995 62.586 59.265 ;
     RECT  2.16 59.535 62.586 59.805 ;
     RECT  2.16 60.075 62.586 60.345 ;
     RECT  2.16 60.615 62.586 60.885 ;
     RECT  2.16 61.155 62.586 61.425 ;
     RECT  2.16 61.695 62.586 61.965 ;
     RECT  2.16 62.235 62.586 62.505 ;
     RECT  2.16 62.775 62.586 63.045 ;
     RECT  2.16 63.315 62.586 63.585 ;
     RECT  2.16 63.855 62.586 64.125 ;
     RECT  2.16 64.395 62.586 64.665 ;
     RECT  2.16 64.935 62.586 65.205 ;
     RECT  2.16 65.475 62.586 65.745 ;
     RECT  2.16 66.015 62.586 66.285 ;
     RECT  2.16 66.555 62.586 66.825 ;
     RECT  2.16 67.095 62.586 67.365 ;
     RECT  2.16 67.635 62.586 67.905 ;
     RECT  2.16 68.175 62.586 68.445 ;
     RECT  2.16 68.715 62.586 68.985 ;
     RECT  2.16 69.255 62.586 69.525 ;
     RECT  2.16 69.795 62.586 70.065 ;
     RECT  2.16 70.335 62.586 70.605 ;
     RECT  2.16 70.875 62.586 71.145 ;
     RECT  2.16 71.415 62.586 71.685 ;
     RECT  2.16 71.955 62.586 72.225 ;
     RECT  2.16 72.495 62.586 72.765 ;
     RECT  2.16 73.035 62.586 73.305 ;
     RECT  2.16 73.575 62.586 73.845 ;
     RECT  2.16 74.115 62.586 74.385 ;
     RECT  2.16 74.655 62.586 74.925 ;
     RECT  2.16 75.195 62.586 75.465 ;
     RECT  2.16 75.735 62.586 76.005 ;
     RECT  2.16 76.275 62.586 76.545 ;
     RECT  2.16 76.815 62.586 77.085 ;
     RECT  2.16 77.355 62.586 77.625 ;
     RECT  2.16 77.895 62.586 78.165 ;
     RECT  2.16 78.435 62.586 78.705 ;
     RECT  2.16 78.975 62.586 79.245 ;
     RECT  2.16 79.515 62.586 79.785 ;
     RECT  2.16 80.055 62.586 80.325 ;
     RECT  2.16 80.595 62.586 80.865 ;
     RECT  2.16 81.135 62.586 81.405 ;
     RECT  2.16 81.675 62.586 81.945 ;
     RECT  2.16 82.215 62.586 82.485 ;
     RECT  2.16 82.755 62.586 83.025 ;
     RECT  2.16 83.295 62.586 83.565 ;
     RECT  2.16 83.835 62.586 84.105 ;
     RECT  2.16 84.375 62.586 84.645 ;
     RECT  2.16 84.915 62.586 85.185 ;
     RECT  2.16 85.455 62.586 85.725 ;
     RECT  2.16 85.995 62.586 86.265 ;
     RECT  2.16 86.535 62.586 86.805 ;
     RECT  2.16 87.075 62.586 87.345 ;
     RECT  2.16 87.615 62.586 87.885 ;
     RECT  2.16 88.155 62.586 88.425 ;
     RECT  2.16 88.695 62.586 88.965 ;
     RECT  2.16 89.235 62.586 89.505 ;
     RECT  2.16 89.775 62.586 90.045 ;
     RECT  2.16 90.315 62.586 90.585 ;
     RECT  2.16 90.855 62.586 91.125 ;
     RECT  2.16 91.395 62.586 91.665 ;
     RECT  2.16 91.935 62.586 92.205 ;
     RECT  2.16 92.475 62.586 92.745 ;
     RECT  2.16 93.015 62.586 93.285 ;
     RECT  2.16 93.555 62.586 93.825 ;
     RECT  2.16 94.095 62.586 94.365 ;
     RECT  2.16 94.635 62.586 94.905 ;
     RECT  2.16 95.175 62.586 95.445 ;
     RECT  2.16 95.715 62.586 95.985 ;
     RECT  2.16 96.255 62.586 96.525 ;
     RECT  2.16 96.795 62.586 97.065 ;
     RECT  2.16 97.335 62.586 97.605 ;
     RECT  2.16 97.875 62.586 98.145 ;
     RECT  2.16 98.415 62.586 98.685 ;
     RECT  2.16 98.955 62.586 99.225 ;
     RECT  2.16 99.495 62.586 99.765 ;
     RECT  2.16 100.035 62.586 100.305 ;
     RECT  2.16 100.575 62.586 100.845 ;
     RECT  2.16 101.115 62.586 101.385 ;
     RECT  2.16 101.655 62.586 101.925 ;
     RECT  2.16 102.195 62.586 102.465 ;
     RECT  2.16 102.735 62.586 103.005 ;
     RECT  2.16 103.275 62.586 103.41 ;
    LAYER M1 ;
     RECT  2.16 2.151 62.586 103.419 ;
    LAYER M2 ;
     RECT  0.031 37.368 0.103 37.386 ;
     RECT  0.031 39.096 0.103 39.114 ;
     RECT  0.031 65.061 0.103 65.079 ;
     RECT  0.031 70.884 0.103 70.902 ;
     RECT  0.067 76.986 0.103 77.004 ;
     RECT  0.031 82.116 0.103 82.134 ;
     RECT  0.031 29.151 0.139 29.169 ;
     RECT  0.103 42.57 0.139 43.056 ;
     RECT  0.103 44.118 0.139 44.136 ;
     RECT  0.103 72.936 0.139 73.404 ;
     RECT  0.103 74.394 0.139 74.412 ;
     RECT  0.103 81.306 0.139 82.134 ;
     RECT  0.103 48.672 0.175 48.69 ;
     RECT  0.139 72.936 0.175 74.412 ;
     RECT  0.139 81.306 0.175 82.206 ;
     RECT  0.067 84.888 0.175 85.104 ;
     RECT  0.103 26.136 0.203 26.154 ;
     RECT  0.103 33.66 0.203 34.146 ;
     RECT  0.103 38.448 0.203 40.086 ;
     RECT  0.139 42.57 0.203 44.136 ;
     RECT  0.103 45.666 0.203 46.764 ;
     RECT  0.175 48.672 0.203 49.104 ;
     RECT  0.103 50.706 0.203 51.66 ;
     RECT  0.103 52.686 0.203 53.199 ;
     RECT  0.103 55.458 0.203 57.87 ;
     RECT  0.103 59.85 0.203 59.868 ;
     RECT  0.103 60.624 0.203 61.992 ;
     RECT  0.103 64.602 0.203 66.159 ;
     RECT  0.103 69.966 0.203 70.974 ;
     RECT  0.103 76.986 0.203 77.769 ;
     RECT  0.103 78.912 0.203 79.344 ;
     RECT  0.175 81.306 0.203 82.71 ;
     RECT  0.175 72.891 0.211 74.646 ;
     RECT  0.139 27.216 0.239 27.234 ;
     RECT  0.203 33.66 0.239 33.678 ;
     RECT  0.203 48.708 0.247 49.104 ;
     RECT  0.175 84.816 0.247 85.104 ;
     RECT  0.103 32.238 0.283 32.256 ;
     RECT  0.203 60.894 0.311 61.218 ;
     RECT  0.067 47.628 0.319 47.646 ;
     RECT  0.103 69.111 0.319 69.129 ;
     RECT  0.211 72.891 0.355 74.916 ;
     RECT  0.203 70.614 0.383 70.974 ;
     RECT  0.319 68.994 0.391 69.129 ;
     RECT  0.247 80.946 0.391 80.964 ;
     RECT  0.247 84.312 0.391 85.104 ;
     RECT  0.283 32.202 0.419 32.256 ;
     RECT  0.311 60.966 0.419 61.146 ;
     RECT  0.391 80.91 0.419 80.964 ;
     RECT  0.203 82.188 0.427 82.71 ;
     RECT  0.203 57.006 0.455 57.132 ;
     RECT  0.203 64.944 0.455 65.16 ;
     RECT  0.419 80.91 0.455 80.928 ;
     RECT  0.355 72.891 0.463 74.952 ;
     RECT  0.203 76.986 0.463 77.616 ;
     RECT  0.427 82.188 0.463 82.944 ;
     RECT  0.391 83.736 0.463 85.104 ;
     RECT  0.419 60.966 0.491 60.984 ;
     RECT  0.391 68.886 0.491 69.246 ;
     RECT  0.463 76.284 0.491 77.616 ;
     RECT  0.463 72.891 0.499 75.069 ;
     RECT  0.491 76.284 0.499 76.374 ;
     RECT  0.455 64.944 0.527 65.034 ;
     RECT  0.491 68.958 0.527 69.246 ;
     RECT  0.139 29.151 0.535 29.754 ;
     RECT  0.499 72.891 0.535 76.374 ;
     RECT  0.527 64.944 1.183 64.962 ;
     RECT  1.183 64.836 1.211 64.962 ;
     RECT  0.535 29.034 1.399 29.754 ;
     RECT  0.823 66.762 1.471 66.78 ;
     RECT  1.471 66.762 1.507 67.356 ;
     RECT  0.103 36.9 1.975 37.386 ;
     RECT  1.211 64.836 2.119 64.854 ;
     RECT  1.399 29.034 2.16 30.204 ;
     RECT  0.139 31.428 2.16 31.446 ;
     RECT  0.419 32.238 2.16 32.256 ;
     RECT  2.155 35.856 2.16 35.874 ;
     RECT  1.975 36.9 2.16 37.494 ;
     RECT  0.203 38.646 2.16 39.618 ;
     RECT  0.859 40.986 2.16 41.004 ;
     RECT  0.203 43.506 2.16 43.524 ;
     RECT  0.203 45.666 2.16 46.134 ;
     RECT  0.319 47.628 2.16 47.844 ;
     RECT  0.247 48.708 2.16 49.806 ;
     RECT  0.895 53.838 2.16 53.856 ;
     RECT  0.203 56.106 2.16 56.124 ;
     RECT  1.435 61.632 2.16 61.65 ;
     RECT  2.011 62.712 2.16 62.73 ;
     RECT  2.119 64.836 2.16 65.196 ;
     RECT  1.507 66.366 2.16 67.356 ;
     RECT  0.383 70.614 2.16 70.632 ;
     RECT  0.535 72.234 2.16 76.374 ;
     RECT  0.491 77.598 2.16 77.616 ;
     RECT  0.203 79.326 2.16 79.344 ;
     RECT  0.463 82.188 2.16 85.284 ;
     RECT  2.16 2.151 62.586 103.419 ;
     RECT  62.586 19.656 62.735 79.812 ;
     RECT  62.735 25.56 62.771 79.614 ;
     RECT  62.771 25.56 62.807 62.496 ;
     RECT  62.807 29.844 62.843 62.496 ;
     RECT  62.771 63.252 62.843 69.48 ;
     RECT  62.771 74.286 63.275 79.578 ;
     RECT  62.735 19.89 63.311 24.804 ;
     RECT  62.807 25.56 63.311 28.98 ;
     RECT  62.843 29.88 63.311 62.496 ;
     RECT  62.843 63.252 63.311 69.282 ;
     RECT  62.771 70.38 63.311 70.974 ;
     RECT  63.275 74.286 63.311 79.542 ;
     RECT  63.311 25.56 63.347 28.476 ;
     RECT  63.311 30.078 63.347 37.044 ;
     RECT  63.311 38.142 63.347 39.816 ;
     RECT  63.311 45.27 63.347 49.374 ;
     RECT  63.311 50.4 63.347 50.418 ;
     RECT  63.311 55.224 63.347 57.636 ;
     RECT  63.311 74.286 63.347 76.806 ;
     RECT  63.311 77.598 63.347 79.074 ;
     RECT  63.311 19.89 63.383 22.914 ;
     RECT  63.347 25.56 63.383 26.856 ;
     RECT  63.311 60.858 63.383 62.496 ;
     RECT  63.311 63.558 63.383 68.976 ;
     RECT  62.771 71.766 63.419 73.53 ;
     RECT  63.383 26.37 63.635 26.856 ;
     RECT  63.347 46.818 63.779 48.024 ;
     RECT  63.311 58.428 63.815 60.066 ;
     RECT  63.815 58.464 63.851 60.066 ;
     RECT  63.347 78.642 63.851 79.074 ;
     RECT  63.383 19.89 63.887 21.834 ;
     RECT  63.383 22.59 63.887 22.914 ;
     RECT  63.311 24.21 63.887 24.804 ;
     RECT  63.383 25.56 63.887 25.578 ;
     RECT  63.635 26.37 63.887 26.622 ;
     RECT  63.347 30.078 63.887 35.028 ;
     RECT  63.347 35.784 63.887 37.044 ;
     RECT  63.347 38.682 63.887 39.114 ;
     RECT  63.311 40.644 63.887 44.442 ;
     RECT  63.347 45.27 63.887 45.45 ;
     RECT  63.779 47.286 63.887 48.024 ;
     RECT  63.347 48.906 63.887 49.374 ;
     RECT  63.311 51.174 63.887 51.534 ;
     RECT  63.311 52.866 63.887 53.352 ;
     RECT  63.311 54.18 63.887 54.468 ;
     RECT  63.347 55.224 63.887 57.564 ;
     RECT  63.851 58.464 63.887 58.482 ;
     RECT  63.851 59.238 63.887 60.066 ;
     RECT  63.383 61.128 63.887 62.496 ;
     RECT  63.383 63.936 63.887 68.976 ;
     RECT  63.311 70.614 63.887 70.974 ;
     RECT  63.419 71.766 63.887 71.784 ;
     RECT  63.419 72.576 63.887 73.53 ;
     RECT  63.347 74.286 63.887 76.77 ;
     RECT  63.347 77.598 63.887 77.616 ;
     RECT  63.851 78.984 63.887 79.074 ;
     RECT  63.887 20.628 63.923 20.988 ;
     RECT  63.887 26.604 63.923 26.622 ;
     RECT  63.347 27.846 63.923 28.476 ;
     RECT  63.887 30.078 63.923 30.096 ;
     RECT  63.887 32.31 63.923 32.328 ;
     RECT  63.887 40.644 63.923 41.238 ;
     RECT  63.887 42.03 63.923 44.442 ;
     RECT  63.887 51.372 63.923 51.39 ;
     RECT  63.887 52.956 63.923 52.974 ;
     RECT  63.887 54.18 63.923 54.198 ;
     RECT  63.887 56.268 63.923 57.564 ;
     RECT  63.887 61.128 63.923 61.416 ;
     RECT  63.887 65.016 63.923 65.538 ;
     RECT  63.887 66.798 63.923 68.166 ;
     RECT  63.887 73.008 63.923 73.134 ;
     RECT  63.887 74.286 63.923 74.304 ;
     RECT  63.887 75.096 63.923 75.762 ;
     RECT  63.887 78.984 63.923 79.002 ;
     RECT  63.923 20.628 63.959 20.646 ;
     RECT  63.887 22.86 63.959 22.878 ;
     RECT  63.887 24.21 63.959 24.228 ;
     RECT  63.923 40.95 63.959 40.968 ;
     RECT  63.923 42.426 63.959 43.83 ;
     RECT  63.923 57.15 63.959 57.564 ;
     RECT  63.923 65.412 63.959 65.43 ;
     RECT  63.923 66.798 63.959 67.59 ;
     RECT  63.887 68.922 63.959 68.94 ;
     RECT  63.959 57.15 63.995 57.438 ;
     RECT  63.959 67.572 63.995 67.59 ;
     RECT  63.959 42.732 64.679 43.02 ;
     RECT  64.651 30.15 64.751 30.168 ;
     RECT  64.651 31.392 64.751 31.41 ;
     RECT  64.651 36.756 64.751 36.774 ;
     RECT  64.651 55.386 64.751 55.404 ;
     RECT  63.995 57.42 64.751 57.438 ;
     RECT  64.651 59.742 64.751 59.76 ;
     RECT  64.651 71.316 64.751 71.334 ;
    LAYER M3 ;
     RECT  2.415 2.143 2.505 2.413 ;
     RECT  5.115 2.143 5.205 2.413 ;
     RECT  7.815 2.143 7.905 2.413 ;
     RECT  10.515 2.143 10.605 2.413 ;
     RECT  13.215 2.143 13.305 2.413 ;
     RECT  15.915 2.143 16.005 2.413 ;
     RECT  18.615 2.143 18.705 2.413 ;
     RECT  21.315 2.143 21.405 2.413 ;
     RECT  24.015 2.143 24.105 2.413 ;
     RECT  26.715 2.143 26.805 2.413 ;
     RECT  29.415 2.143 29.505 2.413 ;
     RECT  32.115 2.143 32.205 2.413 ;
     RECT  34.815 2.143 34.905 2.413 ;
     RECT  37.515 2.143 37.605 2.413 ;
     RECT  40.215 2.143 40.305 2.413 ;
     RECT  42.915 2.143 43.005 2.413 ;
     RECT  45.615 2.143 45.705 2.413 ;
     RECT  48.315 2.143 48.405 2.413 ;
     RECT  51.015 2.143 51.105 2.413 ;
     RECT  53.715 2.143 53.805 2.413 ;
     RECT  56.415 2.143 56.505 2.413 ;
     RECT  59.115 2.143 59.205 2.413 ;
     RECT  61.815 2.143 61.905 2.413 ;
     RECT  61.815 2.413 62.097 19.651 ;
     RECT  59.115 2.413 59.397 19.915 ;
     RECT  59.115 19.915 59.742 19.921 ;
     RECT  60.48 19.915 60.498 19.921 ;
     RECT  61.815 19.651 62.73 20.011 ;
     RECT  63.864 19.885 63.882 20.011 ;
     RECT  58.752 19.921 59.742 20.119 ;
     RECT  60.48 19.921 60.678 20.119 ;
     RECT  58.752 20.119 60.678 20.155 ;
     RECT  54.828 20.083 54.846 20.191 ;
     RECT  56.415 2.413 56.697 20.191 ;
     RECT  58.104 20.155 60.678 20.191 ;
     RECT  61.815 20.011 63.882 20.191 ;
     RECT  58.104 20.191 63.882 20.281 ;
     RECT  30.528 20.191 30.546 20.309 ;
     RECT  3.924 20.011 3.942 20.353 ;
     RECT  54.792 20.191 54.846 20.353 ;
     RECT  55.656 20.155 55.674 20.353 ;
     RECT  56.412 20.191 56.754 20.353 ;
     RECT  57.78 20.281 63.882 20.587 ;
     RECT  3.924 20.353 3.978 20.623 ;
     RECT  57.672 20.587 63.918 20.623 ;
     RECT  54.72 20.353 54.846 20.695 ;
     RECT  55.656 20.353 56.754 20.695 ;
     RECT  57.672 20.623 63.954 20.813 ;
     RECT  57.672 20.813 63.918 20.993 ;
     RECT  54.72 20.695 56.754 21.001 ;
     RECT  3.744 20.623 3.978 21.199 ;
     RECT  3.456 21.199 3.978 21.271 ;
     RECT  54.72 21.001 56.934 21.271 ;
     RECT  57.672 20.993 63.882 21.271 ;
     RECT  54.72 21.271 63.882 21.299 ;
     RECT  15.048 21.271 15.066 21.389 ;
     RECT  22.788 21.361 22.806 21.461 ;
     RECT  2.415 2.413 2.697 21.541 ;
     RECT  3.456 21.271 4.338 21.541 ;
     RECT  54.72 21.299 55.638 21.659 ;
     RECT  56.415 21.299 63.882 21.659 ;
     RECT  29.415 2.413 29.697 21.811 ;
     RECT  56.415 21.659 57.366 21.821 ;
     RECT  28.872 21.811 29.697 21.929 ;
     RECT  13.215 2.413 13.497 21.937 ;
     RECT  29.016 21.929 29.697 22.001 ;
     RECT  13.215 21.937 14.022 22.037 ;
     RECT  55.26 21.659 55.638 22.045 ;
     RECT  56.415 21.821 57.294 22.045 ;
     RECT  12.24 22.009 12.258 22.081 ;
     RECT  13.215 22.037 13.497 22.081 ;
     RECT  58.104 21.659 63.882 22.157 ;
     RECT  47.34 22.351 47.358 22.441 ;
     RECT  48.315 2.413 48.597 22.441 ;
     RECT  55.26 22.045 57.294 22.441 ;
     RECT  47.34 22.441 48.597 22.469 ;
     RECT  55.224 22.441 57.294 22.549 ;
     RECT  5.115 2.413 5.397 22.621 ;
     RECT  2.415 21.541 4.338 22.711 ;
     RECT  5.115 22.621 5.454 22.711 ;
     RECT  58.104 22.157 62.226 22.711 ;
     RECT  47.808 22.469 48.597 22.781 ;
     RECT  51.015 2.413 51.297 22.855 ;
     RECT  63.252 22.157 63.882 22.855 ;
     RECT  51.015 22.855 51.354 22.891 ;
     RECT  54.72 22.549 57.294 22.981 ;
     RECT  58.068 22.711 62.226 22.981 ;
     RECT  54.72 22.981 62.226 22.987 ;
     RECT  63.252 22.855 63.954 22.987 ;
     RECT  50.508 22.891 51.354 23.009 ;
     RECT  12.24 22.081 13.497 23.251 ;
     RECT  50.616 23.009 51.354 23.279 ;
     RECT  53.715 2.413 53.997 23.323 ;
     RECT  53.28 23.323 53.997 23.701 ;
     RECT  54.72 22.987 63.954 23.701 ;
     RECT  50.616 23.279 51.297 23.855 ;
     RECT  48.315 22.781 48.597 24.205 ;
     RECT  53.28 23.701 63.954 24.221 ;
     RECT  56.415 24.221 63.954 24.233 ;
     RECT  10.515 2.413 10.797 24.241 ;
     RECT  11.664 23.251 13.497 24.241 ;
     RECT  40.215 2.413 40.497 24.331 ;
     RECT  52.164 23.251 52.182 24.781 ;
     RECT  53.28 24.221 55.602 24.781 ;
     RECT  52.164 24.781 55.602 25.141 ;
     RECT  56.415 24.233 63.882 25.141 ;
     RECT  37.515 2.413 37.797 25.249 ;
     RECT  41.292 24.709 41.31 25.321 ;
     RECT  33.732 25.285 33.75 25.439 ;
     RECT  42.915 2.413 43.197 25.447 ;
     RECT  52.164 25.141 63.882 25.52 ;
     RECT  32.115 2.413 32.397 25.591 ;
     RECT  2.415 22.711 5.454 25.951 ;
     RECT  63.252 25.52 63.882 26.123 ;
     RECT  0.18 26.107 0.198 26.131 ;
     RECT  0.108 26.131 0.198 26.159 ;
     RECT  63.612 26.123 63.882 26.251 ;
     RECT  52.164 25.52 62.442 26.293 ;
     RECT  15.12 21.541 15.138 26.329 ;
     RECT  15.915 2.413 16.197 26.329 ;
     RECT  15.12 26.329 16.197 26.491 ;
     RECT  21.315 2.413 21.597 26.491 ;
     RECT  26.715 2.413 26.997 26.491 ;
     RECT  34.815 2.413 35.097 26.527 ;
     RECT  21.204 26.491 21.597 26.563 ;
     RECT  31.068 25.861 31.194 26.587 ;
     RECT  52.164 26.293 62.73 26.599 ;
     RECT  63.612 26.251 63.918 26.627 ;
     RECT  34.632 26.527 35.097 26.635 ;
     RECT  31.068 26.587 31.374 26.671 ;
     RECT  42.915 25.447 43.65 26.671 ;
     RECT  30.816 26.671 31.374 26.779 ;
     RECT  32.115 25.591 32.598 26.779 ;
     RECT  42.84 26.671 43.65 26.789 ;
     RECT  52.02 26.599 62.73 26.825 ;
     RECT  30.816 26.779 32.598 26.827 ;
     RECT  63.612 26.627 63.63 26.861 ;
     RECT  22.392 22.009 22.41 26.923 ;
     RECT  23.184 23.125 23.202 26.923 ;
     RECT  52.128 26.825 62.73 26.923 ;
     RECT  26.676 26.491 26.997 26.941 ;
     RECT  6.84 26.491 6.858 26.957 ;
     RECT  14.832 26.491 16.197 26.969 ;
     RECT  0.108 26.159 0.126 27.019 ;
     RECT  52.128 26.923 62.766 27.019 ;
     RECT  30.816 26.827 32.67 27.067 ;
     RECT  26.64 26.941 26.997 27.1 ;
     RECT  20.808 26.563 21.597 27.163 ;
     RECT  22.392 26.923 23.202 27.163 ;
     RECT  29.415 22.001 29.697 27.163 ;
     RECT  30.816 27.067 32.994 27.163 ;
     RECT  26.604 27.1 26.997 27.197 ;
     RECT  50.148 26.599 50.166 27.203 ;
     RECT  2.304 25.951 5.454 27.301 ;
     RECT  51.015 23.855 51.297 27.337 ;
     RECT  14.832 26.969 15.138 27.341 ;
     RECT  26.712 27.197 26.997 27.341 ;
     RECT  30.78 27.163 33.174 27.403 ;
     RECT  52.128 27.019 62.838 27.403 ;
     RECT  45.615 2.413 45.897 27.445 ;
     RECT  29.415 27.163 29.79 27.451 ;
     RECT  17.82 22.441 17.838 27.481 ;
     RECT  18.615 2.413 18.897 27.481 ;
     RECT  0.108 27.019 0.342 27.629 ;
     RECT  51.015 27.337 51.318 27.635 ;
     RECT  51.015 27.635 51.297 27.643 ;
     RECT  29.415 27.451 29.898 27.677 ;
     RECT  52.128 27.403 63.342 27.691 ;
     RECT  41.292 25.321 41.958 27.751 ;
     RECT  42.876 26.789 43.65 27.751 ;
     RECT  29.415 27.677 29.79 27.773 ;
     RECT  2.304 27.301 5.49 27.779 ;
     RECT  50.724 27.643 51.297 27.779 ;
     RECT  52.128 27.691 63.882 27.787 ;
     RECT  34.632 26.635 35.154 27.883 ;
     RECT  48.315 24.205 49.302 27.913 ;
     RECT  20.808 27.163 23.202 27.917 ;
     RECT  30.78 27.403 33.318 27.917 ;
     RECT  26.715 27.341 26.997 28.111 ;
     RECT  37.515 25.249 38.502 28.111 ;
     RECT  6.84 27.979 6.858 28.123 ;
     RECT  14.94 27.341 15.138 28.123 ;
     RECT  37.515 28.111 38.79 28.211 ;
     RECT  34.596 27.883 35.154 28.219 ;
     RECT  6.84 28.123 6.966 28.253 ;
     RECT  26.676 28.111 26.997 28.253 ;
     RECT  41.292 27.751 43.65 28.255 ;
     RECT  44.712 24.367 44.73 28.255 ;
     RECT  45.54 27.445 45.897 28.255 ;
     RECT  14.832 28.123 15.138 28.301 ;
     RECT  2.304 27.779 5.454 28.319 ;
     RECT  45.54 28.255 45.954 28.409 ;
     RECT  2.412 28.319 5.454 28.445 ;
     RECT  22.392 27.917 23.202 28.445 ;
     RECT  50.796 27.779 51.297 28.445 ;
     RECT  52.128 27.787 63.918 28.481 ;
     RECT  41.292 28.255 44.73 28.525 ;
     RECT  45.54 28.409 45.897 28.525 ;
     RECT  41.292 28.525 45.897 28.679 ;
     RECT  15.915 26.969 16.197 28.759 ;
     RECT  10.515 24.241 13.497 28.921 ;
     RECT  0.108 27.629 0.126 29.029 ;
     RECT  24.015 2.413 24.297 29.029 ;
     RECT  0.108 29.029 0.558 29.146 ;
     RECT  0.036 29.146 0.558 29.165 ;
     RECT  47.016 24.169 47.034 29.227 ;
     RECT  8.82 20.317 8.838 29.323 ;
     RECT  9.936 28.921 13.497 29.323 ;
     RECT  15.12 28.301 15.138 29.323 ;
     RECT  20.808 27.917 21.597 29.323 ;
     RECT  22.392 28.445 22.41 29.323 ;
     RECT  41.292 28.679 44.73 29.371 ;
     RECT  6.516 28.291 6.534 29.467 ;
     RECT  7.815 2.413 8.097 29.467 ;
     RECT  23.184 28.445 23.202 29.467 ;
     RECT  24.015 29.029 24.93 29.467 ;
     RECT  29.415 27.773 29.697 29.467 ;
     RECT  30.816 27.917 33.318 29.467 ;
     RECT  37.515 28.211 38.502 29.467 ;
     RECT  45.615 28.679 45.897 29.467 ;
     RECT  14.832 29.323 15.138 29.501 ;
     RECT  29.415 29.467 29.79 29.515 ;
     RECT  41.22 29.371 44.73 29.525 ;
     RECT  28.764 29.515 29.79 29.597 ;
     RECT  30.78 29.467 33.318 29.597 ;
     RECT  23.184 29.467 24.93 29.611 ;
     RECT  41.292 29.525 44.73 29.641 ;
     RECT  45.615 29.467 45.99 29.641 ;
     RECT  41.292 29.641 45.99 29.803 ;
     RECT  46.764 29.227 47.034 29.803 ;
     RECT  41.292 29.803 47.034 29.831 ;
     RECT  52.128 28.481 63.882 29.899 ;
     RECT  19.728 21.541 19.746 30.043 ;
     RECT  20.808 29.323 22.41 30.043 ;
     RECT  23.184 29.611 25.434 30.065 ;
     RECT  52.128 29.899 63.918 30.101 ;
     RECT  37.515 29.467 38.79 30.109 ;
     RECT  39.6 24.331 40.497 30.109 ;
     RECT  64.728 30.136 64.746 30.145 ;
     RECT  64.656 30.145 64.746 30.173 ;
     RECT  1.44 29.899 1.458 30.181 ;
     RECT  64.656 30.173 64.674 30.221 ;
     RECT  2.415 28.445 5.454 30.271 ;
     RECT  15.12 29.501 15.138 30.283 ;
     RECT  17.82 27.481 18.897 30.283 ;
     RECT  19.728 30.043 22.41 30.283 ;
     RECT  2.304 30.271 5.454 30.317 ;
     RECT  17.82 30.283 22.41 30.413 ;
     RECT  8.82 29.323 13.497 30.541 ;
     RECT  23.22 30.065 25.434 30.571 ;
     RECT  26.715 28.253 26.997 30.571 ;
     RECT  36.756 29.911 36.774 30.577 ;
     RECT  37.515 30.109 40.497 30.577 ;
     RECT  17.82 30.413 18.954 30.653 ;
     RECT  52.128 30.101 63.882 30.749 ;
     RECT  31.14 29.597 33.318 30.811 ;
     RECT  34.056 28.219 35.154 30.811 ;
     RECT  19.728 30.413 22.41 30.955 ;
     RECT  23.22 30.571 26.997 30.955 ;
     RECT  1.404 30.181 1.458 31.051 ;
     RECT  2.415 30.317 5.454 31.051 ;
     RECT  64.656 31.339 64.674 31.387 ;
     RECT  64.656 31.387 64.746 31.415 ;
     RECT  64.728 31.415 64.746 31.424 ;
     RECT  1.404 31.051 5.454 31.621 ;
     RECT  8.82 30.541 13.95 31.621 ;
     RECT  14.832 30.283 15.138 31.621 ;
     RECT  52.128 30.749 62.097 31.627 ;
     RECT  62.928 30.749 63.882 31.627 ;
     RECT  36.756 30.577 40.497 31.657 ;
     RECT  48.315 27.913 49.662 31.999 ;
     RECT  15.915 28.759 16.83 32.011 ;
     RECT  17.82 30.653 18.897 32.011 ;
     RECT  52.128 31.627 63.882 32.011 ;
     RECT  51.015 28.445 51.297 32.071 ;
     RECT  0.036 29.165 0.162 32.107 ;
     RECT  48.096 31.999 49.662 32.189 ;
     RECT  1.404 31.621 5.49 32.233 ;
     RECT  6.516 29.467 8.097 32.233 ;
     RECT  0.036 32.107 0.486 32.237 ;
     RECT  28.008 30.667 28.026 32.251 ;
     RECT  36.288 31.657 40.497 32.251 ;
     RECT  0.036 32.237 0.414 32.285 ;
     RECT  48.315 32.189 49.662 32.305 ;
     RECT  50.688 32.071 51.297 32.305 ;
     RECT  52.128 32.011 63.918 32.333 ;
     RECT  45.615 29.831 47.034 32.341 ;
     RECT  8.82 31.621 15.138 32.431 ;
     RECT  15.915 32.011 18.897 32.431 ;
     RECT  27.756 32.251 28.026 32.779 ;
     RECT  28.764 29.597 29.697 32.779 ;
     RECT  48.315 32.305 51.297 32.881 ;
     RECT  52.128 32.333 63.882 32.881 ;
     RECT  8.82 32.431 18.897 33.008 ;
     RECT  27.756 32.779 29.697 33.019 ;
     RECT  48.315 32.881 63.882 33.035 ;
     RECT  19.728 30.955 26.997 33.067 ;
     RECT  27.756 33.019 30.366 33.067 ;
     RECT  45.615 32.341 47.106 33.115 ;
     RECT  48.315 33.035 51.297 33.115 ;
     RECT  0.036 32.285 0.054 33.163 ;
     RECT  19.728 33.067 30.366 33.349 ;
     RECT  31.14 30.811 35.154 33.349 ;
     RECT  45.615 33.115 51.297 33.413 ;
     RECT  45.615 33.413 47.358 33.539 ;
     RECT  0.036 33.163 0.162 33.655 ;
     RECT  48.315 33.413 51.297 33.961 ;
     RECT  48.315 33.961 51.354 34.079 ;
     RECT  0.036 33.655 0.234 34.109 ;
     RECT  52.128 33.035 63.882 34.159 ;
     RECT  0.036 34.109 0.198 34.397 ;
     RECT  19.728 33.349 35.154 34.735 ;
     RECT  19.728 34.735 35.334 34.897 ;
     RECT  0.036 34.397 0.162 34.973 ;
     RECT  48.315 34.079 51.297 35.131 ;
     RECT  52.02 34.159 63.882 35.131 ;
     RECT  1.404 32.233 8.097 35.371 ;
     RECT  19.728 34.897 35.442 35.437 ;
     RECT  36.18 32.251 40.497 35.437 ;
     RECT  41.292 29.831 44.838 35.509 ;
     RECT  45.615 33.539 47.106 35.509 ;
     RECT  19.728 35.437 40.497 35.699 ;
     RECT  36.18 35.699 40.497 35.743 ;
     RECT  41.292 35.509 47.106 35.743 ;
     RECT  19.728 35.699 35.19 35.879 ;
     RECT  0.036 34.973 0.054 36.139 ;
     RECT  0.828 35.371 8.097 36.139 ;
     RECT  64.656 36.715 64.674 36.751 ;
     RECT  64.656 36.751 64.746 36.779 ;
     RECT  64.728 36.779 64.746 36.797 ;
     RECT  15.915 33.008 18.897 37.093 ;
     RECT  19.728 35.879 35.154 37.093 ;
     RECT  8.82 33.008 15.138 37.291 ;
     RECT  15.915 37.093 35.154 37.291 ;
     RECT  8.82 37.291 35.154 37.328 ;
     RECT  0.036 36.139 8.097 37.391 ;
     RECT  15.915 37.328 35.154 37.589 ;
     RECT  0.324 37.391 8.097 37.613 ;
     RECT  19.656 37.589 35.154 37.867 ;
     RECT  19.656 37.867 35.19 37.903 ;
     RECT  19.656 37.903 35.226 38.281 ;
     RECT  0.576 37.613 8.097 38.347 ;
     RECT  0.216 38.347 8.097 38.428 ;
     RECT  19.656 38.281 35.334 38.429 ;
     RECT  19.656 38.429 35.298 38.543 ;
     RECT  36.18 35.743 47.106 38.713 ;
     RECT  8.82 37.328 15.138 38.749 ;
     RECT  36.18 38.713 47.142 39.055 ;
     RECT  0.108 38.428 8.097 39.091 ;
     RECT  19.656 38.543 35.262 39.119 ;
     RECT  19.656 39.119 35.19 39.209 ;
     RECT  48.315 35.131 63.882 39.245 ;
     RECT  15.915 37.589 18.897 40.027 ;
     RECT  15.915 40.027 18.918 40.123 ;
     RECT  19.656 39.209 35.154 40.123 ;
     RECT  15.915 40.123 35.154 40.135 ;
     RECT  15.915 40.135 35.262 40.325 ;
     RECT  8.82 38.749 15.174 40.405 ;
     RECT  15.915 40.325 18.897 40.405 ;
     RECT  8.82 40.405 18.897 40.445 ;
     RECT  48.315 39.245 63.342 40.639 ;
     RECT  48.315 40.639 63.918 40.901 ;
     RECT  63.144 40.901 63.918 40.945 ;
     RECT  63.144 40.945 63.954 41.453 ;
     RECT  63.18 41.453 63.954 41.477 ;
     RECT  19.656 40.325 35.262 41.485 ;
     RECT  36.18 39.055 47.574 41.485 ;
     RECT  48.315 40.901 62.19 41.989 ;
     RECT  8.82 40.445 15.174 42.043 ;
     RECT  15.915 40.445 18.897 42.043 ;
     RECT  8.82 42.043 18.897 42.089 ;
     RECT  48.315 41.989 62.37 42.379 ;
     RECT  63.252 41.477 63.954 42.379 ;
     RECT  48.315 42.379 63.954 42.521 ;
     RECT  63.252 42.521 63.954 42.727 ;
     RECT  48.315 42.521 62.37 42.863 ;
     RECT  63.252 42.727 64.674 43.025 ;
     RECT  8.82 42.089 15.174 43.231 ;
     RECT  15.915 42.089 18.897 43.231 ;
     RECT  8.82 43.231 18.897 43.277 ;
     RECT  63.252 43.025 63.954 43.331 ;
     RECT  48.315 42.863 62.097 43.609 ;
     RECT  63.864 43.331 63.954 43.835 ;
     RECT  63.864 43.835 63.918 44.107 ;
     RECT  48.315 43.609 62.766 44.299 ;
     RECT  63.828 44.107 63.918 44.299 ;
     RECT  48.315 44.299 63.918 44.447 ;
     RECT  19.656 41.485 47.574 44.683 ;
     RECT  48.315 44.447 63.882 44.683 ;
     RECT  19.656 44.683 63.882 44.909 ;
     RECT  48.315 44.909 63.882 45.485 ;
     RECT  19.656 44.909 47.574 45.805 ;
     RECT  48.315 45.485 63.342 45.805 ;
     RECT  8.82 43.277 15.174 45.931 ;
     RECT  15.915 43.277 18.897 45.931 ;
     RECT  8.82 45.931 18.897 45.968 ;
     RECT  19.656 45.805 63.342 46.603 ;
     RECT  19.656 46.603 63.774 46.891 ;
     RECT  8.82 45.968 15.174 47.047 ;
     RECT  15.915 45.968 18.897 47.047 ;
     RECT  8.82 47.047 18.897 47.551 ;
     RECT  8.82 47.551 18.918 47.651 ;
     RECT  19.656 46.891 63.882 49.517 ;
     RECT  19.656 49.517 63.306 50.347 ;
     RECT  19.656 50.347 63.342 50.443 ;
     RECT  19.656 50.443 63.882 51.196 ;
     RECT  19.656 51.196 63.918 51.395 ;
     RECT  19.656 51.395 63.882 52.241 ;
     RECT  63.288 52.241 63.882 52.555 ;
     RECT  63.288 52.555 63.918 52.979 ;
     RECT  19.656 52.241 62.226 53.323 ;
     RECT  63.288 52.979 63.882 53.323 ;
     RECT  19.656 53.323 63.882 53.933 ;
     RECT  63.864 53.933 63.882 54.175 ;
     RECT  63.864 54.175 63.918 54.413 ;
     RECT  19.656 53.933 62.802 54.667 ;
     RECT  63.864 54.413 63.882 54.667 ;
     RECT  64.656 55.339 64.674 55.381 ;
     RECT  64.656 55.381 64.746 55.409 ;
     RECT  64.728 55.409 64.746 55.421 ;
     RECT  19.656 54.667 63.882 56.263 ;
     RECT  0.036 39.091 8.097 56.371 ;
     RECT  8.82 47.651 18.897 56.371 ;
     RECT  0.036 56.371 18.897 56.429 ;
     RECT  19.656 56.263 63.918 57.145 ;
     RECT  19.656 57.145 63.99 57.415 ;
     RECT  64.728 57.403 64.746 57.415 ;
     RECT  19.656 57.415 64.746 57.437 ;
     RECT  63.324 57.437 64.746 57.443 ;
     RECT  63.324 57.443 64.674 57.485 ;
     RECT  63.324 57.485 63.954 57.569 ;
     RECT  19.656 57.437 62.097 58.225 ;
     RECT  63.324 57.569 63.342 58.261 ;
     RECT  63.288 58.261 63.342 58.315 ;
     RECT  63.288 58.315 63.882 58.487 ;
     RECT  19.656 58.225 62.154 58.765 ;
     RECT  63.288 58.487 63.846 58.765 ;
     RECT  19.656 58.765 63.846 59.233 ;
     RECT  64.728 59.707 64.746 59.737 ;
     RECT  64.656 59.737 64.746 59.765 ;
     RECT  64.656 59.765 64.674 59.789 ;
     RECT  19.656 59.233 63.882 60.071 ;
     RECT  19.656 60.071 63.306 60.853 ;
     RECT  19.656 60.853 63.378 61.099 ;
     RECT  19.656 61.099 63.882 61.123 ;
     RECT  19.656 61.123 63.918 61.613 ;
     RECT  8.82 56.429 18.897 61.723 ;
     RECT  19.656 61.613 63.882 61.723 ;
     RECT  8.82 61.723 63.882 61.853 ;
     RECT  19.656 61.853 63.882 62.285 ;
     RECT  63.864 62.285 63.882 62.765 ;
     RECT  19.656 62.285 62.766 63.247 ;
     RECT  19.656 63.247 63.306 63.553 ;
     RECT  19.656 63.553 63.378 63.931 ;
     RECT  19.656 63.931 63.882 64.391 ;
     RECT  63.252 64.391 63.882 64.733 ;
     RECT  63.288 64.733 63.882 65.011 ;
     RECT  0.036 56.429 8.097 65.084 ;
     RECT  63.288 65.011 63.918 65.407 ;
     RECT  19.656 64.391 62.097 65.479 ;
     RECT  63.288 65.407 63.954 65.479 ;
     RECT  19.656 65.479 63.954 65.645 ;
     RECT  19.656 65.645 63.882 66.701 ;
     RECT  63.252 66.701 63.882 66.793 ;
     RECT  63.252 66.793 63.954 67.564 ;
     RECT  19.656 66.701 62.097 67.567 ;
     RECT  63.252 67.564 63.99 67.567 ;
     RECT  19.656 67.567 63.99 67.757 ;
     RECT  19.656 67.757 63.918 67.949 ;
     RECT  29.088 67.949 63.918 68.243 ;
     RECT  29.088 68.243 37.797 68.279 ;
     RECT  29.268 68.279 37.797 68.405 ;
     RECT  8.82 61.853 18.897 68.731 ;
     RECT  19.656 67.949 28.35 68.731 ;
     RECT  38.556 68.243 63.918 68.917 ;
     RECT  8.82 68.731 28.35 68.957 ;
     RECT  38.556 68.917 63.954 69.197 ;
     RECT  19.656 68.957 28.35 69.259 ;
     RECT  38.556 69.197 63.306 69.293 ;
     RECT  19.656 69.259 28.494 69.331 ;
     RECT  29.34 68.405 37.797 69.331 ;
     RECT  19.656 69.331 37.797 69.485 ;
     RECT  29.415 69.485 37.797 69.755 ;
     RECT  19.656 69.485 28.53 69.899 ;
     RECT  38.556 69.293 62.838 69.899 ;
     RECT  38.556 69.899 52.218 70.097 ;
     RECT  53.028 69.899 62.838 70.219 ;
     RECT  34.164 69.755 37.797 70.301 ;
     RECT  38.592 70.097 52.218 70.403 ;
     RECT  53.028 70.219 63.306 70.411 ;
     RECT  0.072 65.084 8.097 70.879 ;
     RECT  53.028 70.411 63.882 70.943 ;
     RECT  19.656 69.899 28.494 71.041 ;
     RECT  29.415 69.755 33.426 71.041 ;
     RECT  19.656 71.041 33.426 71.069 ;
     RECT  53.028 70.943 62.766 71.249 ;
     RECT  64.656 71.275 64.674 71.311 ;
     RECT  64.656 71.311 64.746 71.339 ;
     RECT  64.728 71.339 64.746 71.357 ;
     RECT  34.272 70.301 37.797 71.717 ;
     RECT  38.592 70.403 48.726 71.753 ;
     RECT  53.064 71.249 62.766 71.755 ;
     RECT  63.864 70.943 63.882 71.755 ;
     RECT  8.82 68.957 18.897 71.851 ;
     RECT  19.656 71.069 33.354 71.851 ;
     RECT  38.628 71.753 48.726 71.951 ;
     RECT  8.82 71.851 33.354 71.981 ;
     RECT  53.064 71.755 63.882 72.031 ;
     RECT  29.415 71.981 33.354 72.149 ;
     RECT  0.036 70.879 8.097 72.173 ;
     RECT  8.82 71.981 28.35 72.173 ;
     RECT  29.415 72.149 30.582 72.257 ;
     RECT  19.656 72.173 28.35 72.461 ;
     RECT  38.628 71.951 39.222 72.491 ;
     RECT  0.036 72.173 0.558 72.557 ;
     RECT  38.628 72.491 38.646 72.725 ;
     RECT  53.028 72.031 63.882 72.959 ;
     RECT  53.424 72.959 63.882 72.997 ;
     RECT  31.32 72.149 33.354 73.003 ;
     RECT  30.78 73.003 33.354 73.037 ;
     RECT  34.272 71.717 36.27 73.139 ;
     RECT  0.036 72.557 0.45 73.309 ;
     RECT  29.415 72.257 30.042 73.373 ;
     RECT  30.78 73.037 32.994 73.373 ;
     RECT  53.424 72.997 63.918 73.421 ;
     RECT  0.036 73.309 0.522 73.471 ;
     RECT  8.82 72.173 18.897 73.499 ;
     RECT  30.78 73.373 32.397 73.517 ;
     RECT  34.272 73.139 35.694 73.613 ;
     RECT  19.656 72.461 27.918 73.913 ;
     RECT  40.215 71.951 48.726 73.949 ;
     RECT  49.896 70.403 52.218 74.183 ;
     RECT  53.424 73.421 63.882 74.251 ;
     RECT  53.424 74.251 63.918 74.309 ;
     RECT  37.296 71.717 37.797 74.417 ;
     RECT  41.328 73.949 48.726 74.453 ;
     RECT  42.444 74.453 48.726 74.957 ;
     RECT  49.896 74.183 51.642 75.029 ;
     RECT  53.424 74.309 63.882 75.091 ;
     RECT  49.896 75.029 49.914 75.119 ;
     RECT  50.724 75.029 51.642 75.119 ;
     RECT  42.444 74.957 46.458 75.533 ;
     RECT  42.768 75.533 46.458 75.569 ;
     RECT  47.592 74.957 48.726 75.659 ;
     RECT  34.815 73.613 35.694 75.695 ;
     RECT  42.768 75.569 44.802 75.767 ;
     RECT  47.844 75.659 48.726 75.767 ;
     RECT  53.424 75.091 63.918 75.821 ;
     RECT  1.404 72.173 8.097 76.109 ;
     RECT  45.615 75.569 46.458 76.199 ;
     RECT  41.328 74.453 41.346 76.271 ;
     RECT  1.98 76.109 8.097 76.397 ;
     RECT  0.036 73.471 0.558 76.493 ;
     RECT  42.915 75.767 44.802 76.577 ;
     RECT  2.415 76.397 8.097 76.649 ;
     RECT  53.424 75.821 63.882 76.775 ;
     RECT  53.424 76.775 63.342 76.811 ;
     RECT  53.424 76.811 63.306 77.009 ;
     RECT  8.856 73.499 18.897 77.117 ;
     RECT  5.115 76.649 8.097 77.309 ;
     RECT  57.852 77.009 63.306 77.593 ;
     RECT  53.424 77.009 57.042 77.597 ;
     RECT  19.656 73.913 27.666 77.645 ;
     RECT  57.852 77.593 63.882 77.657 ;
     RECT  63.288 77.657 63.882 77.741 ;
     RECT  2.415 76.649 4.266 77.791 ;
     RECT  5.115 77.309 5.397 77.791 ;
     RECT  48.315 75.767 48.726 77.819 ;
     RECT  6.552 77.309 8.097 77.971 ;
     RECT  6.552 77.971 8.19 78.029 ;
     RECT  57.852 77.657 62.154 78.061 ;
     RECT  53.424 77.597 56.826 78.089 ;
     RECT  19.656 77.645 27.63 78.221 ;
     RECT  63.288 77.741 63.342 78.269 ;
     RECT  57.816 78.061 62.154 78.403 ;
     RECT  53.424 78.089 56.79 78.539 ;
     RECT  57.816 78.403 62.766 78.709 ;
     RECT  63.828 78.571 63.882 78.763 ;
     RECT  51.015 75.119 51.642 78.773 ;
     RECT  2.304 77.791 4.266 78.809 ;
     RECT  5.004 77.791 5.397 78.809 ;
     RECT  53.424 78.539 54.738 78.809 ;
     RECT  63.828 78.763 63.918 79.007 ;
     RECT  57.636 78.709 62.766 79.015 ;
     RECT  63.828 79.007 63.882 79.015 ;
     RECT  9.396 77.117 18.897 79.037 ;
     RECT  57.636 79.015 63.882 79.079 ;
     RECT  5.115 78.809 5.397 79.141 ;
     RECT  55.548 78.539 56.79 79.213 ;
     RECT  57.636 79.079 63.342 79.213 ;
     RECT  55.548 79.213 63.342 79.277 ;
     RECT  42.915 76.577 44.154 79.313 ;
     RECT  53.424 78.809 53.997 79.349 ;
     RECT  55.548 79.277 63.306 79.547 ;
     RECT  55.548 79.547 63.27 79.583 ;
     RECT  9.396 79.037 12.366 79.613 ;
     RECT  5.115 79.141 5.49 79.619 ;
     RECT  55.548 79.583 62.802 79.619 ;
     RECT  55.944 79.619 62.802 79.709 ;
     RECT  61.236 79.709 62.802 79.757 ;
     RECT  57.564 79.709 60.39 79.781 ;
     RECT  61.236 79.757 62.73 79.817 ;
     RECT  19.692 78.221 27.63 79.853 ;
     RECT  2.415 78.809 4.266 79.915 ;
     RECT  5.115 79.619 5.397 79.951 ;
     RECT  13.215 79.037 18.897 79.951 ;
     RECT  57.564 79.781 58.122 79.979 ;
     RECT  61.236 79.817 62.097 79.979 ;
     RECT  13.104 79.951 18.897 80.093 ;
     RECT  57.816 79.979 58.122 80.249 ;
     RECT  59.115 79.781 60.39 80.249 ;
     RECT  56.415 79.709 56.754 80.285 ;
     RECT  19.692 79.853 25.974 80.789 ;
     RECT  19.764 80.789 25.974 80.813 ;
     RECT  19.764 80.813 24.786 80.909 ;
     RECT  14.832 80.093 18.897 80.923 ;
     RECT  5.004 79.951 5.397 80.969 ;
     RECT  13.104 80.093 13.986 80.969 ;
     RECT  2.304 79.915 4.266 81.005 ;
     RECT  14.832 80.923 18.99 81.101 ;
     RECT  9.396 79.613 11.718 81.149 ;
     RECT  14.832 81.101 18.897 81.149 ;
     RECT  15.192 81.149 18.897 81.197 ;
     RECT  59.115 80.249 59.886 81.239 ;
     RECT  9.396 81.149 11.142 81.389 ;
     RECT  17.352 81.197 18.897 81.677 ;
     RECT  19.764 80.909 22.842 81.725 ;
     RECT  5.115 80.969 5.397 81.739 ;
     RECT  5.115 81.739 5.49 81.779 ;
     RECT  15.192 81.197 16.197 81.917 ;
     RECT  13.215 80.969 13.986 82.013 ;
     RECT  2.415 81.005 4.266 82.111 ;
     RECT  5.115 81.779 5.397 82.111 ;
     RECT  13.215 82.013 13.95 82.111 ;
     RECT  0.036 76.493 0.486 82.139 ;
     RECT  5.004 82.111 5.397 82.157 ;
     RECT  13.104 82.111 13.95 82.157 ;
     RECT  9.936 81.389 11.142 82.211 ;
     RECT  14.94 82.123 14.958 82.219 ;
     RECT  14.832 82.219 14.958 82.253 ;
     RECT  23.616 80.909 24.786 82.253 ;
     RECT  9.936 82.211 10.818 82.283 ;
     RECT  6.552 78.029 8.097 82.445 ;
     RECT  14.832 82.253 14.85 82.445 ;
     RECT  0.108 82.139 0.486 82.489 ;
     RECT  6.552 82.445 6.858 82.493 ;
     RECT  23.616 82.253 24.297 82.541 ;
     RECT  20.232 81.725 22.842 82.715 ;
     RECT  20.232 82.715 20.25 82.733 ;
     RECT  0.108 82.489 0.558 82.747 ;
     RECT  17.424 81.677 18.897 82.759 ;
     RECT  13.215 82.157 13.95 82.787 ;
     RECT  25.92 80.813 25.974 82.829 ;
     RECT  17.424 82.759 18.954 82.831 ;
     RECT  21.024 82.715 22.842 82.859 ;
     RECT  44.136 79.313 44.154 82.859 ;
     RECT  0.108 82.747 0.594 82.925 ;
     RECT  17.424 82.831 19.386 82.973 ;
     RECT  31.32 73.517 32.397 83.069 ;
     RECT  2.304 82.111 4.266 83.129 ;
     RECT  17.424 82.973 18.897 83.291 ;
     RECT  2.415 83.129 4.266 83.371 ;
     RECT  2.415 83.371 4.374 83.501 ;
     RECT  25.956 82.829 25.974 83.597 ;
     RECT  21.315 82.859 22.842 83.641 ;
     RECT  21.315 83.641 22.914 83.795 ;
     RECT  26.715 79.853 27.63 83.837 ;
     RECT  0.108 82.925 0.558 83.885 ;
     RECT  5.115 82.157 5.397 83.899 ;
     RECT  21.315 83.795 22.842 83.933 ;
     RECT  5.115 83.899 5.49 83.939 ;
     RECT  2.415 83.501 4.05 84.139 ;
     RECT  2.304 84.139 4.05 84.335 ;
     RECT  21.315 83.933 22.626 84.365 ;
     RECT  9.936 82.283 10.797 84.605 ;
     RECT  18.615 83.291 18.897 84.619 ;
     RECT  4.032 84.335 4.05 84.653 ;
     RECT  21.315 84.365 22.05 84.653 ;
     RECT  5.115 83.939 5.397 84.712 ;
     RECT  13.215 82.787 13.497 84.712 ;
     RECT  2.304 84.335 3.294 84.749 ;
     RECT  5.004 84.712 5.397 84.749 ;
     RECT  6.84 84.619 6.858 84.749 ;
     RECT  13.104 84.712 13.497 84.749 ;
     RECT  14.832 83.803 14.85 84.749 ;
     RECT  18.615 84.619 18.918 84.749 ;
     RECT  0.18 83.885 0.558 84.883 ;
     RECT  17.424 83.291 17.442 84.989 ;
     RECT  0.072 84.883 0.558 85.109 ;
     RECT  0.144 85.109 0.558 85.133 ;
     RECT  0.252 85.133 0.558 85.325 ;
     RECT  2.415 84.749 3.294 85.517 ;
     RECT  0.252 85.325 0.522 85.613 ;
     RECT  0.252 85.613 0.486 85.709 ;
     RECT  0.252 85.709 0.378 85.805 ;
     RECT  0.252 85.805 0.27 85.901 ;
     RECT  31.608 83.069 32.397 102.965 ;
     RECT  2.415 85.517 2.697 103.157 ;
     RECT  5.115 84.749 5.397 103.157 ;
     RECT  7.815 82.445 8.097 103.157 ;
     RECT  10.515 84.605 10.797 103.157 ;
     RECT  13.215 84.749 13.497 103.157 ;
     RECT  15.915 81.917 16.197 103.157 ;
     RECT  18.615 84.749 18.897 103.157 ;
     RECT  21.315 84.653 21.597 103.157 ;
     RECT  24.015 82.541 24.297 103.157 ;
     RECT  26.715 83.837 26.997 103.157 ;
     RECT  29.415 73.373 29.697 103.157 ;
     RECT  34.815 75.695 35.097 103.157 ;
     RECT  37.515 74.417 37.797 103.157 ;
     RECT  40.215 73.949 40.497 103.157 ;
     RECT  42.915 79.313 43.197 103.157 ;
     RECT  45.615 76.199 45.897 103.157 ;
     RECT  48.315 77.819 48.597 103.157 ;
     RECT  51.015 78.773 51.297 103.157 ;
     RECT  53.715 79.349 53.997 103.157 ;
     RECT  56.415 80.285 56.697 103.157 ;
     RECT  59.115 81.239 59.397 103.157 ;
     RECT  61.815 79.979 62.097 103.157 ;
     RECT  58.104 80.249 58.122 103.199 ;
     RECT  2.607 103.157 2.697 103.427 ;
     RECT  5.307 103.157 5.397 103.427 ;
     RECT  8.007 103.157 8.097 103.427 ;
     RECT  10.707 103.157 10.797 103.427 ;
     RECT  13.407 103.157 13.497 103.427 ;
     RECT  16.107 103.157 16.197 103.427 ;
     RECT  18.807 103.157 18.897 103.427 ;
     RECT  21.507 103.157 21.597 103.427 ;
     RECT  24.207 103.157 24.297 103.427 ;
     RECT  26.907 103.157 26.997 103.427 ;
     RECT  29.607 103.157 29.697 103.427 ;
     RECT  31.68 102.965 32.397 103.427 ;
     RECT  35.007 103.157 35.097 103.427 ;
     RECT  37.707 103.157 37.797 103.427 ;
     RECT  40.407 103.157 40.497 103.427 ;
     RECT  43.107 103.157 43.197 103.427 ;
     RECT  45.807 103.157 45.897 103.427 ;
     RECT  48.507 103.157 48.597 103.427 ;
     RECT  51.207 103.157 51.297 103.427 ;
     RECT  53.907 103.157 53.997 103.427 ;
     RECT  56.607 103.157 56.697 103.427 ;
     RECT  59.307 103.157 59.397 103.427 ;
     RECT  62.007 103.157 62.097 103.427 ;
     RECT  31.68 103.427 32.274 103.565 ;
     RECT  31.68 103.565 31.698 104.909 ;
    LAYER M4 ;
     RECT  0.06 25.968 0.281 85.896 ;
     RECT  0.281 25.968 0.389 85.8 ;
     RECT  0.389 25.968 0.497 85.704 ;
     RECT  0.497 25.968 0.533 85.608 ;
     RECT  0.533 25.968 0.569 85.512 ;
     RECT  0.569 25.968 2.408 28.296 ;
     RECT  0.569 29.328 2.408 85.512 ;
     RECT  2.408 2.148 2.512 103.152 ;
     RECT  2.512 2.418 2.6 103.152 ;
     RECT  2.6 2.418 2.704 103.422 ;
     RECT  2.704 26.064 3.061 85.512 ;
     RECT  3.061 76.56 3.305 85.512 ;
     RECT  3.305 76.56 4.025 84.984 ;
     RECT  3.061 26.064 4.133 75.528 ;
     RECT  2.704 23.568 5.108 23.592 ;
     RECT  4.133 26.064 5.108 73.608 ;
     RECT  4.133 75.12 5.108 75.528 ;
     RECT  4.025 76.752 5.108 84.984 ;
     RECT  5.108 2.148 5.212 103.152 ;
     RECT  5.212 2.418 5.3 103.152 ;
     RECT  5.3 2.418 5.404 103.422 ;
     RECT  5.404 23.568 7.808 23.592 ;
     RECT  5.404 26.064 7.808 73.608 ;
     RECT  5.404 75.408 7.808 75.432 ;
     RECT  5.404 76.752 7.808 84.984 ;
     RECT  7.808 2.148 7.912 103.152 ;
     RECT  7.912 2.418 8 103.152 ;
     RECT  8 2.418 8.104 103.422 ;
     RECT  8.104 23.568 10.508 23.592 ;
     RECT  8.104 26.064 10.508 73.608 ;
     RECT  8.104 75.408 10.508 75.432 ;
     RECT  8.104 76.752 10.508 84.984 ;
     RECT  10.508 2.148 10.612 103.152 ;
     RECT  10.612 2.418 10.7 103.152 ;
     RECT  10.7 2.418 10.804 103.422 ;
     RECT  10.804 23.568 13.208 23.592 ;
     RECT  10.804 26.064 13.208 73.608 ;
     RECT  10.804 75.408 13.208 75.432 ;
     RECT  10.804 76.752 13.208 84.984 ;
     RECT  13.208 2.148 13.312 103.152 ;
     RECT  13.312 2.418 13.4 103.152 ;
     RECT  13.4 2.418 13.504 103.422 ;
     RECT  13.504 23.568 15.908 23.592 ;
     RECT  13.504 26.064 15.908 73.608 ;
     RECT  13.504 75.408 15.908 75.432 ;
     RECT  13.504 76.752 15.908 84.984 ;
     RECT  15.908 2.148 16.012 103.152 ;
     RECT  16.012 2.418 16.1 103.152 ;
     RECT  16.1 2.418 16.204 103.422 ;
     RECT  16.204 76.752 17.453 84.984 ;
     RECT  16.204 23.568 18.608 23.592 ;
     RECT  16.204 26.064 18.608 73.608 ;
     RECT  16.204 75.408 18.608 75.432 ;
     RECT  17.453 76.752 18.608 84.648 ;
     RECT  18.608 2.148 18.712 103.152 ;
     RECT  18.712 2.418 18.8 103.152 ;
     RECT  18.8 2.418 18.904 103.422 ;
     RECT  18.904 76.752 18.929 84.744 ;
     RECT  18.904 23.568 21.308 23.592 ;
     RECT  18.904 26.064 21.308 73.608 ;
     RECT  18.904 75.408 21.308 75.432 ;
     RECT  18.929 76.752 21.308 84.648 ;
     RECT  21.308 2.148 21.412 103.152 ;
     RECT  21.412 2.418 21.5 103.152 ;
     RECT  21.5 2.418 21.604 103.422 ;
     RECT  21.604 76.752 22.061 84.648 ;
     RECT  22.061 76.752 22.565 84.36 ;
     RECT  22.565 82.224 22.637 84.36 ;
     RECT  22.637 82.224 22.853 83.928 ;
     RECT  21.604 23.568 24.008 23.592 ;
     RECT  21.604 26.064 24.008 73.608 ;
     RECT  21.604 75.408 24.008 75.432 ;
     RECT  22.565 76.752 24.008 80.904 ;
     RECT  22.853 82.224 24.008 83.832 ;
     RECT  24.008 2.148 24.112 103.152 ;
     RECT  24.112 2.418 24.2 103.152 ;
     RECT  24.2 2.418 24.304 103.422 ;
     RECT  24.304 82.224 24.797 83.832 ;
     RECT  24.304 76.848 24.869 78.744 ;
     RECT  24.304 26.064 25.013 66.6 ;
     RECT  24.304 79.824 25.409 80.808 ;
     RECT  25.013 26.064 25.481 31.176 ;
     RECT  24.869 76.848 25.517 78.504 ;
     RECT  24.304 23.568 26.708 23.592 ;
     RECT  25.481 26.064 26.708 31.128 ;
     RECT  25.013 32.208 26.708 66.6 ;
     RECT  24.304 67.584 26.708 73.608 ;
     RECT  24.304 75.408 26.708 75.432 ;
     RECT  25.517 77.616 26.708 78.504 ;
     RECT  25.409 79.824 26.708 79.848 ;
     RECT  24.797 82.8 26.708 83.832 ;
     RECT  26.708 2.148 26.812 103.152 ;
     RECT  26.812 2.418 26.9 103.152 ;
     RECT  26.9 2.418 27.004 103.422 ;
     RECT  27.004 83.04 27.641 83.832 ;
     RECT  27.004 77.616 27.677 77.64 ;
     RECT  27.004 26.064 28.037 30.696 ;
     RECT  27.004 23.568 29.408 23.592 ;
     RECT  28.037 26.064 29.408 29.832 ;
     RECT  27.004 32.208 29.408 73.608 ;
     RECT  27.004 75.408 29.408 75.432 ;
     RECT  27.641 83.04 29.408 83.064 ;
     RECT  29.408 2.148 29.512 103.152 ;
     RECT  29.512 2.418 29.6 103.152 ;
     RECT  29.6 2.418 29.704 103.422 ;
     RECT  29.704 32.208 30.377 73.608 ;
     RECT  30.377 33.648 30.773 73.608 ;
     RECT  30.773 33.648 30.989 70.152 ;
     RECT  30.989 33.648 31.025 39.048 ;
     RECT  31.669 104.88 31.909 104.904 ;
     RECT  30.989 40.368 31.993 70.152 ;
     RECT  31.993 40.368 32.065 70.296 ;
     RECT  30.773 71.328 32.065 73.608 ;
     RECT  29.704 23.568 32.108 23.592 ;
     RECT  29.704 26.064 32.108 29.832 ;
     RECT  30.377 32.208 32.108 32.52 ;
     RECT  31.025 34.08 32.108 39.048 ;
     RECT  32.065 40.368 32.108 73.608 ;
     RECT  29.704 75.408 32.108 75.432 ;
     RECT  29.704 83.04 32.108 83.064 ;
     RECT  32.108 2.148 32.212 103.152 ;
     RECT  31.909 104.88 32.243 105.72 ;
     RECT  32.212 2.418 32.245 103.152 ;
     RECT  32.245 2.418 32.339 103.56 ;
     RECT  32.339 2.418 32.404 103.422 ;
     RECT  32.243 104.88 32.435 104.904 ;
     RECT  32.404 40.032 32.501 69 ;
     RECT  32.404 70.272 32.531 70.68 ;
     RECT  32.404 34.368 32.645 39 ;
     RECT  32.404 26.064 32.681 29.832 ;
     RECT  32.681 26.064 32.819 26.088 ;
     RECT  32.501 40.032 32.861 68.952 ;
     RECT  32.645 34.944 32.969 39 ;
     RECT  32.681 27.072 33.005 29.832 ;
     RECT  32.969 35.232 33.041 39 ;
     RECT  32.861 40.032 33.077 68.232 ;
     RECT  32.404 32.208 33.113 32.52 ;
     RECT  33.077 40.032 33.149 55.8 ;
     RECT  33.113 32.208 33.155 32.232 ;
     RECT  33.005 27.168 33.185 29.832 ;
     RECT  33.041 35.232 33.185 35.496 ;
     RECT  33.185 27.408 33.329 29.832 ;
     RECT  33.149 40.032 33.365 43.416 ;
     RECT  32.404 73.008 33.365 73.608 ;
     RECT  33.149 44.4 33.473 55.8 ;
     RECT  33.365 40.848 33.731 43.416 ;
     RECT  33.473 44.4 33.761 47.112 ;
     RECT  33.185 35.232 33.797 35.448 ;
     RECT  33.329 27.648 34.213 29.832 ;
     RECT  33.473 48.144 34.513 55.8 ;
     RECT  33.077 57.024 34.513 68.232 ;
     RECT  32.404 23.568 34.808 23.592 ;
     RECT  34.213 27.648 34.808 30.072 ;
     RECT  33.797 35.424 34.808 35.448 ;
     RECT  33.041 36.624 34.808 39 ;
     RECT  33.731 40.848 34.808 43.08 ;
     RECT  33.761 44.4 34.808 44.952 ;
     RECT  33.761 46.032 34.808 47.112 ;
     RECT  34.513 48.144 34.808 68.232 ;
     RECT  32.531 70.272 34.808 70.296 ;
     RECT  33.365 73.584 34.808 73.608 ;
     RECT  32.404 75.408 34.808 75.432 ;
     RECT  34.808 2.148 34.912 103.152 ;
     RECT  34.912 2.418 35 103.152 ;
     RECT  35 2.418 35.104 103.422 ;
     RECT  35.104 46.32 35.237 46.344 ;
     RECT  35.104 37.968 35.273 38.808 ;
     RECT  35.104 54.96 35.273 65.256 ;
     RECT  35.273 54.96 35.353 64.392 ;
     RECT  35.353 54.96 35.381 64.2 ;
     RECT  35.104 35.424 35.453 35.448 ;
     RECT  35.381 54.96 35.453 63.528 ;
     RECT  35.453 56.784 35.489 63.528 ;
     RECT  35.489 57.024 35.921 63.528 ;
     RECT  35.104 40.848 36.245 42.552 ;
     RECT  36.245 41.76 36.281 42.552 ;
     RECT  35.104 23.568 37.508 23.592 ;
     RECT  35.104 27.648 37.508 30.072 ;
     RECT  36.169 32.256 37.508 32.28 ;
     RECT  35.104 36.624 37.508 36.936 ;
     RECT  35.273 37.968 37.508 38.76 ;
     RECT  36.281 41.76 37.508 41.784 ;
     RECT  35.104 44.88 37.508 44.904 ;
     RECT  35.104 48.144 37.508 48.696 ;
     RECT  35.104 50.4 37.508 53.928 ;
     RECT  35.453 54.96 37.508 55.8 ;
     RECT  35.921 57.36 37.508 60.024 ;
     RECT  35.921 61.44 37.508 63.528 ;
     RECT  35.104 67.68 37.508 67.704 ;
     RECT  35.104 75.408 37.508 75.432 ;
     RECT  37.508 2.148 37.612 103.152 ;
     RECT  37.612 2.418 37.7 103.152 ;
     RECT  37.7 2.418 37.804 103.422 ;
     RECT  37.804 61.44 38.549 63.528 ;
     RECT  37.804 37.968 39.161 38.76 ;
     RECT  37.804 23.568 40.208 23.592 ;
     RECT  37.804 27.648 40.208 30.072 ;
     RECT  37.804 32.256 40.208 32.28 ;
     RECT  37.804 36.624 40.208 36.936 ;
     RECT  39.161 38.736 40.208 38.76 ;
     RECT  37.804 41.76 40.208 41.784 ;
     RECT  37.804 44.88 40.208 44.904 ;
     RECT  37.804 48.144 40.208 48.696 ;
     RECT  37.804 50.4 40.208 53.928 ;
     RECT  37.804 54.96 40.208 55.8 ;
     RECT  37.804 57.36 40.208 60.024 ;
     RECT  38.549 61.44 40.208 63.048 ;
     RECT  37.804 67.68 40.208 67.704 ;
     RECT  37.804 75.408 40.208 75.432 ;
     RECT  40.208 2.148 40.312 103.152 ;
     RECT  40.312 2.418 40.4 103.152 ;
     RECT  40.4 2.418 40.504 103.422 ;
     RECT  40.504 23.568 42.908 23.592 ;
     RECT  40.504 27.648 42.908 30.072 ;
     RECT  40.504 32.256 42.908 32.28 ;
     RECT  40.504 36.624 42.908 36.936 ;
     RECT  40.504 38.736 42.908 38.76 ;
     RECT  40.504 41.76 42.908 41.784 ;
     RECT  40.504 44.88 42.908 44.904 ;
     RECT  40.504 48.144 42.908 48.696 ;
     RECT  40.504 50.4 42.908 53.928 ;
     RECT  40.504 54.96 42.908 55.8 ;
     RECT  40.504 57.36 42.908 60.024 ;
     RECT  40.504 61.44 42.908 63.048 ;
     RECT  40.504 67.68 42.908 67.704 ;
     RECT  40.504 75.408 42.908 75.432 ;
     RECT  42.908 2.148 43.012 103.152 ;
     RECT  43.012 2.418 43.1 103.152 ;
     RECT  43.1 2.418 43.204 103.422 ;
     RECT  43.204 44.88 44.677 44.904 ;
     RECT  43.204 41.76 44.737 41.784 ;
     RECT  43.204 23.568 45.608 23.592 ;
     RECT  43.204 27.648 45.608 30.072 ;
     RECT  43.204 32.256 45.608 32.28 ;
     RECT  43.204 36.624 45.608 36.936 ;
     RECT  43.204 38.736 45.608 38.76 ;
     RECT  44.737 41.76 45.608 42.168 ;
     RECT  44.677 44.736 45.608 44.904 ;
     RECT  43.204 48.144 45.608 48.696 ;
     RECT  43.204 50.4 45.608 53.928 ;
     RECT  43.204 54.96 45.608 55.8 ;
     RECT  43.204 57.36 45.608 58.536 ;
     RECT  43.204 60 45.608 60.024 ;
     RECT  43.204 61.44 45.608 63.048 ;
     RECT  43.204 67.68 45.608 67.704 ;
     RECT  43.204 75.408 45.608 75.432 ;
     RECT  45.608 2.148 45.712 103.152 ;
     RECT  45.712 2.418 45.8 103.152 ;
     RECT  45.8 2.418 45.904 103.422 ;
     RECT  45.904 61.44 46.001 63.048 ;
     RECT  46.001 62.976 46.505 63.048 ;
     RECT  45.904 41.616 46.793 41.784 ;
     RECT  45.904 75.408 47.581 75.432 ;
     RECT  45.904 44.736 47.728 44.904 ;
     RECT  45.904 23.568 47.797 23.592 ;
     RECT  47.797 22.752 48.308 23.592 ;
     RECT  45.904 27.648 48.308 30.072 ;
     RECT  45.904 32.256 48.308 32.28 ;
     RECT  45.904 36.624 48.308 36.936 ;
     RECT  45.904 38.736 48.308 38.76 ;
     RECT  46.793 41.712 48.308 41.784 ;
     RECT  47.728 44.688 48.308 44.904 ;
     RECT  48.085 46.8 48.308 46.824 ;
     RECT  45.904 48.144 48.308 48.696 ;
     RECT  45.904 50.4 48.308 53.928 ;
     RECT  45.904 54.96 48.308 55.8 ;
     RECT  45.904 57.36 48.308 58.536 ;
     RECT  46.001 61.44 48.308 61.992 ;
     RECT  46.505 62.976 48.308 63 ;
     RECT  45.904 67.68 48.308 67.704 ;
     RECT  47.581 75.264 48.308 75.432 ;
     RECT  48.308 2.148 48.412 103.152 ;
     RECT  48.412 2.418 48.5 103.152 ;
     RECT  48.5 2.418 48.604 103.422 ;
     RECT  48.604 46.8 49.997 46.824 ;
     RECT  48.604 44.688 50.137 45 ;
     RECT  50.137 44.64 50.713 45 ;
     RECT  48.604 54.96 50.713 55.8 ;
     RECT  48.604 23.568 51.008 23.592 ;
     RECT  48.604 27.648 51.008 30.072 ;
     RECT  48.604 32.256 51.008 32.28 ;
     RECT  48.604 36.624 51.008 36.936 ;
     RECT  48.604 38.736 51.008 38.76 ;
     RECT  48.604 41.712 51.008 41.784 ;
     RECT  50.821 43.296 51.008 43.32 ;
     RECT  50.713 44.448 51.008 45 ;
     RECT  50.677 46.848 51.008 46.872 ;
     RECT  48.604 48.144 51.008 48.696 ;
     RECT  48.604 50.4 51.008 53.928 ;
     RECT  50.713 54.912 51.008 55.8 ;
     RECT  48.604 57.36 51.008 58.536 ;
     RECT  48.604 61.44 51.008 61.992 ;
     RECT  48.604 62.976 51.008 63 ;
     RECT  48.604 67.68 51.008 68.184 ;
     RECT  51.008 2.148 51.112 103.152 ;
     RECT  51.112 2.418 51.2 103.152 ;
     RECT  51.2 2.418 51.304 103.422 ;
     RECT  51.304 43.296 51.437 43.32 ;
     RECT  51.304 61.44 52.157 61.992 ;
     RECT  51.304 48.144 53.053 48.696 ;
     RECT  51.304 57.36 53.053 58.536 ;
     RECT  52.157 61.44 53.053 61.464 ;
     RECT  53.053 48.144 53.089 49.08 ;
     RECT  51.304 50.4 53.089 50.424 ;
     RECT  51.304 23.568 53.708 23.592 ;
     RECT  51.304 27.648 53.708 30.072 ;
     RECT  51.304 32.256 53.708 32.28 ;
     RECT  53.053 33.264 53.708 33.288 ;
     RECT  53.017 34.608 53.708 34.632 ;
     RECT  51.304 36.624 53.708 36.936 ;
     RECT  51.304 38.736 53.708 38.76 ;
     RECT  51.304 41.712 53.708 41.784 ;
     RECT  52.405 43.296 53.708 43.32 ;
     RECT  51.304 44.448 53.708 44.664 ;
     RECT  51.304 46.848 53.708 46.872 ;
     RECT  53.089 48.144 53.708 50.424 ;
     RECT  51.304 51.744 53.708 53.928 ;
     RECT  51.304 54.96 53.708 55.8 ;
     RECT  53.053 57.36 53.708 58.968 ;
     RECT  53.053 61.392 53.708 61.464 ;
     RECT  51.304 62.976 53.708 63 ;
     RECT  51.304 67.68 53.708 68.232 ;
     RECT  53.708 2.148 53.812 103.152 ;
     RECT  53.812 2.418 53.9 103.152 ;
     RECT  53.9 2.418 54.004 103.422 ;
     RECT  54.004 54.96 54.929 56.376 ;
     RECT  54.004 32.256 54.997 32.904 ;
     RECT  54.004 61.44 55.069 61.464 ;
     RECT  54.004 64.944 55.069 64.968 ;
     RECT  55.033 34.992 55.141 35.016 ;
     RECT  54.004 41.712 55.177 41.784 ;
     RECT  54.004 43.104 55.177 43.32 ;
     RECT  54.004 46.848 55.177 46.872 ;
     RECT  54.004 50.4 55.177 50.424 ;
     RECT  55.069 64.608 55.177 64.968 ;
     RECT  55.177 64.608 55.213 65.016 ;
     RECT  55.177 66.24 55.213 66.264 ;
     RECT  55.177 46.08 55.285 46.872 ;
     RECT  54.004 48.144 55.285 49.128 ;
     RECT  55.177 50.16 55.285 50.712 ;
     RECT  54.004 44.448 55.292 44.664 ;
     RECT  55.285 46.08 55.292 46.968 ;
     RECT  54.004 67.68 55.321 68.232 ;
     RECT  54.004 36.624 55.349 37.224 ;
     RECT  54.004 38.736 55.349 38.76 ;
     RECT  55.069 61.44 55.357 63 ;
     RECT  55.177 40.512 55.381 40.536 ;
     RECT  55.177 41.712 55.381 43.32 ;
     RECT  54.004 23.568 55.429 23.592 ;
     RECT  54.004 31.056 55.429 31.08 ;
     RECT  55.141 34.896 55.429 35.304 ;
     RECT  55.349 36.624 55.429 38.76 ;
     RECT  54.004 51.744 55.429 53.928 ;
     RECT  54.929 54.96 55.429 55.944 ;
     RECT  55.213 64.56 55.429 66.264 ;
     RECT  55.321 75.216 55.429 75.24 ;
     RECT  55.429 31.056 55.465 31.176 ;
     RECT  54.997 32.256 55.465 33.672 ;
     RECT  54.004 27.648 55.501 30.072 ;
     RECT  55.465 31.056 55.501 33.672 ;
     RECT  55.177 25.056 55.537 25.08 ;
     RECT  55.177 70.128 55.573 70.152 ;
     RECT  55.429 21.072 55.601 21.096 ;
     RECT  55.429 23.136 55.601 23.592 ;
     RECT  55.381 40.512 55.628 43.32 ;
     RECT  55.292 44.448 55.628 46.968 ;
     RECT  55.148 26.16 55.645 26.184 ;
     RECT  55.501 27.648 55.645 33.672 ;
     RECT  55.429 34.896 55.645 38.76 ;
     RECT  55.357 61.008 55.645 63 ;
     RECT  55.429 74.64 55.645 75.24 ;
     RECT  55.645 26.16 55.681 26.568 ;
     RECT  55.645 61.008 55.753 63.192 ;
     RECT  55.717 72.48 55.753 72.504 ;
     RECT  55.537 25.056 55.772 25.176 ;
     RECT  55.681 26.16 55.772 26.664 ;
     RECT  55.601 22.8 55.789 23.592 ;
     RECT  55.772 25.056 55.789 26.664 ;
     RECT  55.753 60.576 55.82 63.192 ;
     RECT  55.82 60.528 55.825 63.192 ;
     RECT  55.429 64.272 55.825 66.264 ;
     RECT  55.321 67.632 55.825 68.232 ;
     RECT  55.573 69.696 55.825 70.152 ;
     RECT  55.789 22.8 55.861 26.664 ;
     RECT  55.645 27.648 55.861 38.76 ;
     RECT  55.285 48.144 55.861 50.712 ;
     RECT  55.861 48.096 55.969 50.712 ;
     RECT  55.825 67.296 55.969 68.232 ;
     RECT  55.825 69.696 55.969 70.824 ;
     RECT  55.601 20.496 56.005 21.096 ;
     RECT  55.861 22.8 56.005 38.76 ;
     RECT  56.005 22.224 56.113 38.76 ;
     RECT  55.429 51.744 56.113 55.944 ;
     RECT  54.004 57.36 56.113 58.536 ;
     RECT  56.113 51.744 56.257 58.776 ;
     RECT  55.969 67.296 56.293 70.824 ;
     RECT  56.005 20.496 56.408 21.144 ;
     RECT  56.113 22.224 56.408 39.336 ;
     RECT  55.628 40.512 56.408 46.968 ;
     RECT  55.969 47.952 56.408 50.712 ;
     RECT  56.257 51.744 56.408 59.016 ;
     RECT  55.825 60.528 56.408 66.264 ;
     RECT  56.293 67.296 56.408 70.872 ;
     RECT  55.753 72.48 56.408 73.08 ;
     RECT  55.645 74.592 56.408 75.24 ;
     RECT  55.645 77.568 56.408 77.592 ;
     RECT  55.609 79.2 56.408 79.224 ;
     RECT  56.408 2.148 56.512 103.152 ;
     RECT  56.512 2.418 56.6 103.152 ;
     RECT  56.6 2.418 56.704 103.422 ;
     RECT  56.704 46.656 56.873 71.832 ;
     RECT  56.704 30.72 56.945 37.272 ;
     RECT  56.873 71.808 56.953 71.832 ;
     RECT  56.873 46.656 56.981 70.344 ;
     RECT  56.981 48.144 57.017 70.344 ;
     RECT  56.704 21.6 57.377 21.816 ;
     RECT  56.704 38.4 57.629 39.336 ;
     RECT  57.629 38.4 57.665 38.808 ;
     RECT  56.704 22.992 57.733 23.256 ;
     RECT  56.704 24.336 57.733 24.504 ;
     RECT  56.704 43.296 57.733 44.328 ;
     RECT  57.377 21.6 57.74 21.768 ;
     RECT  57.733 22.992 57.74 24.504 ;
     RECT  56.981 46.656 57.781 47.064 ;
     RECT  57.781 45.936 57.805 47.064 ;
     RECT  56.704 73.056 57.805 76.392 ;
     RECT  56.704 77.472 57.805 77.592 ;
     RECT  57.74 21.024 57.827 21.768 ;
     RECT  57.74 22.992 57.827 24.6 ;
     RECT  56.704 41.712 57.829 41.784 ;
     RECT  57.827 22.992 57.845 23.832 ;
     RECT  57.665 38.496 57.845 38.808 ;
     RECT  57.017 70.32 57.877 70.344 ;
     RECT  56.704 25.68 57.913 29.592 ;
     RECT  56.945 31.104 57.913 37.272 ;
     RECT  57.829 40.8 57.925 41.784 ;
     RECT  57.733 42.816 57.925 44.328 ;
     RECT  57.845 22.992 58.057 23.688 ;
     RECT  57.805 45.6 58.057 47.064 ;
     RECT  57.017 48.144 58.057 69 ;
     RECT  57.805 72.816 58.057 76.392 ;
     RECT  57.805 77.472 58.057 78.12 ;
     RECT  57.913 25.68 58.093 37.272 ;
     RECT  57.877 70.32 58.093 71.16 ;
     RECT  58.057 22.8 58.117 23.688 ;
     RECT  58.093 25.68 58.165 37.464 ;
     RECT  57.925 40.8 58.165 44.328 ;
     RECT  58.057 45.6 58.165 69 ;
     RECT  58.093 70.128 58.165 71.16 ;
     RECT  58.165 25.584 58.237 37.464 ;
     RECT  58.165 40.8 58.273 71.16 ;
     RECT  58.273 40.8 58.345 71.688 ;
     RECT  58.057 72.816 58.345 78.12 ;
     RECT  57.827 21.6 58.561 21.768 ;
     RECT  58.117 22.752 58.561 23.688 ;
     RECT  58.345 40.8 58.669 78.12 ;
     RECT  56.704 79.44 58.669 80.28 ;
     RECT  58.669 40.08 58.741 78.12 ;
     RECT  58.093 20.4 59.108 20.424 ;
     RECT  58.561 21.6 59.108 23.688 ;
     RECT  58.237 24.96 59.108 37.464 ;
     RECT  57.845 38.496 59.108 38.76 ;
     RECT  58.741 40.032 59.108 78.12 ;
     RECT  58.669 79.296 59.108 80.28 ;
     RECT  59.108 2.148 59.212 103.152 ;
     RECT  59.212 2.418 59.3 103.152 ;
     RECT  59.3 2.418 59.404 103.422 ;
     RECT  59.404 19.92 59.465 76.392 ;
     RECT  59.404 77.568 59.501 80.28 ;
     RECT  59.501 77.616 59.573 80.28 ;
     RECT  59.465 19.92 59.603 73.608 ;
     RECT  59.603 19.92 59.825 59.784 ;
     RECT  59.573 77.616 59.861 79.32 ;
     RECT  59.825 34.128 60.035 59.784 ;
     RECT  60.035 44.88 60.185 59.784 ;
     RECT  59.825 19.92 60.293 33.144 ;
     RECT  59.465 74.688 60.316 76.392 ;
     RECT  60.293 19.92 60.323 33.096 ;
     RECT  60.323 19.92 60.329 33.048 ;
     RECT  60.185 44.88 60.329 55.512 ;
     RECT  60.035 34.128 60.419 43.848 ;
     RECT  59.603 60.816 60.473 73.608 ;
     RECT  60.329 19.92 60.509 33 ;
     RECT  60.316 75.12 60.581 76.392 ;
     RECT  60.581 75.12 60.617 75.72 ;
     RECT  60.509 20.304 60.653 33 ;
     RECT  60.419 34.128 60.653 39.864 ;
     RECT  60.653 35.904 60.689 39.864 ;
     RECT  60.419 41.04 60.689 43.848 ;
     RECT  60.653 20.304 60.761 20.568 ;
     RECT  60.473 65.088 60.761 73.608 ;
     RECT  60.653 21.936 60.797 33 ;
     RECT  60.689 35.904 60.833 38.136 ;
     RECT  60.185 56.544 60.973 59.784 ;
     RECT  60.473 60.816 60.973 60.84 ;
     RECT  60.689 41.328 61.153 43.848 ;
     RECT  60.329 44.88 61.153 48.696 ;
     RECT  59.861 77.616 61.189 78.648 ;
     RECT  60.797 27.888 61.549 33 ;
     RECT  60.761 20.544 61.808 20.568 ;
     RECT  60.797 21.936 61.808 26.808 ;
     RECT  61.549 27.888 61.808 33.096 ;
     RECT  60.653 34.128 61.808 34.344 ;
     RECT  60.833 35.904 61.808 37.608 ;
     RECT  60.689 39.6 61.808 39.864 ;
     RECT  61.153 41.328 61.808 48.696 ;
     RECT  60.329 49.776 61.808 55.512 ;
     RECT  60.973 56.544 61.808 60.84 ;
     RECT  60.473 61.872 61.808 62.472 ;
     RECT  60.473 63.552 61.808 63.576 ;
     RECT  60.761 65.088 61.808 68.184 ;
     RECT  60.761 69.168 61.808 73.608 ;
     RECT  60.617 75.12 61.808 75.144 ;
     RECT  61.189 77.616 61.808 79.416 ;
     RECT  61.808 2.148 61.912 103.152 ;
     RECT  61.912 2.418 62 103.152 ;
     RECT  62 2.418 62.104 103.422 ;
     RECT  62.104 58.8 63.241 66.696 ;
     RECT  62.104 67.824 63.241 79.752 ;
     RECT  62.104 20.304 63.277 57.432 ;
     RECT  63.241 58.8 63.277 79.752 ;
     RECT  63.277 58.608 63.781 79.752 ;
     RECT  63.781 58.512 63.817 79.752 ;
     RECT  63.277 20.016 63.853 57.432 ;
     RECT  63.817 58.416 63.853 79.752 ;
     RECT  63.853 19.92 64.716 79.752 ;
     RECT  64.716 30.144 64.757 30.168 ;
     RECT  64.716 31.392 64.757 31.416 ;
     RECT  64.716 36.768 64.757 36.792 ;
     RECT  64.716 55.392 64.757 55.416 ;
     RECT  64.716 57.408 64.757 57.432 ;
     RECT  64.716 59.712 64.757 59.736 ;
     RECT  64.716 71.328 64.757 71.352 ;
    LAYER M5 ;
     RECT  2.4 2.137 2.52 2.151 ;
     RECT  5.1 2.137 5.22 2.151 ;
     RECT  7.8 2.137 7.92 2.151 ;
     RECT  10.5 2.137 10.62 2.151 ;
     RECT  13.2 2.137 13.32 2.151 ;
     RECT  15.9 2.137 16.02 2.151 ;
     RECT  18.6 2.137 18.72 2.151 ;
     RECT  21.3 2.137 21.42 2.151 ;
     RECT  24 2.137 24.12 2.151 ;
     RECT  26.7 2.137 26.82 2.151 ;
     RECT  29.4 2.137 29.52 2.151 ;
     RECT  32.1 2.137 32.22 2.151 ;
     RECT  34.8 2.137 34.92 2.151 ;
     RECT  37.5 2.137 37.62 2.151 ;
     RECT  40.2 2.137 40.32 2.151 ;
     RECT  42.9 2.137 43.02 2.151 ;
     RECT  45.6 2.137 45.72 2.151 ;
     RECT  48.3 2.137 48.42 2.151 ;
     RECT  51 2.137 51.12 2.151 ;
     RECT  53.7 2.137 53.82 2.151 ;
     RECT  56.4 2.137 56.52 2.151 ;
     RECT  59.1 2.137 59.22 2.151 ;
     RECT  61.8 2.137 61.92 2.151 ;
     RECT  56.4 2.151 56.712 20.485 ;
     RECT  61.8 2.151 62.112 20.533 ;
     RECT  55.632 20.485 56.712 21.061 ;
     RECT  57.792 21.013 57.816 21.683 ;
     RECT  48.3 2.151 48.612 22.741 ;
     RECT  59.1 2.151 59.412 22.741 ;
     RECT  60.912 20.533 62.112 23.221 ;
     RECT  58.128 22.741 59.412 23.509 ;
     RECT  57.792 23.509 59.412 23.555 ;
     RECT  2.4 2.151 2.712 23.557 ;
     RECT  57.792 23.555 57.816 23.797 ;
     RECT  59.1 23.555 59.412 24.133 ;
     RECT  60.432 23.221 62.112 24.133 ;
     RECT  55.44 21.061 56.712 24.325 ;
     RECT  57.744 23.797 57.816 24.325 ;
     RECT  59.1 24.133 62.112 25.139 ;
     RECT  32.1 2.151 32.412 26.053 ;
     RECT  29.4 2.151 29.712 26.101 ;
     RECT  55.44 24.325 57.816 26.149 ;
     RECT  55.2 26.149 57.816 26.243 ;
     RECT  32.1 26.053 32.808 26.245 ;
     RECT  57.744 26.243 57.816 26.291 ;
     RECT  24 2.151 24.312 26.485 ;
     RECT  23.904 26.485 24.312 26.627 ;
     RECT  0.144 26.869 0.168 27.155 ;
     RECT  22.8 27.061 22.824 27.683 ;
     RECT  57.744 26.291 57.768 27.733 ;
     RECT  14.832 27.637 14.856 27.923 ;
     RECT  57.744 27.733 57.864 27.971 ;
     RECT  24 26.627 24.312 28.117 ;
     RECT  23.904 28.117 24.312 28.259 ;
     RECT  57.792 27.971 57.864 28.691 ;
     RECT  55.2 26.243 56.712 28.787 ;
     RECT  59.1 25.139 60.072 28.933 ;
     RECT  53.7 2.151 54.012 29.461 ;
     RECT  53.7 29.461 54.12 29.603 ;
     RECT  31.584 26.245 32.808 29.797 ;
     RECT  2.4 23.557 3.048 30.037 ;
     RECT  31.584 29.797 33.672 30.037 ;
     RECT  34.8 2.151 35.112 30.037 ;
     RECT  2.304 30.037 3.048 30.227 ;
     RECT  7.8 2.151 8.112 30.373 ;
     RECT  6.864 30.373 8.112 30.515 ;
     RECT  64.608 30.757 64.632 30.947 ;
     RECT  55.488 28.787 56.712 31.141 ;
     RECT  57.792 28.691 57.816 31.379 ;
     RECT  59.1 28.933 60.552 31.667 ;
     RECT  59.1 31.667 60.408 31.715 ;
     RECT  55.44 31.141 56.712 32.725 ;
     RECT  59.1 31.715 60.312 33.107 ;
     RECT  22.8 34.357 22.824 34.739 ;
     RECT  55.296 32.725 56.712 34.741 ;
     RECT  59.1 33.107 60.216 34.741 ;
     RECT  55.296 34.741 57.288 34.931 ;
     RECT  24 28.259 24.312 35.125 ;
     RECT  23.904 35.125 24.312 35.267 ;
     RECT  29.4 26.101 30.552 35.269 ;
     RECT  55.44 34.931 57.288 37.283 ;
     RECT  24 35.267 24.312 37.285 ;
     RECT  23.904 37.285 24.312 37.427 ;
     RECT  0.144 37.429 0.168 37.619 ;
     RECT  55.44 37.283 56.712 38.149 ;
     RECT  59.1 34.741 60.36 38.435 ;
     RECT  58.08 38.485 58.104 38.629 ;
     RECT  24 37.427 24.312 38.917 ;
     RECT  7.8 30.515 8.112 39.013 ;
     RECT  6.864 39.013 8.112 39.155 ;
     RECT  23.904 38.917 24.312 39.587 ;
     RECT  22.8 38.485 22.824 40.403 ;
     RECT  59.1 38.435 60.264 40.405 ;
     RECT  57.84 38.629 58.104 40.981 ;
     RECT  59.1 40.405 60.408 40.981 ;
     RECT  57.84 40.981 60.408 41.075 ;
     RECT  57.84 41.075 60.264 41.267 ;
     RECT  24 39.587 24.312 41.605 ;
     RECT  57.84 41.267 59.412 41.699 ;
     RECT  7.8 39.155 8.112 41.701 ;
     RECT  23.904 41.605 24.312 41.747 ;
     RECT  55.392 38.149 56.712 41.747 ;
     RECT  6.864 41.701 8.112 41.843 ;
     RECT  22.8 41.749 22.824 41.939 ;
     RECT  57.84 41.699 58.104 41.987 ;
     RECT  45.6 2.151 45.912 42.133 ;
     RECT  51 2.151 51.312 43.285 ;
     RECT  59.1 41.699 59.412 43.669 ;
     RECT  57.84 41.987 57.96 43.765 ;
     RECT  0.192 43.861 0.216 44.099 ;
     RECT  55.44 41.747 56.712 44.533 ;
     RECT  15.9 2.151 16.212 44.677 ;
     RECT  22.8 44.341 22.824 44.723 ;
     RECT  44.784 42.133 45.912 44.725 ;
     RECT  14.928 44.677 16.212 44.915 ;
     RECT  57.84 43.765 58.056 45.925 ;
     RECT  55.344 44.533 56.712 46.645 ;
     RECT  57.792 45.925 58.056 46.645 ;
     RECT  22.8 45.781 22.824 46.739 ;
     RECT  55.344 46.645 58.056 46.837 ;
     RECT  55.296 46.837 58.056 46.979 ;
     RECT  55.44 46.979 58.056 47.075 ;
     RECT  59.1 43.669 60.072 48.371 ;
     RECT  55.44 47.075 57.096 48.467 ;
     RECT  59.1 48.371 59.412 48.949 ;
     RECT  55.44 48.467 56.712 49.139 ;
     RECT  0.144 48.997 0.168 49.187 ;
     RECT  24 41.747 24.312 49.189 ;
     RECT  24 49.189 25.128 49.379 ;
     RECT  58.992 48.949 59.412 49.523 ;
     RECT  14.832 49.189 14.856 49.571 ;
     RECT  24 49.379 24.312 49.717 ;
     RECT  59.1 49.523 59.412 50.101 ;
     RECT  7.8 41.843 8.112 50.341 ;
     RECT  23.904 49.717 24.312 50.387 ;
     RECT  28.656 35.269 30.552 50.437 ;
     RECT  31.584 30.037 35.112 50.437 ;
     RECT  57.792 50.101 57.816 50.581 ;
     RECT  59.1 50.101 60.072 50.581 ;
     RECT  6.864 50.341 8.112 50.627 ;
     RECT  56.4 49.139 56.712 50.677 ;
     RECT  57.792 50.581 60.072 50.723 ;
     RECT  57.792 50.723 59.832 50.915 ;
     RECT  0.288 50.821 0.312 50.917 ;
     RECT  0.192 50.917 0.312 50.963 ;
     RECT  0.192 50.963 0.216 51.203 ;
     RECT  56.4 50.677 56.808 52.163 ;
     RECT  58.512 50.915 59.832 52.211 ;
     RECT  28.656 50.437 35.112 52.547 ;
     RECT  61.8 25.139 62.112 53.077 ;
     RECT  53.7 29.603 54.012 53.221 ;
     RECT  61.8 53.077 62.232 53.267 ;
     RECT  15.9 44.915 16.212 53.317 ;
     RECT  53.7 53.221 54.12 53.363 ;
     RECT  56.4 52.163 56.712 53.509 ;
     RECT  14.928 53.317 16.212 53.555 ;
     RECT  28.656 52.547 30.552 53.603 ;
     RECT  31.584 52.547 35.112 53.651 ;
     RECT  56.4 53.509 56.952 53.797 ;
     RECT  24 50.387 24.312 53.845 ;
     RECT  58.512 52.211 59.412 53.845 ;
     RECT  31.632 53.651 35.112 54.131 ;
     RECT  56.304 53.797 56.952 54.227 ;
     RECT  5.1 2.151 5.412 54.373 ;
     RECT  2.4 30.227 3.048 54.565 ;
     RECT  1.152 54.373 1.176 54.659 ;
     RECT  4.992 54.373 5.412 54.659 ;
     RECT  23.904 53.845 24.312 54.707 ;
     RECT  58.032 53.845 59.412 54.851 ;
     RECT  31.872 54.131 35.112 55.043 ;
     RECT  58.512 54.851 59.412 55.139 ;
     RECT  2.304 54.565 3.048 55.187 ;
     RECT  56.304 54.227 56.712 55.379 ;
     RECT  2.4 55.187 3.048 56.197 ;
     RECT  24 54.707 24.312 56.197 ;
     RECT  23.904 56.197 24.312 56.339 ;
     RECT  2.304 56.197 3.048 56.723 ;
     RECT  31.92 55.043 35.112 56.917 ;
     RECT  56.4 55.379 56.712 57.301 ;
     RECT  22.8 48.997 22.824 57.443 ;
     RECT  56.4 57.301 57 57.539 ;
     RECT  31.056 56.917 35.112 57.635 ;
     RECT  58.608 55.139 59.412 57.829 ;
     RECT  58.608 57.829 59.592 57.973 ;
     RECT  50.832 43.285 51.312 58.115 ;
     RECT  31.824 57.635 35.112 58.307 ;
     RECT  28.656 53.603 29.712 58.309 ;
     RECT  58.128 57.973 59.592 59.315 ;
     RECT  58.608 59.315 59.592 59.987 ;
     RECT  44.688 44.725 45.912 60.035 ;
     RECT  56.4 57.539 56.952 60.517 ;
     RECT  55.872 60.517 56.952 60.757 ;
     RECT  55.872 60.757 57 60.899 ;
     RECT  55.872 60.899 56.952 60.995 ;
     RECT  31.92 58.307 35.112 61.043 ;
     RECT  24 56.339 24.312 61.045 ;
     RECT  56.4 60.995 56.952 61.139 ;
     RECT  23.904 61.045 24.312 61.187 ;
     RECT  28.656 58.309 30.216 61.571 ;
     RECT  58.608 59.987 59.412 61.621 ;
     RECT  22.8 59.461 22.824 62.531 ;
     RECT  58.608 61.621 59.544 62.821 ;
     RECT  2.4 56.723 3.048 63.061 ;
     RECT  24 61.187 24.312 63.541 ;
     RECT  23.904 63.541 24.312 63.683 ;
     RECT  2.304 63.061 3.048 63.827 ;
     RECT  31.92 61.043 33.144 63.875 ;
     RECT  34.224 61.043 35.112 64.021 ;
     RECT  34.224 64.021 35.304 64.403 ;
     RECT  58.464 62.821 59.544 64.451 ;
     RECT  24 63.683 24.312 64.789 ;
     RECT  2.4 63.827 3.048 64.837 ;
     RECT  23.904 64.789 24.312 64.931 ;
     RECT  56.4 61.139 56.712 64.933 ;
     RECT  58.464 64.451 59.412 64.933 ;
     RECT  2.304 64.837 3.048 64.979 ;
     RECT  22.8 64.789 22.824 64.979 ;
     RECT  0.192 65.461 0.216 65.699 ;
     RECT  21.3 2.151 21.612 66.229 ;
     RECT  14.832 66.229 14.856 66.277 ;
     RECT  15.9 53.555 16.212 66.277 ;
     RECT  21.3 66.229 22.008 66.277 ;
     RECT  14.832 66.277 16.212 66.515 ;
     RECT  14.832 66.515 14.856 66.611 ;
     RECT  21.3 66.277 22.824 66.611 ;
     RECT  22.8 66.611 22.824 66.707 ;
     RECT  2.4 64.979 3.048 66.709 ;
     RECT  28.656 61.571 29.712 66.755 ;
     RECT  34.224 64.403 35.112 66.755 ;
     RECT  2.4 66.709 3.192 66.899 ;
     RECT  56.4 64.933 59.412 67.331 ;
     RECT  24 64.931 24.312 67.525 ;
     RECT  23.904 67.525 24.312 67.667 ;
     RECT  56.4 67.331 56.712 68.629 ;
     RECT  58.464 67.331 59.412 68.629 ;
     RECT  24 67.667 24.312 69.157 ;
     RECT  23.904 69.157 24.312 69.299 ;
     RECT  58.464 68.629 59.544 69.635 ;
     RECT  58.512 69.635 59.544 70.163 ;
     RECT  15.9 66.515 16.212 70.261 ;
     RECT  14.928 70.261 16.212 70.403 ;
     RECT  22.8 69.733 22.824 70.595 ;
     RECT  31.92 63.875 32.52 70.691 ;
     RECT  0.24 70.789 0.264 70.931 ;
     RECT  24 69.299 24.312 71.317 ;
     RECT  23.904 71.317 24.312 71.459 ;
     RECT  56.4 68.629 56.904 71.843 ;
     RECT  24 71.459 24.312 73.285 ;
     RECT  23.904 73.285 24.312 73.523 ;
     RECT  0.144 73.333 0.168 73.571 ;
     RECT  58.512 70.163 59.412 73.765 ;
     RECT  0.336 73.813 0.456 74.339 ;
     RECT  56.4 71.843 56.712 74.581 ;
     RECT  0.336 74.339 0.36 74.675 ;
     RECT  58.416 73.765 59.412 74.677 ;
     RECT  58.416 74.677 60.264 75.251 ;
     RECT  47.808 22.741 48.612 75.299 ;
     RECT  56.4 74.581 57.288 75.299 ;
     RECT  2.4 66.899 3.048 75.875 ;
     RECT  56.4 75.299 56.808 76.403 ;
     RECT  56.4 76.403 56.712 77.461 ;
     RECT  58.416 75.251 59.412 77.939 ;
     RECT  56.4 77.461 56.808 80.147 ;
     RECT  7.8 50.627 8.112 80.581 ;
     RECT  6.864 80.581 8.112 80.867 ;
     RECT  0.384 80.821 0.408 80.963 ;
     RECT  0.576 82.741 0.6 82.979 ;
     RECT  2.4 75.875 2.712 103.419 ;
     RECT  5.1 54.659 5.412 103.419 ;
     RECT  7.8 80.867 8.112 103.419 ;
     RECT  10.5 2.151 10.812 103.419 ;
     RECT  13.2 2.151 13.512 103.419 ;
     RECT  15.9 70.403 16.212 103.419 ;
     RECT  18.6 2.151 18.912 103.419 ;
     RECT  21.3 66.611 21.612 103.419 ;
     RECT  24 73.523 24.312 103.419 ;
     RECT  26.7 2.151 27.012 103.419 ;
     RECT  29.4 66.755 29.712 103.419 ;
     RECT  34.8 66.755 35.112 103.419 ;
     RECT  37.5 2.151 37.812 103.419 ;
     RECT  40.2 2.151 40.512 103.419 ;
     RECT  42.9 2.151 43.212 103.419 ;
     RECT  45.6 60.035 45.912 103.419 ;
     RECT  48.3 75.299 48.612 103.419 ;
     RECT  51 58.115 51.312 103.419 ;
     RECT  53.7 53.363 54.012 103.419 ;
     RECT  56.4 80.147 56.712 103.419 ;
     RECT  59.1 77.939 59.412 103.419 ;
     RECT  61.8 53.267 62.112 103.419 ;
     RECT  2.592 103.419 2.712 103.433 ;
     RECT  5.292 103.419 5.412 103.433 ;
     RECT  7.992 103.419 8.112 103.433 ;
     RECT  10.692 103.419 10.812 103.433 ;
     RECT  13.392 103.419 13.512 103.433 ;
     RECT  16.092 103.419 16.212 103.433 ;
     RECT  18.792 103.419 18.912 103.433 ;
     RECT  21.492 103.419 21.612 103.433 ;
     RECT  24.192 103.419 24.312 103.433 ;
     RECT  26.892 103.419 27.012 103.433 ;
     RECT  29.592 103.419 29.712 103.433 ;
     RECT  31.92 70.691 32.412 103.433 ;
     RECT  34.992 103.419 35.112 103.433 ;
     RECT  37.692 103.419 37.812 103.433 ;
     RECT  40.392 103.419 40.512 103.433 ;
     RECT  43.092 103.419 43.212 103.433 ;
     RECT  45.792 103.419 45.912 103.433 ;
     RECT  48.492 103.419 48.612 103.433 ;
     RECT  51.192 103.419 51.312 103.433 ;
     RECT  53.892 103.419 54.012 103.433 ;
     RECT  56.592 103.419 56.712 103.433 ;
     RECT  59.292 103.419 59.412 103.433 ;
     RECT  61.992 103.419 62.112 103.433 ;
     RECT  31.92 103.433 32.328 104.869 ;
     RECT  31.92 104.869 32.424 105.731 ;
     RECT  32.208 105.731 32.424 105.744 ;
  END
END qfd_rlyh0_600_EW_65x106
END LIBRARY
